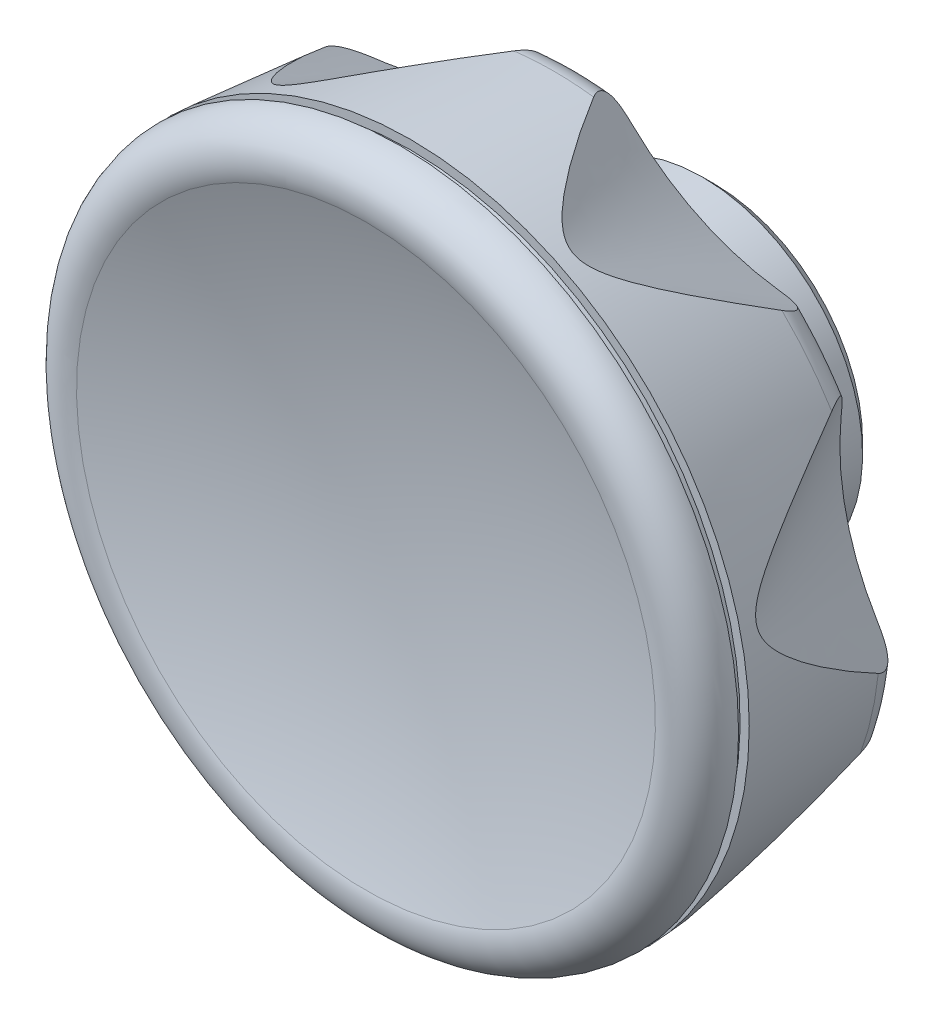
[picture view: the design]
ISO-10303-21;
HEADER;
FILE_DESCRIPTION(('STEP AP214'),'2;1');
FILE_NAME('part.step','',(''),(''),'','','');
FILE_SCHEMA(('AUTOMOTIVE_DESIGN { 1 0 10303 214 1 1 1 1 }'));
ENDSEC;
DATA;
#1=APPLICATION_CONTEXT('core data for automotive mechanical design processes');
#2=APPLICATION_PROTOCOL_DEFINITION('international standard','automotive_design',2000,#1);
#3=PRODUCT_CONTEXT('',#1,'mechanical');
#4=PRODUCT('Part','Part','',(#3));
#5=PRODUCT_RELATED_PRODUCT_CATEGORY('part','',(#4));
#6=PRODUCT_DEFINITION_FORMATION('','',#4);
#7=PRODUCT_DEFINITION_CONTEXT('part definition',#1,'design');
#8=PRODUCT_DEFINITION('design','',#6,#7);
#9=PRODUCT_DEFINITION_SHAPE('','',#8);
#10=(LENGTH_UNIT() NAMED_UNIT(*) SI_UNIT(.MILLI.,.METRE.));
#11=(NAMED_UNIT(*) PLANE_ANGLE_UNIT() SI_UNIT($,.RADIAN.));
#12=(NAMED_UNIT(*) SI_UNIT($,.STERADIAN.) SOLID_ANGLE_UNIT());
#13=UNCERTAINTY_MEASURE_WITH_UNIT(LENGTH_MEASURE(1.E-05),#10,'distance_accuracy_value','');
#14=(GEOMETRIC_REPRESENTATION_CONTEXT(3) GLOBAL_UNCERTAINTY_ASSIGNED_CONTEXT((#13)) GLOBAL_UNIT_ASSIGNED_CONTEXT((#10,
#11,#12)) REPRESENTATION_CONTEXT('',''));
#15=CARTESIAN_POINT('',(0.,0.,0.));
#16=DIRECTION('',(0.,0.,1.));
#17=DIRECTION('',(1.,0.,0.));
#18=AXIS2_PLACEMENT_3D('',#15,#16,#17);
#19=CARTESIAN_POINT('',(0.,0.,13.5));
#20=DIRECTION('',(0.,0.,1.));
#21=DIRECTION('',(0.,1.,0.));
#22=AXIS2_PLACEMENT_3D('',#19,#20,#21);
#23=TOROIDAL_SURFACE('',#22,24.4738282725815,2.4999999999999);
#24=CARTESIAN_POINT('',(0.,0.,11.));
#25=DIRECTION('',(0.,0.,1.));
#26=DIRECTION('',(0.,1.,0.));
#27=AXIS2_PLACEMENT_3D('',#24,#25,#26);
#28=CIRCLE('',#27,24.4738282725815);
#29=CARTESIAN_POINT('',(-16.2379624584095,18.3111126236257,11.));
#30=VERTEX_POINT('',#29);
#31=CARTESIAN_POINT('',(-21.4653013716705,11.7562369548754,11.));
#32=VERTEX_POINT('',#31);
#33=EDGE_CURVE('E135',#30,#32,#28,.T.);
#34=ORIENTED_EDGE('',*,*,#33,.T.);
#35=CARTESIAN_POINT('',(-21.4653013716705,11.7562369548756,11.));
#36=CARTESIAN_POINT('',(-21.4754382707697,11.8601222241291,11.000030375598));
#37=CARTESIAN_POINT('',(-21.4872751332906,11.9639124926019,11.0020766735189));
#38=CARTESIAN_POINT('',(-21.5148402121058,12.1711325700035,11.0112222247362));
#39=CARTESIAN_POINT('',(-21.5305827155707,12.2745596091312,11.0183402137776));
#40=CARTESIAN_POINT('',(-21.5666560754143,12.4816775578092,11.0388207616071));
#41=CARTESIAN_POINT('',(-21.5870535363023,12.5853482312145,11.0522773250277));
#42=CARTESIAN_POINT('',(-21.6327777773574,12.79018793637,11.086761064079));
#43=CARTESIAN_POINT('',(-21.6580966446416,12.8913606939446,11.1077761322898));
#44=CARTESIAN_POINT('',(-21.7159025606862,13.096009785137,11.1604458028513));
#45=CARTESIAN_POINT('',(-21.7487343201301,13.1992460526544,11.1926745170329));
#46=CARTESIAN_POINT('',(-21.8208966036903,13.3985520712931,11.2692171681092));
#47=CARTESIAN_POINT('',(-21.8602062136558,13.494643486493,11.313492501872));
#48=CARTESIAN_POINT('',(-21.9242907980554,13.631369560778,11.3905180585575));
#49=CARTESIAN_POINT('',(-21.9466893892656,13.6760092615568,11.4182052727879));
#50=CARTESIAN_POINT('',(-21.9930436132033,13.7619364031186,11.4772174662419));
#51=CARTESIAN_POINT('',(-22.0169983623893,13.8032257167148,11.5085403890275));
#52=CARTESIAN_POINT('',(-22.0662965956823,13.8818232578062,11.574842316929));
#53=CARTESIAN_POINT('',(-22.0916394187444,13.919133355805,11.6098195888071));
#54=CARTESIAN_POINT('',(-22.1434758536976,13.9891694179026,11.6833341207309));
#55=CARTESIAN_POINT('',(-22.1699692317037,14.0218963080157,11.7218706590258));
#56=CARTESIAN_POINT('',(-22.2204575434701,14.0784837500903,11.7972787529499));
#57=CARTESIAN_POINT('',(-22.2443568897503,14.1029401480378,11.8337680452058));
#58=CARTESIAN_POINT('',(-22.2925479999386,14.147619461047,11.9090357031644));
#59=CARTESIAN_POINT('',(-22.3168398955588,14.1678409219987,11.9478148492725));
#60=CARTESIAN_POINT('',(-22.3655101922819,14.2038164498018,12.0272744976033));
#61=CARTESIAN_POINT('',(-22.3898884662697,14.2195754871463,12.0679528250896));
#62=CARTESIAN_POINT('',(-22.4384945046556,14.2465760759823,12.1508760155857));
#63=CARTESIAN_POINT('',(-22.4627222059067,14.2578158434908,12.1931214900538));
#64=CARTESIAN_POINT('',(-22.5288434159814,14.2825299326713,12.3109990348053));
#65=CARTESIAN_POINT('',(-22.5703388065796,14.2913426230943,12.3878768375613));
#66=CARTESIAN_POINT('',(-22.6510509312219,14.2958836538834,12.5432786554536));
#67=CARTESIAN_POINT('',(-22.6902625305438,14.2915835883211,12.6218058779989));
#68=CARTESIAN_POINT('',(-22.7755265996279,14.2684993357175,12.7992847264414));
#69=CARTESIAN_POINT('',(-22.8206927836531,14.246227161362,12.8982168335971));
#70=CARTESIAN_POINT('',(-22.8841902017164,14.2010917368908,13.044286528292));
#71=CARTESIAN_POINT('',(-22.9046065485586,14.184142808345,13.0924834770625));
#72=CARTESIAN_POINT('',(-22.9440559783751,14.146710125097,13.187982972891));
#73=CARTESIAN_POINT('',(-22.9630908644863,14.1262311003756,13.2352866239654));
#74=CARTESIAN_POINT('',(-22.9814573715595,14.1041446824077,13.2821097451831));
#75=B_SPLINE_CURVE_WITH_KNOTS('',3,(#35,#36,#37,#38,#39,#40,#41,#42,#43,#44,#45,#46,#47,#48,#49,
#50,#51,#52,#53,#54,#55,#56,#57,#58,#59,#60,#61,#62,#63,#64,#65,#66,#67,#68,#69,#70,#71,#72,#73,
#74),.UNSPECIFIED.,.F.,.F.,(4,2,2,2,2,2,2,2,2,2,2,2,2,2,2,2,2,2,2,4),(0.,0.313209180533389,
0.627581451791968,0.946770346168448,1.26545021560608,1.60369981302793,1.94087800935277,
2.11199734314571,2.28302035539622,2.45396261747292,2.62487029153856,2.77466826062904,
2.92451758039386,3.07419932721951,3.22394010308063,3.48614173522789,3.74891177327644,
4.08027673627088,4.24522540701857,4.40995475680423),.UNSPECIFIED.);
#76=CARTESIAN_POINT('',(-22.981457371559,14.1041446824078,13.2821097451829));
#77=VERTEX_POINT('',#76);
#78=EDGE_CURVE('E119',#32,#77,#75,.T.);
#79=ORIENTED_EDGE('',*,*,#78,.T.);
#80=CARTESIAN_POINT('',(0.,0.,13.282109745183));
#81=DIRECTION('',(0.,0.,1.));
#82=DIRECTION('',(0.,1.,0.));
#83=AXIS2_PLACEMENT_3D('',#80,#81,#82);
#84=CIRCLE('',#83,26.9643149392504);
#85=CARTESIAN_POINT('',(-18.8643796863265,19.2667968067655,13.282109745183));
#86=VERTEX_POINT('',#85);
#87=EDGE_CURVE('E150',#86,#77,#84,.T.);
#88=ORIENTED_EDGE('',*,*,#87,.F.);
#89=CARTESIAN_POINT('',(-18.8643796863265,19.2667968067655,13.282109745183));
#90=CARTESIAN_POINT('',(-18.8981743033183,19.2226732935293,13.1915305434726));
#91=CARTESIAN_POINT('',(-18.9255552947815,19.1772447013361,13.0988167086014));
#92=CARTESIAN_POINT('',(-18.9651950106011,19.0843052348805,12.9100927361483));
#93=CARTESIAN_POINT('',(-18.9773008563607,19.0367781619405,12.8140590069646));
#94=CARTESIAN_POINT('',(-18.983341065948,18.9407957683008,12.6209607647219));
#95=CARTESIAN_POINT('',(-18.9771650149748,18.8923365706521,12.5238935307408));
#96=CARTESIAN_POINT('',(-18.9442986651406,18.7968510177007,12.3329550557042));
#97=CARTESIAN_POINT('',(-18.917699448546,18.7498192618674,12.2390715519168));
#98=CARTESIAN_POINT('',(-18.8474169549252,18.6641060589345,12.0674765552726));
#99=CARTESIAN_POINT('',(-18.8058006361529,18.6250650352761,11.9890989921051));
#100=CARTESIAN_POINT('',(-18.7069025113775,18.5516039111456,11.8403817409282));
#101=CARTESIAN_POINT('',(-18.6496092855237,18.5171872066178,11.7700479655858));
#102=CARTESIAN_POINT('',(-18.5279204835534,18.457227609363,11.6454449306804));
#103=CARTESIAN_POINT('',(-18.4646762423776,18.4311577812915,11.5902907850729));
#104=CARTESIAN_POINT('',(-18.3299240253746,18.3843608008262,11.4887242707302));
#105=CARTESIAN_POINT('',(-18.2584221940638,18.3636297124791,11.4423054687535));
#106=CARTESIAN_POINT('',(-18.0741590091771,18.3189481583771,11.3379996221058));
#107=CARTESIAN_POINT('',(-17.9578593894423,18.2981009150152,11.2850492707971));
#108=CARTESIAN_POINT('',(-17.7173155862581,18.2668011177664,11.1949523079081));
#109=CARTESIAN_POINT('',(-17.5930199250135,18.2564250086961,11.1579230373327));
#110=CARTESIAN_POINT('',(-17.3654004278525,18.2458816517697,11.1030967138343));
#111=CARTESIAN_POINT('',(-17.2626807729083,18.2441255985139,11.0829631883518));
#112=CARTESIAN_POINT('',(-17.0560091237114,18.2457463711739,11.0499258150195));
#113=CARTESIAN_POINT('',(-16.9520556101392,18.2491303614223,11.0370320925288));
#114=CARTESIAN_POINT('',(-16.7461255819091,18.260237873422,11.0174873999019));
#115=CARTESIAN_POINT('',(-16.6441552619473,18.2678653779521,11.0107067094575));
#116=CARTESIAN_POINT('',(-16.4406884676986,18.2868392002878,11.0019849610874));
#117=CARTESIAN_POINT('',(-16.3391915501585,18.2981729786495,11.000027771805));
#118=CARTESIAN_POINT('',(-16.2379624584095,18.3111126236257,11.));
#119=B_SPLINE_CURVE_WITH_KNOTS('',3,(#89,#90,#91,#92,#93,#94,#95,#96,#97,#98,#99,#100,#101,#102,
#103,#104,#105,#106,#107,#108,#109,#110,#111,#112,#113,#114,#115,#116,#117,#118),.UNSPECIFIED.,
.F.,.F.,(4,2,2,2,2,2,2,2,2,2,2,2,2,2,4),(0.,0.319088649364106,0.641346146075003,
0.96555390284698,1.28832411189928,1.57749027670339,1.86686764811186,2.12940978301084,
2.39175780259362,2.77800167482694,3.16704536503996,3.48068996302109,3.79477212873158,
4.10202079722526,4.40824052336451),.UNSPECIFIED.);
#120=EDGE_CURVE('E140',#86,#30,#119,.T.);
#121=ORIENTED_EDGE('',*,*,#120,.T.);
#122=EDGE_LOOP('',(#34,#79,#88,#121));
#123=FACE_BOUND('',#122,.T.);
#124=ADVANCED_FACE('F14',(#123),#23,.T.);
#125=CARTESIAN_POINT('',(-26.8251366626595,-2.73611461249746,13.282109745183));
#126=VERTEX_POINT('',#125);
#127=CARTESIAN_POINT('',(-25.355768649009,-9.17383651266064,13.282109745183));
#128=VERTEX_POINT('',#127);
#129=EDGE_CURVE('E157',#126,#128,#84,.T.);
#130=ORIENTED_EDGE('',*,*,#129,.F.);
#131=CARTESIAN_POINT('',(-26.8251366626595,-2.73611461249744,13.282109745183));
#132=CARTESIAN_POINT('',(-26.8117101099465,-2.79004686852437,13.1915305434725));
#133=CARTESIAN_POINT('',(-26.7932643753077,-2.83977845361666,13.0988167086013));
#134=CARTESIAN_POINT('',(-26.7453163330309,-2.92871684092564,12.9100927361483));
#135=CARTESIAN_POINT('',(-26.7157060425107,-2.96781421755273,12.8140590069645));
#136=CARTESIAN_POINT('',(-26.6444299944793,-3.0323806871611,12.620960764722));
#137=CARTESIAN_POINT('',(-26.602692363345,-3.0577658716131,12.5238935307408));
#138=CARTESIAN_POINT('',(-26.507546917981,-3.09160419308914,12.3329550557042));
#139=CARTESIAN_POINT('',(-26.4541916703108,-3.10013190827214,12.2390715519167));
#140=CARTESIAN_POINT('',(-26.3433579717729,-3.09862415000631,12.0674765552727));
#141=CARTESIAN_POINT('',(-26.2868871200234,-3.09042888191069,11.9890989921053));
#142=CARTESIAN_POINT('',(-26.1677909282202,-3.05890947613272,11.8403817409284));
#143=CARTESIAN_POINT('',(-26.1051611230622,-3.03557429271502,11.7700479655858));
#144=CARTESIAN_POINT('',(-25.9824110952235,-2.97781835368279,11.6454449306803));
#145=CARTESIAN_POINT('',(-25.9225967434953,-2.94462628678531,11.590290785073));
#146=CARTESIAN_POINT('',(-25.8019927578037,-2.86845020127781,11.4887242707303));
#147=CARTESIAN_POINT('',(-25.7412038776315,-2.82547344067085,11.4423054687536));
#148=CARTESIAN_POINT('',(-25.5913842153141,-2.70926917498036,11.3379996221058));
#149=CARTESIAN_POINT('',(-25.5025735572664,-2.63134051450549,11.2850492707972));
#150=CARTESIAN_POINT('',(-25.3281257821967,-2.46279090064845,11.194952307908));
#151=CARTESIAN_POINT('',(-25.2425163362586,-2.37208203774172,11.1579230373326));
#152=CARTESIAN_POINT('',(-25.0923547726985,-2.20069562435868,11.1030967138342));
#153=CARTESIAN_POINT('',(-25.0269371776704,-2.12148104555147,11.0829631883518));
#154=CARTESIAN_POINT('',(-24.8993466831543,-1.95888810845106,11.0499258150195));
#155=CARTESIAN_POINT('',(-24.8371784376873,-1.87550409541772,11.0370320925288));
#156=CARTESIAN_POINT('',(-24.7174673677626,-1.70757609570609,11.0174873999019));
#157=CARTESIAN_POINT('',(-24.6598533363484,-1.62309681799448,11.0107067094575));
#158=CARTESIAN_POINT('',(-24.5478281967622,-1.45219008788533,11.0019849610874));
#159=CARTESIAN_POINT('',(-24.4934070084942,-1.365770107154,11.000027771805));
#160=CARTESIAN_POINT('',(-24.4404083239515,-1.27855827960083,11.));
#161=B_SPLINE_CURVE_WITH_KNOTS('',3,(#131,#132,#133,#134,#135,#136,#137,#138,#139,#140,#141,
#142,#143,#144,#145,#146,#147,#148,#149,#150,#151,#152,#153,#154,#155,#156,#157,#158,#159,#160),
.UNSPECIFIED.,.F.,.F.,(4,2,2,2,2,2,2,2,2,2,2,2,2,2,4),(0.,0.319088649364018,0.641346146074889,
0.965553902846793,1.288324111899,1.57749027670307,1.8668676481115,2.12940978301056,
2.39175780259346,2.77800167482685,3.16704536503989,3.4806899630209,3.79477212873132,
4.10202079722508,4.40824052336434),.UNSPECIFIED.);
#162=CARTESIAN_POINT('',(-24.4404083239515,-1.27855827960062,11.));
#163=VERTEX_POINT('',#162);
#164=EDGE_CURVE('E34',#126,#163,#161,.T.);
#165=ORIENTED_EDGE('',*,*,#164,.T.);
#166=CARTESIAN_POINT('',(-22.5747926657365,-9.45235454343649,11.));
#167=VERTEX_POINT('',#166);
#168=EDGE_CURVE('E137',#163,#167,#28,.T.);
#169=ORIENTED_EDGE('',*,*,#168,.T.);
#170=CARTESIAN_POINT('',(-22.5747926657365,-9.45235454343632,11.));
#171=CARTESIAN_POINT('',(-22.6623336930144,-9.39550848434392,11.000030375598));
#172=CARTESIAN_POINT('',(-22.7508603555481,-9.34005074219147,11.0020766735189));
#173=CARTESIAN_POINT('',(-22.930058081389,-9.23240238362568,11.0112222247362));
#174=CARTESIAN_POINT('',(-23.0207358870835,-9.18022466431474,11.0183402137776));
#175=CARTESIAN_POINT('',(-23.2051585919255,-9.07929202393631,11.0388207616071));
#176=CARTESIAN_POINT('',(-23.2989291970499,-9.03060179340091,11.0522773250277));
#177=CARTESIAN_POINT('',(-23.4875879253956,-8.93863497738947,11.0867610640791));
#178=CARTESIAN_POINT('',(-23.5824740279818,-8.89534988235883,11.1077761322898));
#179=CARTESIAN_POINT('',(-23.7785165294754,-8.81294774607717,11.1604458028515));
#180=CARTESIAN_POINT('',(-23.8797001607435,-8.77424988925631,11.1926745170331));
#181=CARTESIAN_POINT('',(-24.0805163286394,-8.70640336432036,11.2692171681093));
#182=CARTESIAN_POINT('',(-24.1801527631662,-8.67722483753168,11.3134925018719));
#183=CARTESIAN_POINT('',(-24.3270055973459,-8.64208087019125,11.3905180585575));
#184=CARTESIAN_POINT('',(-24.3758716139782,-8.63176039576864,11.4182052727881));
#185=CARTESIAN_POINT('',(-24.4719535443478,-8.6144268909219,11.4772174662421));
#186=CARTESIAN_POINT('',(-24.5191703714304,-8.60741200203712,11.5085403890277));
#187=CARTESIAN_POINT('',(-24.611357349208,-8.59695014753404,11.5748423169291));
#188=CARTESIAN_POINT('',(-24.6563285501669,-8.59350149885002,11.6098195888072));
#189=CARTESIAN_POINT('',(-24.7434044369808,-8.59036208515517,11.683334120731));
#190=CARTESIAN_POINT('',(-24.785509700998,-8.59067055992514,11.721870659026));
#191=CARTESIAN_POINT('',(-24.8612304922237,-8.594862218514,11.79727875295));
#192=CARTESIAN_POINT('',(-24.8952522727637,-8.59829916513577,11.8337680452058));
#193=CARTESIAN_POINT('',(-24.960230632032,-8.60811939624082,11.9090357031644));
#194=CARTESIAN_POINT('',(-24.9911861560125,-8.61450369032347,11.9478148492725));
#195=CARTESIAN_POINT('',(-25.0496583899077,-8.63012528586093,12.0272744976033));
#196=CARTESIAN_POINT('',(-25.0771789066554,-8.63935938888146,12.0679528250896));
#197=CARTESIAN_POINT('',(-25.1285941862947,-8.66052652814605,12.1508760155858));
#198=CARTESIAN_POINT('',(-25.152487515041,-8.67246062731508,12.1931214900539));
#199=CARTESIAN_POINT('',(-25.2130356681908,-8.70874728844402,12.3109990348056));
#200=CARTESIAN_POINT('',(-25.2457976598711,-8.73569506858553,12.3878768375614));
#201=CARTESIAN_POINT('',(-25.2996711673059,-8.79596706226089,12.5432786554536));
#202=CARTESIAN_POINT('',(-25.3207572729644,-8.82930497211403,12.621805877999));
#203=CARTESIAN_POINT('',(-25.3558705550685,-8.91035990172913,12.7992847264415));
#204=CARTESIAN_POINT('',(-25.3666181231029,-8.9595587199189,12.8982168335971));
#205=CARTESIAN_POINT('',(-25.3709198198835,-9.03734447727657,13.0442865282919));
#206=CARTESIAN_POINT('',(-25.3703979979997,-9.0638741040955,13.0924834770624));
#207=CARTESIAN_POINT('',(-25.3657282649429,-9.11805580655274,13.1879829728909));
#208=CARTESIAN_POINT('',(-25.3615851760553,-9.14570634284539,13.2352866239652));
#209=CARTESIAN_POINT('',(-25.355768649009,-9.17383651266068,13.282109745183));
#210=B_SPLINE_CURVE_WITH_KNOTS('',3,(#170,#171,#172,#173,#174,#175,#176,#177,#178,#179,#180,
#181,#182,#183,#184,#185,#186,#187,#188,#189,#190,#191,#192,#193,#194,#195,#196,#197,#198,#199,
#200,#201,#202,#203,#204,#205,#206,#207,#208,#209),.UNSPECIFIED.,.F.,.F.,(4,2,2,2,2,2,2,2,2,2,2,
2,2,2,2,2,2,2,2,4),(0.,0.313209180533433,0.627581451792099,0.946770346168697,1.26545021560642,
1.60369981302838,1.9408780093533,2.11199734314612,2.28302035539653,2.45396261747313,
2.62487029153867,2.77466826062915,2.92451758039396,3.07419932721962,3.22394010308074,
3.48614173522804,3.74891177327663,4.08027673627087,4.24522540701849,4.40995475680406),.UNSPECIFIED.);
#211=EDGE_CURVE('E301',#167,#128,#210,.T.);
#212=ORIENTED_EDGE('',*,*,#211,.T.);
#213=EDGE_LOOP('',(#130,#165,#169,#212));
#214=FACE_BOUND('',#213,.T.);
#215=ADVANCED_FACE('F411',(#214),#23,.T.);
#216=CARTESIAN_POINT('',(-14.586018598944,-22.6786759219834,13.282109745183));
#217=VERTEX_POINT('',#216);
#218=CARTESIAN_POINT('',(-8.63666897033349,-25.5437317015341,13.282109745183));
#219=VERTEX_POINT('',#218);
#220=EDGE_CURVE('E161',#217,#219,#84,.T.);
#221=ORIENTED_EDGE('',*,*,#220,.F.);
#222=CARTESIAN_POINT('',(-14.586018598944,-22.6786759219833,13.282109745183));
#223=CARTESIAN_POINT('',(-14.5354813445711,-22.7018048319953,13.1915305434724));
#224=CARTESIAN_POINT('',(-14.4850988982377,-22.7183905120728,13.0988167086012));
#225=CARTESIAN_POINT('',(-14.3856689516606,-22.736355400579,12.9100927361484));
#226=CARTESIAN_POINT('',(-14.336639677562,-22.7375819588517,12.8140590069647));
#227=CARTESIAN_POINT('',(-14.2417196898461,-22.7221126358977,12.620960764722));
#228=CARTESIAN_POINT('',(-14.1958497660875,-22.7053082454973,12.5238935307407));
#229=CARTESIAN_POINT('',(-14.1100716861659,-22.6520183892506,12.3329550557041));
#230=CARTESIAN_POINT('',(-14.070137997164,-22.6156205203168,12.2390715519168));
#231=CARTESIAN_POINT('',(-14.0022131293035,-22.5280271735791,12.0674765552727));
#232=CARTESIAN_POINT('',(-13.9734114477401,-22.4787668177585,11.9890989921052));
#233=CARTESIAN_POINT('',(-13.9237990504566,-22.3660016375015,11.8403817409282));
#234=CARTESIAN_POINT('',(-13.9029941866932,-22.3024864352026,11.7700479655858));
#235=CARTESIAN_POINT('',(-13.8716162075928,-22.1705063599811,11.6454449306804));
#236=CARTESIAN_POINT('',(-13.8602731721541,-22.1030467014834,11.590290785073));
#237=CARTESIAN_POINT('',(-13.8446346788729,-21.9612596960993,11.4887242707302));
#238=CARTESIAN_POINT('',(-13.8403340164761,-21.8869374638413,11.4423054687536));
#239=CARTESIAN_POINT('',(-13.8377751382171,-21.6973515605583,11.3379996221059));
#240=CARTESIAN_POINT('',(-13.8433296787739,-21.5793288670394,11.2850492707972));
#241=CARTESIAN_POINT('',(-13.8663406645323,-21.3378511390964,11.194952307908));
#242=CARTESIAN_POINT('',(-13.8838830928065,-21.2143629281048,11.1579230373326));
#243=CARTESIAN_POINT('',(-13.9242541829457,-20.9901042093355,11.1030967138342));
#244=CARTESIAN_POINT('',(-13.9453994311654,-20.8895691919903,11.0829631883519));
#245=CARTESIAN_POINT('',(-13.9929683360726,-20.6884398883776,11.0499258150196));
#246=CARTESIAN_POINT('',(-14.0193993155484,-20.5878457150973,11.0370320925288));
#247=CARTESIAN_POINT('',(-14.0760520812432,-20.3895504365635,11.0174873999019));
#248=CARTESIAN_POINT('',(-14.1061788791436,-20.2918340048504,11.0107067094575));
#249=CARTESIAN_POINT('',(-14.1699526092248,-20.097690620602,11.0019849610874));
#250=CARTESIAN_POINT('',(-14.2035874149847,-20.001260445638,11.000027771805));
#251=CARTESIAN_POINT('',(-14.238728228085,-19.9054487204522,11.));
#252=B_SPLINE_CURVE_WITH_KNOTS('',3,(#222,#223,#224,#225,#226,#227,#228,#229,#230,#231,#232,
#233,#234,#235,#236,#237,#238,#239,#240,#241,#242,#243,#244,#245,#246,#247,#248,#249,#250,#251),
.UNSPECIFIED.,.F.,.F.,(4,2,2,2,2,2,2,2,2,2,2,2,2,2,4),(0.,0.319088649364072,0.641346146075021,
0.965553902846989,1.28832411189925,1.5774902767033,1.86686764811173,2.12940978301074,
2.39175780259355,2.77800167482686,3.16704536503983,3.48068996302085,3.79477212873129,
4.10202079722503,4.40824052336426),.UNSPECIFIED.);
#253=CARTESIAN_POINT('',(-14.238728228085,-19.905448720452,11.));
#254=VERTEX_POINT('',#253);
#255=EDGE_CURVE('E42',#217,#254,#252,.T.);
#256=ORIENTED_EDGE('',*,*,#255,.T.);
#257=CARTESIAN_POINT('',(-6.685004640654,-23.5431302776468,11.));
#258=VERTEX_POINT('',#257);
#259=EDGE_CURVE('E147',#254,#258,#28,.T.);
#260=ORIENTED_EDGE('',*,*,#259,.T.);
#261=CARTESIAN_POINT('',(-6.685004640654,-23.5431302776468,11.));
#262=CARTESIAN_POINT('',(-6.78402961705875,-23.5761296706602,11.000030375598));
#263=CARTESIAN_POINT('',(-6.88258369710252,-23.6107652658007,11.0020766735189));
#264=CARTESIAN_POINT('',(-7.07847452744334,-23.6837500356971,11.0112222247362));
#265=CARTESIAN_POINT('',(-7.17580539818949,-23.7221125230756,11.0183402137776));
#266=CARTESIAN_POINT('',(-7.36970338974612,-23.8033695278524,11.0388207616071));
#267=CARTESIAN_POINT('',(-7.46623596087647,-23.8463244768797,11.0522773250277));
#268=CARTESIAN_POINT('',(-7.65576530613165,-23.9364834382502,11.0867610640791));
#269=CARTESIAN_POINT('',(-7.74876747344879,-23.9836805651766,11.1077761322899));
#270=CARTESIAN_POINT('',(-7.93542255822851,-24.0855758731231,11.1604458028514));
#271=CARTESIAN_POINT('',(-8.02876472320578,-24.1405567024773,11.192674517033));
#272=CARTESIAN_POINT('',(-8.2070161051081,-24.2552594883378,11.2692171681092));
#273=CARTESIAN_POINT('',(-8.29195109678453,-24.3149658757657,11.313492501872));
#274=CARTESIAN_POINT('',(-8.41098900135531,-24.4078681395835,11.3905180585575));
#275=CARTESIAN_POINT('',(-8.44952533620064,-24.4396384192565,11.418205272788));
#276=CARTESIAN_POINT('',(-8.52298331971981,-24.5039510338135,11.477217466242));
#277=CARTESIAN_POINT('',(-8.55790699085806,-24.5364929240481,11.5085403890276));
#278=CARTESIAN_POINT('',(-8.62356403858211,-24.602044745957,11.5748423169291));
#279=CARTESIAN_POINT('',(-8.65429938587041,-24.6350544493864,11.6098195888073));
#280=CARTESIAN_POINT('',(-8.71104480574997,-24.7011757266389,11.683334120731));
#281=CARTESIAN_POINT('',(-8.73705583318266,-24.7342872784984,11.7218706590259));
#282=CARTESIAN_POINT('',(-8.78098980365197,-24.796101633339,11.7972787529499));
#283=CARTESIAN_POINT('',(-8.79951492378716,-24.824843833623,11.8337680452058));
#284=CARTESIAN_POINT('',(-8.8323505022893,-24.8817687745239,11.9090357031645));
#285=CARTESIAN_POINT('',(-8.84665951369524,-24.9099513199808,11.9478148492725));
#286=CARTESIAN_POINT('',(-8.87090290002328,-24.9654066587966,12.0272744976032));
#287=CARTESIAN_POINT('',(-8.88084214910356,-24.9926804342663,12.0679528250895));
#288=CARTESIAN_POINT('',(-8.89634991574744,-25.0460760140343,12.1508760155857));
#289=CARTESIAN_POINT('',(-8.90191670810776,-25.0721973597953,12.1931214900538));
#290=CARTESIAN_POINT('',(-8.91129781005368,-25.1421601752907,12.3109990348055));
#291=CARTESIAN_POINT('',(-8.91065595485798,-25.1845761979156,12.3878768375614));
#292=CARTESIAN_POINT('',(-8.8971229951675,-25.2642751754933,12.5432786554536));
#293=CARTESIAN_POINT('',(-8.88420533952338,-25.3015468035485,12.621805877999));
#294=CARTESIAN_POINT('',(-8.84272681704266,-25.3795363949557,12.7992847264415));
#295=CARTESIAN_POINT('',(-8.81096263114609,-25.4186141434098,12.8982168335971));
#296=CARTESIAN_POINT('',(-8.75282934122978,-25.4704759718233,13.044286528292));
#297=CARTESIAN_POINT('',(-8.73176229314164,-25.486608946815,13.0924834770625));
#298=CARTESIAN_POINT('',(-8.68648980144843,-25.5167397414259,13.187982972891));
#299=CARTESIAN_POINT('',(-8.66228856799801,-25.5307403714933,13.2352866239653));
#300=CARTESIAN_POINT('',(-8.63666897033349,-25.5437317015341,13.2821097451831));
#301=B_SPLINE_CURVE_WITH_KNOTS('',3,(#261,#262,#263,#264,#265,#266,#267,#268,#269,#270,#271,
#272,#273,#274,#275,#276,#277,#278,#279,#280,#281,#282,#283,#284,#285,#286,#287,#288,#289,#290,
#291,#292,#293,#294,#295,#296,#297,#298,#299,#300),.UNSPECIFIED.,.F.,.F.,(4,2,2,2,2,2,2,2,2,2,2,
2,2,2,2,2,2,2,2,4),(0.,0.313209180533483,0.627581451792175,0.946770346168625,1.26545021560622,
1.60369981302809,1.940878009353,2.11199734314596,2.28302035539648,2.45396261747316,
2.62487029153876,2.77466826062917,2.92451758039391,3.07419932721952,3.22394010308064,
3.48614173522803,3.74891177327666,4.0802767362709,4.24522540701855,4.40995475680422),.UNSPECIFIED.);
#302=EDGE_CURVE('E317',#258,#219,#301,.T.);
#303=ORIENTED_EDGE('',*,*,#302,.T.);
#304=EDGE_LOOP('',(#221,#256,#260,#303));
#305=FACE_BOUND('',#304,.T.);
#306=ADVANCED_FACE('F441',(#305),#23,.T.);
#307=CARTESIAN_POINT('',(8.636668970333,-25.5437317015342,13.282109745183));
#308=VERTEX_POINT('',#307);
#309=CARTESIAN_POINT('',(14.586018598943,-22.6786759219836,13.282109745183));
#310=VERTEX_POINT('',#309);
#311=EDGE_CURVE('E449',#308,#310,#84,.T.);
#312=ORIENTED_EDGE('',*,*,#311,.F.);
#313=CARTESIAN_POINT('',(8.636668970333,-25.5437317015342,13.2821097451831));
#314=CARTESIAN_POINT('',(8.68626134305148,-25.5186407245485,13.1915305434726));
#315=CARTESIAN_POINT('',(8.73064149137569,-25.4895911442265,13.0988167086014));
#316=CARTESIAN_POINT('',(8.80668056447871,-25.4230546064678,12.9100927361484));
#317=CARTESIAN_POINT('',(8.83820877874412,-25.3854867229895,12.8140590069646));
#318=CARTESIAN_POINT('',(8.88529601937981,-25.3016303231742,12.6209607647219));
#319=CARTESIAN_POINT('',(8.90075724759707,-25.2552904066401,12.5238935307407));
#320=CARTESIAN_POINT('',(8.91257531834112,-25.1550007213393,12.3329550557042));
#321=CARTESIAN_POINT('',(8.90901656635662,-25.1010856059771,12.2390715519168));
#322=CARTESIAN_POINT('',(8.88288379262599,-24.9933662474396,12.0674765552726));
#323=CARTESIAN_POINT('',(8.8623280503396,-24.9401348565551,11.9890989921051));
#324=CARTESIAN_POINT('',(8.80509750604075,-24.8310383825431,11.8403817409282));
#325=CARTESIAN_POINT('',(8.76841094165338,-24.7751714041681,11.7700479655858));
#326=CARTESIAN_POINT('',(8.68478861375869,-24.6683508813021,11.6454449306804));
#327=CARTESIAN_POINT('',(8.63911879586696,-24.6174221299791,11.5902907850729));
#328=CARTESIAN_POINT('',(8.53801569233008,-24.5167927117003,11.4887242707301));
#329=CARTESIAN_POINT('',(8.48258965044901,-24.4670911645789,11.4423054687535));
#330=CARTESIAN_POINT('',(8.33596085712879,-24.3468856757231,11.3379996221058));
#331=CARTESIAN_POINT('',(8.24022380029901,-24.277642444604,11.285049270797));
#332=CARTESIAN_POINT('',(8.03708179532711,-24.1450742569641,11.194952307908));
#333=CARTESIAN_POINT('',(7.9295972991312,-24.081795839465,11.1579230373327));
#334=CARTESIAN_POINT('',(7.72909380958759,-23.9735362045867,11.1030967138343));
#335=CARTESIAN_POINT('',(7.63730852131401,-23.9273856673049,11.0829631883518));
#336=CARTESIAN_POINT('',(7.45040057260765,-23.8391744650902,11.0499258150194));
#337=CARTESIAN_POINT('',(7.35527343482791,-23.7971195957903,11.0370320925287));
#338=CARTESIAN_POINT('',(7.16491752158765,-23.7177774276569,11.0174873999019));
#339=CARTESIAN_POINT('',(7.06973598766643,-23.6804063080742,11.0107067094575));
#340=CARTESIAN_POINT('',(6.87818630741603,-23.6092201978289,11.0019849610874));
#341=CARTESIAN_POINT('',(6.78182320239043,-23.5753937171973,11.000027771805));
#342=CARTESIAN_POINT('',(6.6850046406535,-23.543130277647,11.));
#343=B_SPLINE_CURVE_WITH_KNOTS('',3,(#313,#314,#315,#316,#317,#318,#319,#320,#321,#322,#323,
#324,#325,#326,#327,#328,#329,#330,#331,#332,#333,#334,#335,#336,#337,#338,#339,#340,#341,#342),
.UNSPECIFIED.,.F.,.F.,(4,2,2,2,2,2,2,2,2,2,2,2,2,2,4),(0.,0.319088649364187,0.641346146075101,
0.965553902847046,1.28832411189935,1.57749027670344,1.86686764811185,2.12940978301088,
2.39175780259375,2.77800167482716,3.16704536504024,3.48068996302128,3.79477212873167,
4.1020207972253,4.40824052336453),.UNSPECIFIED.);
#344=CARTESIAN_POINT('',(6.685004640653,-23.5431302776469,11.));
#345=VERTEX_POINT('',#344);
#346=EDGE_CURVE('E310',#308,#345,#343,.T.);
#347=ORIENTED_EDGE('',*,*,#346,.T.);
#348=CARTESIAN_POINT('',(14.2387282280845,-19.9054487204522,11.));
#349=VERTEX_POINT('',#348);
#350=EDGE_CURVE('E443',#345,#349,#28,.T.);
#351=ORIENTED_EDGE('',*,*,#350,.T.);
#352=CARTESIAN_POINT('',(14.2387282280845,-19.9054487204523,11.));
#353=CARTESIAN_POINT('',(14.202787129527,-20.0034443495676,11.000030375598));
#354=CARTESIAN_POINT('',(14.168418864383,-20.1020919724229,11.0020766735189));
#355=CARTESIAN_POINT('',(14.1033447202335,-20.3007508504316,11.0112222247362));
#356=CARTESIAN_POINT('',(14.0726529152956,-20.4007658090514,11.0183402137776));
#357=CARTESIAN_POINT('',(14.0152887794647,-20.6030242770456,11.038820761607));
#358=CARTESIAN_POINT('',(13.9886852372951,-20.7052784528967,11.0522773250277));
#359=CARTESIAN_POINT('',(13.9410047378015,-20.9096716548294,11.086761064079));
#360=CARTESIAN_POINT('',(13.9199190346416,-21.0118106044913,11.1077761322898));
#361=CARTESIAN_POINT('',(13.8832064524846,-21.2212741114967,11.1604458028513));
#362=CARTESIAN_POINT('',(13.8679943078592,-21.3285319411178,11.1926745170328));
#363=CARTESIAN_POINT('',(13.8465346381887,-21.5394105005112,11.269217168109));
#364=CARTESIAN_POINT('',(13.8402588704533,-21.6430416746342,11.3134925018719));
#365=CARTESIAN_POINT('',(13.8386738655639,-21.7940328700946,11.3905180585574));
#366=CARTESIAN_POINT('',(13.8394858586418,-21.843970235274,11.4182052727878));
#367=CARTESIAN_POINT('',(13.8439671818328,-21.9415002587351,11.4772174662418));
#368=CARTESIAN_POINT('',(13.8476349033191,-21.9890942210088,11.5085403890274));
#369=CARTESIAN_POINT('',(13.8579488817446,-22.0812978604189,11.5748423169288));
#370=CARTESIAN_POINT('',(13.8645937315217,-22.1259089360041,11.609819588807));
#371=CARTESIAN_POINT('',(13.8809092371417,-22.2115002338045,11.6833341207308));
#372=CARTESIAN_POINT('',(13.8905792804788,-22.2524811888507,11.7218706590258));
#373=CARTESIAN_POINT('',(13.9115153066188,-22.3253707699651,11.7972787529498));
#374=CARTESIAN_POINT('',(13.9224366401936,-22.3577747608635,11.8337680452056));
#375=CARTESIAN_POINT('',(13.9464697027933,-22.4189387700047,11.9090357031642));
#376=CARTESIAN_POINT('',(13.9595821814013,-22.4476975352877,11.9478148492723));
#377=CARTESIAN_POINT('',(13.9878234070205,-22.5012276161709,12.0272744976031));
#378=CARTESIAN_POINT('',(14.0029498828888,-22.5260033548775,12.0679528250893));
#379=CARTESIAN_POINT('',(14.0350272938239,-22.5714194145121,12.1508760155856));
#380=CARTESIAN_POINT('',(14.0519789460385,-22.5920581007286,12.1931214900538));
#381=CARTESIAN_POINT('',(14.1008290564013,-22.6430136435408,12.3109990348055));
#382=CARTESIAN_POINT('',(14.1343914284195,-22.6689577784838,12.3878768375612));
#383=CARTESIAN_POINT('',(14.2051402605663,-22.7080687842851,12.5432786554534));
#384=CARTESIAN_POINT('',(14.2423344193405,-22.7212078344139,12.6218058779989));
#385=CARTESIAN_POINT('',(14.3291705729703,-22.7374043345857,12.7992847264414));
#386=CARTESIAN_POINT('',(14.3795274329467,-22.7369346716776,12.898216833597));
#387=CARTESIAN_POINT('',(14.4563201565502,-22.7238195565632,13.0442865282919));
#388=CARTESIAN_POINT('',(14.4820685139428,-22.7174074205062,13.0924834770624));
#389=CARTESIAN_POINT('',(14.5338526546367,-22.7007982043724,13.1879829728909));
#390=CARTESIAN_POINT('',(14.5598880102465,-22.6906061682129,13.2352866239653));
#391=CARTESIAN_POINT('',(14.586018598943,-22.6786759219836,13.2821097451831));
#392=B_SPLINE_CURVE_WITH_KNOTS('',3,(#352,#353,#354,#355,#356,#357,#358,#359,#360,#361,#362,
#363,#364,#365,#366,#367,#368,#369,#370,#371,#372,#373,#374,#375,#376,#377,#378,#379,#380,#381,
#382,#383,#384,#385,#386,#387,#388,#389,#390,#391),.UNSPECIFIED.,.F.,.F.,(4,2,2,2,2,2,2,2,2,2,2,
2,2,2,2,2,2,2,2,4),(0.,0.313209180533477,0.627581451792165,0.946770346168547,1.26545021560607,
1.60369981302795,1.94087800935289,2.11199734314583,2.28302035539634,2.45396261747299,
2.62487029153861,2.77466826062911,2.9245175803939,3.07419932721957,3.22394010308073,
3.48614173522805,3.74891177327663,4.08027673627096,4.24522540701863,4.40995475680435),.UNSPECIFIED.);
#393=EDGE_CURVE('E333',#349,#310,#392,.T.);
#394=ORIENTED_EDGE('',*,*,#393,.T.);
#395=EDGE_LOOP('',(#312,#347,#351,#394));
#396=FACE_BOUND('',#395,.T.);
#397=ADVANCED_FACE('F422',(#396),#23,.T.);
#398=CARTESIAN_POINT('',(25.3557686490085,-9.17383651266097,13.282109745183));
#399=VERTEX_POINT('',#398);
#400=CARTESIAN_POINT('',(26.825136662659,-2.73611461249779,13.282109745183));
#401=VERTEX_POINT('',#400);
#402=EDGE_CURVE('E168',#399,#401,#84,.T.);
#403=ORIENTED_EDGE('',*,*,#402,.F.);
#404=CARTESIAN_POINT('',(25.3557686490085,-9.17383651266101,13.282109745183));
#405=CARTESIAN_POINT('',(25.3670720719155,-9.11941966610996,13.1915305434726));
#406=CARTESIAN_POINT('',(25.3720307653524,-9.06660975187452,13.0988167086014));
#407=CARTESIAN_POINT('',(25.3674199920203,-8.96567515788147,12.9100927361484));
#408=CARTESIAN_POINT('',(25.3577057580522,-8.91760221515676,12.8140590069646));
#409=CARTESIAN_POINT('',(25.3215025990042,-8.82850431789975,12.6209607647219));
#410=CARTESIAN_POINT('',(25.294912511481,-8.78752377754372,12.5238935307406));
#411=CARTESIAN_POINT('',(25.2238713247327,-8.71575444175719,12.3329550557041));
#412=CARTESIAN_POINT('',(25.1794999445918,-8.68492126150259,12.2390715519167));
#413=CARTESIAN_POINT('',(25.0789880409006,-8.63819076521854,12.0674765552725));
#414=CARTESIAN_POINT('',(25.0245537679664,-8.62107266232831,11.989098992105));
#415=CARTESIAN_POINT('',(24.9035760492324,-8.59779676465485,11.8403817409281));
#416=CARTESIAN_POINT('',(24.8370237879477,-8.59164698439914,11.7700479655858));
#417=CARTESIAN_POINT('',(24.7013704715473,-8.5904240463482,11.6454449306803));
#418=CARTESIAN_POINT('',(24.633078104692,-8.59437659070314,11.5902907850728));
#419=CARTESIAN_POINT('',(24.4913661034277,-8.61068076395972,11.4887242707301));
#420=CARTESIAN_POINT('',(24.4179502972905,-8.62302618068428,11.4423054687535));
#421=CARTESIAN_POINT('',(24.2325483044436,-8.66271829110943,11.3379996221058));
#422=CARTESIAN_POINT('',(24.1187206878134,-8.69439608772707,11.285049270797));
#423=CARTESIAN_POINT('',(23.8884177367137,-8.77056398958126,11.1949523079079));
#424=CARTESIAN_POINT('',(23.771929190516,-8.815145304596,11.1579230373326));
#425=CARTESIAN_POINT('',(23.5622765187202,-8.90440646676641,11.1030967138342));
#426=CARTESIAN_POINT('',(23.4689673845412,-8.94739270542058,11.0829631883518));
#427=CARTESIAN_POINT('',(23.2834658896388,-9.03852443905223,11.0499258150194));
#428=CARTESIAN_POINT('',(23.1912752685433,-9.08667704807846,11.0370320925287));
#429=CARTESIAN_POINT('',(23.0105580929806,-9.18603426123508,11.0174873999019));
#430=CARTESIAN_POINT('',(22.9219954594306,-9.23714966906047,11.0107067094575));
#431=CARTESIAN_POINT('',(22.746910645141,-9.342525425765,11.0019849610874));
#432=CARTESIAN_POINT('',(22.6603826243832,-9.39677466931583,11.000027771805));
#433=CARTESIAN_POINT('',(22.5747926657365,-9.45235454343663,11.));
#434=B_SPLINE_CURVE_WITH_KNOTS('',3,(#404,#405,#406,#407,#408,#409,#410,#411,#412,#413,#414,
#415,#416,#417,#418,#419,#420,#421,#422,#423,#424,#425,#426,#427,#428,#429,#430,#431,#432,#433),
.UNSPECIFIED.,.F.,.F.,(4,2,2,2,2,2,2,2,2,2,2,2,2,2,4),(0.,0.319088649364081,0.641346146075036,
0.965553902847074,1.28832411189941,1.5774902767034,1.86686764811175,2.12940978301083,
2.39175780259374,2.77800167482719,3.1670453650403,3.48068996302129,3.79477212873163,
4.10202079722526,4.40824052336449),.UNSPECIFIED.);
#435=CARTESIAN_POINT('',(22.574792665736,-9.45235454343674,11.));
#436=VERTEX_POINT('',#435);
#437=EDGE_CURVE('E326',#399,#436,#434,.T.);
#438=ORIENTED_EDGE('',*,*,#437,.T.);
#439=CARTESIAN_POINT('',(24.440408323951,-1.27855827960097,11.));
#440=VERTEX_POINT('',#439);
#441=EDGE_CURVE('E156',#436,#440,#28,.T.);
#442=ORIENTED_EDGE('',*,*,#441,.T.);
#443=CARTESIAN_POINT('',(24.4404083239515,-1.2785582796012,11.));
#444=CARTESIAN_POINT('',(24.4946154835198,-1.36775743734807,11.000030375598));
#445=CARTESIAN_POINT('',(24.5503130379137,-1.45613341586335,11.0020766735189));
#446=CARTESIAN_POINT('',(24.6650577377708,-1.6308722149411,11.0112222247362));
#447=CARTESIAN_POINT('',(24.724116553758,-1.71722634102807,11.0183402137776));
#448=CARTESIAN_POINT('',(24.8464826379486,-1.88818152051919,11.038820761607));
#449=CARTESIAN_POINT('',(24.9098411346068,-1.97273544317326,11.0522773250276));
#450=CARTESIAN_POINT('',(25.0399138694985,-2.13745063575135,11.086761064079));
#451=CARTESIAN_POINT('',(25.1066225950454,-2.21761869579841,11.1077761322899));
#452=CARTESIAN_POINT('',(25.2474978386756,-2.37692010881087,11.1604458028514));
#453=CARTESIAN_POINT('',(25.3218707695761,-2.45568760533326,11.1926745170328));
#454=CARTESIAN_POINT('',(25.4733623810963,-2.60394608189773,11.269217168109));
#455=CARTESIAN_POINT('',(25.5504716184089,-2.67346565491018,11.3134925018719));
#456=CARTESIAN_POINT('',(25.667533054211,-2.76884633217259,11.3905180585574));
#457=CARTESIAN_POINT('',(25.7070819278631,-2.7993469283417,11.4182052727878));
#458=CARTESIAN_POINT('',(25.7861280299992,-2.85665226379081,11.4772174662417));
#459=CARTESIAN_POINT('',(25.8256252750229,-2.88345907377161,11.5085403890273));
#460=CARTESIAN_POINT('',(25.9041436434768,-2.93288330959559,11.5748423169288));
#461=CARTESIAN_POINT('',(25.9431649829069,-2.95550270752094,11.6098195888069));
#462=CARTESIAN_POINT('',(26.0202555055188,-2.99611203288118,11.6833341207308));
#463=CARTESIAN_POINT('',(26.0583248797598,-3.01410289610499,11.7218706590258));
#464=CARTESIAN_POINT('',(26.1283656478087,-3.04318036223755,11.7972787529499));
#465=CARTESIAN_POINT('',(26.1605094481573,-3.05484527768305,11.8337680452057));
#466=CARTESIAN_POINT('',(26.2233137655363,-3.074190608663,11.9090357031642));
#467=CARTESIAN_POINT('',(26.2539737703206,-3.08186965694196,11.9478148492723));
#468=CARTESIAN_POINT('',(26.3134333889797,-3.09316523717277,12.0272744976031));
#469=CARTESIAN_POINT('',(26.3422350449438,-3.09678630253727,12.0679528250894));
#470=CARTESIAN_POINT('',(26.3977426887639,-3.10002362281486,12.1508760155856));
#471=CARTESIAN_POINT('',(26.4244478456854,-3.09963829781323,12.1931214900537));
#472=CARTESIAN_POINT('',(26.4947440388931,-3.09321600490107,12.3109990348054));
#473=CARTESIAN_POINT('',(26.5359537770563,-3.08315178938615,12.3878768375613));
#474=CARTESIAN_POINT('',(26.6106431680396,-3.05222343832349,12.5432786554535));
#475=CARTESIAN_POINT('',(26.6441058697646,-3.03133593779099,12.6218058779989));
#476=CARTESIAN_POINT('',(26.7109102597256,-2.9735430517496,12.7992847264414));
#477=CARTESIAN_POINT('',(26.7419400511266,-2.93387964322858,12.8982168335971));
#478=CARTESIAN_POINT('',(26.7795657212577,-2.86566353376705,13.044286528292));
#479=CARTESIAN_POINT('',(26.7906063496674,-2.84153475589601,13.0924834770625));
#480=CARTESIAN_POINT('',(26.8099076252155,-2.79069260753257,13.1879829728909));
#481=CARTESIAN_POINT('',(26.818171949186,-2.7639827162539,13.2352866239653));
#482=CARTESIAN_POINT('',(26.825136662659,-2.73611461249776,13.282109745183));
#483=B_SPLINE_CURVE_WITH_KNOTS('',3,(#443,#444,#445,#446,#447,#448,#449,#450,#451,#452,#453,
#454,#455,#456,#457,#458,#459,#460,#461,#462,#463,#464,#465,#466,#467,#468,#469,#470,#471,#472,
#473,#474,#475,#476,#477,#478,#479,#480,#481,#482),.UNSPECIFIED.,.F.,.F.,(4,2,2,2,2,2,2,2,2,2,2,
2,2,2,2,2,2,2,2,4),(0.,0.313209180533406,0.627581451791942,0.946770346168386,1.26545021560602,
1.60369981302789,1.94087800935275,2.11199734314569,2.2830203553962,2.45396261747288,
2.62487029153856,2.77466826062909,2.9245175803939,3.07419932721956,3.22394010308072,
3.48614173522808,3.74891177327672,4.08027673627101,4.2452254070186,4.40995475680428),.UNSPECIFIED.);
#484=EDGE_CURVE('E373',#440,#401,#483,.T.);
#485=ORIENTED_EDGE('',*,*,#484,.T.);
#486=EDGE_LOOP('',(#403,#438,#442,#485));
#487=FACE_BOUND('',#486,.T.);
#488=ADVANCED_FACE('F413',(#487),#23,.T.);
#489=CARTESIAN_POINT('',(22.981457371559,14.1041446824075,13.282109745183));
#490=VERTEX_POINT('',#489);
#491=CARTESIAN_POINT('',(18.8643796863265,19.2667968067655,13.282109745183));
#492=VERTEX_POINT('',#491);
#493=EDGE_CURVE('E163',#490,#492,#84,.T.);
#494=ORIENTED_EDGE('',*,*,#493,.F.);
#495=CARTESIAN_POINT('',(22.981457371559,14.1041446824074,13.282109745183));
#496=CARTESIAN_POINT('',(22.9459601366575,14.1469104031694,13.1915305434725));
#497=CARTESIAN_POINT('',(22.9077633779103,14.1837137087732,13.0988167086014));
#498=CARTESIAN_POINT('',(22.8259747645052,14.2430405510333,12.9100927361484));
#499=CARTESIAN_POINT('',(22.7823330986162,14.2654186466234,12.8140590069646));
#500=CARTESIAN_POINT('',(22.6901012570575,14.2926655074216,12.6209607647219));
#501=CARTESIAN_POINT('',(22.6414827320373,14.2974274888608,12.5238935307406));
#502=CARTESIAN_POINT('',(22.5410777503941,14.2866327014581,12.3329550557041));
#503=CARTESIAN_POINT('',(22.4893062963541,14.2711659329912,12.2390715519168));
#504=CARTESIAN_POINT('',(22.390102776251,14.2217185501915,12.0674765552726));
#505=CARTESIAN_POINT('',(22.3427800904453,14.1898330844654,11.989098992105));
#506=CARTESIAN_POINT('',(22.2491538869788,14.1097611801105,11.8403817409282));
#507=CARTESIAN_POINT('',(22.2028511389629,14.0615628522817,11.7700479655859));
#508=CARTESIAN_POINT('',(22.1173165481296,13.9562673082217,11.6454449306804));
#509=CARTESIAN_POINT('',(22.0778271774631,13.9004098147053,11.5902907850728));
#510=CARTESIAN_POINT('',(22.0022183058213,13.7794494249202,11.48872427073));
#511=CARTESIAN_POINT('',(21.9660963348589,13.7143533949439,11.4423054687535));
#512=CARTESIAN_POINT('',(21.8815326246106,13.5446526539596,11.3379996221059));
#513=CARTESIAN_POINT('',(21.8353289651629,13.4359078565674,11.285049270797));
#514=CARTESIAN_POINT('',(21.7512878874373,13.2083598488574,11.1949523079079));
#515=CARTESIAN_POINT('',(21.7135135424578,13.089489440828,11.1579230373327));
#516=CARTESIAN_POINT('',(21.6525844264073,12.8699229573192,11.1030967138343));
#517=CARTESIAN_POINT('',(21.6280151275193,12.7701694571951,11.0829631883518));
#518=CARTESIAN_POINT('',(21.5836064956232,12.5683188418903,11.0499258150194));
#519=CARTESIAN_POINT('',(21.5637738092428,12.4662186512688,11.0370320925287));
#520=CARTESIAN_POINT('',(21.5287790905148,12.2629800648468,11.0174873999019));
#521=CARTESIAN_POINT('',(21.5135248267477,12.1618690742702,11.0107067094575));
#522=CARTESIAN_POINT('',(21.4867473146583,11.959281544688,11.0019849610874));
#523=CARTESIAN_POINT('',(21.475211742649,11.8578073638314,11.000027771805));
#524=CARTESIAN_POINT('',(21.4653013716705,11.7562369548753,11.));
#525=B_SPLINE_CURVE_WITH_KNOTS('',3,(#495,#496,#497,#498,#499,#500,#501,#502,#503,#504,#505,
#506,#507,#508,#509,#510,#511,#512,#513,#514,#515,#516,#517,#518,#519,#520,#521,#522,#523,#524),
.UNSPECIFIED.,.F.,.F.,(4,2,2,2,2,2,2,2,2,2,2,2,2,2,4),(0.,0.31908864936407,0.641346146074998,
0.965553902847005,1.28832411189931,1.57749027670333,1.86686764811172,2.12940978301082,
2.39175780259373,2.77800167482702,3.16704536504,3.48068996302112,3.7947721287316,
4.10202079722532,4.40824052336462),.UNSPECIFIED.);
#526=CARTESIAN_POINT('',(21.4653013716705,11.7562369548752,11.));
#527=VERTEX_POINT('',#526);
#528=EDGE_CURVE('E367',#490,#527,#525,.T.);
#529=ORIENTED_EDGE('',*,*,#528,.T.);
#530=CARTESIAN_POINT('',(16.237962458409,18.3111126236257,11.));
#531=VERTEX_POINT('',#530);
#532=EDGE_CURVE('E149',#527,#531,#28,.T.);
#533=ORIENTED_EDGE('',*,*,#532,.T.);
#534=CARTESIAN_POINT('',(16.237962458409,18.3111126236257,11.));
#535=CARTESIAN_POINT('',(16.3414987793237,18.2978787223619,11.000030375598));
#536=CARTESIAN_POINT('',(16.4453207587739,18.28632330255,11.0020766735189));
#537=CARTESIAN_POINT('',(16.6534792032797,18.2670864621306,11.0112222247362));
#538=CARTESIAN_POINT('',(16.7578161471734,18.259419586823,11.0183402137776));
#539=CARTESIAN_POINT('',(16.9677682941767,18.2485004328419,11.038820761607));
#540=CARTESIAN_POINT('',(17.0733785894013,18.2453175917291,11.0522773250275));
#541=CARTESIAN_POINT('',(17.2832571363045,18.2443143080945,11.086761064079));
#542=CARTESIAN_POINT('',(17.3875272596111,18.2464853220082,11.1077761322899));
#543=CARTESIAN_POINT('',(17.5999083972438,18.2573032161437,11.1604458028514));
#544=CARTESIAN_POINT('',(17.7078620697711,18.2663395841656,11.1926745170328));
#545=CARTESIAN_POINT('',(17.9182286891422,18.2923428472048,11.269217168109));
#546=CARTESIAN_POINT('',(18.0206581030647,18.3092845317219,11.3134925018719));
#547=CARTESIAN_POINT('',(18.1682163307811,18.3413379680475,11.3905180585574));
#548=CARTESIAN_POINT('',(18.2167209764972,18.3532417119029,11.4182052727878));
#549=CARTESIAN_POINT('',(18.3108085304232,18.3793131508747,11.4772174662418));
#550=CARTESIAN_POINT('',(18.3563930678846,18.3934795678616,11.5085403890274));
#551=CARTESIAN_POINT('',(18.4439898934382,18.4240521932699,11.5748423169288));
#552=CARTESIAN_POINT('',(18.4860038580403,18.4404573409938,11.609819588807));
#553=CARTESIAN_POINT('',(18.5658186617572,18.4754096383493,11.6833341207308));
#554=CARTESIAN_POINT('',(18.6036203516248,18.493956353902,11.7218706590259));
#555=CARTESIAN_POINT('',(18.6700237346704,18.5305869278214,11.7972787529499));
#556=CARTESIAN_POINT('',(18.6991850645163,18.5484450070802,11.8337680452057));
#557=CARTESIAN_POINT('',(18.7534677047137,18.5854857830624,11.9090357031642));
#558=CARTESIAN_POINT('',(18.7785876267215,18.6046689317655,11.9478148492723));
#559=CARTESIAN_POINT('',(18.8244913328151,18.6441136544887,12.027274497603));
#560=CARTESIAN_POINT('',(18.8452799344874,18.6643739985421,12.0679528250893));
#561=CARTESIAN_POINT('',(18.8824194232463,18.7057531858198,12.1508760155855));
#562=CARTESIAN_POINT('',(18.8987685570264,18.726872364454,12.1931214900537));
#563=CARTESIAN_POINT('',(18.9375763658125,18.7858363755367,12.3109990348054));
#564=CARTESIAN_POINT('',(18.9554016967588,18.8243303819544,12.3878768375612));
#565=CARTESIAN_POINT('',(18.9777890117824,18.9020084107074,12.5432786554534));
#566=CARTESIAN_POINT('',(18.982322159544,18.9411937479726,12.6218058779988));
#567=CARTESIAN_POINT('',(18.9787897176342,19.029456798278,12.7992847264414));
#568=CARTESIAN_POINT('',(18.967126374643,19.0784465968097,12.8982168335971));
#569=CARTESIAN_POINT('',(18.9372520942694,19.1503955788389,13.0442865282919));
#570=CARTESIAN_POINT('',(18.9252711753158,19.1740715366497,13.0924834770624));
#571=CARTESIAN_POINT('',(18.8975553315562,19.2208614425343,13.1879829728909));
#572=CARTESIAN_POINT('',(18.8818254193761,19.2439760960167,13.2352866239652));
#573=CARTESIAN_POINT('',(18.8643796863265,19.2667968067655,13.282109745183));
#574=B_SPLINE_CURVE_WITH_KNOTS('',3,(#534,#535,#536,#537,#538,#539,#540,#541,#542,#543,#544,
#545,#546,#547,#548,#549,#550,#551,#552,#553,#554,#555,#556,#557,#558,#559,#560,#561,#562,#563,
#564,#565,#566,#567,#568,#569,#570,#571,#572,#573),.UNSPECIFIED.,.F.,.F.,(4,2,2,2,2,2,2,2,2,2,2,
2,2,2,2,2,2,2,2,4),(0.,0.313209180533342,0.627581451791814,0.94677034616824,1.26545021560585,
1.603699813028,1.94087800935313,2.11199734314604,2.28302035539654,2.4539626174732,
2.62487029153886,2.77466826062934,2.92451758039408,3.07419932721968,3.2239401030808,
3.48614173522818,3.74891177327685,4.08027673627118,4.24522540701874,4.40995475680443),.UNSPECIFIED.);
#575=EDGE_CURVE('E389',#531,#492,#574,.T.);
#576=ORIENTED_EDGE('',*,*,#575,.T.);
#577=EDGE_LOOP('',(#494,#529,#533,#576));
#578=FACE_BOUND('',#577,.T.);
#579=ADVANCED_FACE('F403',(#578),#23,.T.);
#580=CARTESIAN_POINT('',(0.,0.,101.629158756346));
#581=DIRECTION('',(0.,1.,0.));
#582=DIRECTION('',(-1.,0.,0.));
#583=AXIS2_PLACEMENT_3D('',#580,#581,#582);
#584=SPHERICAL_SURFACE('',#583,76.6575800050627);
#585=CARTESIAN_POINT('',(0.,0.,101.629158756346));
#586=DIRECTION('',(0.,0.,1.));
#587=DIRECTION('',(0.,1.,0.));
#588=AXIS2_PLACEMENT_3D('',#585,#586,#587);
#589=SPHERICAL_SURFACE('',#588,76.6575800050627);
#590=CARTESIAN_POINT('',(0.,0.,28.8005083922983));
#591=DIRECTION('',(0.,0.,1.));
#592=DIRECTION('',(0.,1.,0.));
#593=AXIS2_PLACEMENT_3D('',#590,#591,#592);
#594=CIRCLE('',#593,23.9243026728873);
#595=CARTESIAN_POINT('',(0.,23.9243026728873,28.8005083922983));
#596=VERTEX_POINT('',#595);
#597=EDGE_CURVE('E182',#596,#596,#594,.T.);
#598=ORIENTED_EDGE('',*,*,#597,.T.);
#599=EDGE_LOOP('',(#598));
#600=FACE_BOUND('',#599,.T.);
#601=ADVANCED_FACE('F16',(#600),#589,.F.);
#602=CARTESIAN_POINT('',(-5.,0.,13.));
#603=DIRECTION('',(0.,0.,-1.));
#604=DIRECTION('',(0.,-1.,0.));
#605=AXIS2_PLACEMENT_3D('',#602,#603,#604);
#606=PLANE('',#605);
#607=CARTESIAN_POINT('',(0.,0.,13.));
#608=DIRECTION('',(0.,0.,1.));
#609=DIRECTION('',(0.,1.,0.));
#610=AXIS2_PLACEMENT_3D('',#607,#608,#609);
#611=CIRCLE('',#610,5.);
#612=CARTESIAN_POINT('',(0.,5.,13.));
#613=VERTEX_POINT('',#612);
#614=EDGE_CURVE('E232',#613,#613,#611,.T.);
#615=ORIENTED_EDGE('',*,*,#614,.F.);
#616=EDGE_LOOP('',(#615));
#617=FACE_BOUND('',#616,.T.);
#618=ADVANCED_FACE('F420',(#617),#606,.T.);
#619=CARTESIAN_POINT('',(0.,0.,30.1700591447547));
#620=DIRECTION('',(0.,0.,1.));
#621=DIRECTION('',(0.,1.,0.));
#622=AXIS2_PLACEMENT_3D('',#619,#620,#621);
#623=CYLINDRICAL_SURFACE('',#622,5.);
#624=CARTESIAN_POINT('',(0.,0.,0.));
#625=DIRECTION('',(0.,0.,1.));
#626=DIRECTION('',(0.,1.,0.));
#627=AXIS2_PLACEMENT_3D('',#624,#625,#626);
#628=CIRCLE('',#627,5.);
#629=CARTESIAN_POINT('',(0.,5.,0.));
#630=VERTEX_POINT('',#629);
#631=EDGE_CURVE('E667',#630,#630,#628,.T.);
#632=ORIENTED_EDGE('',*,*,#631,.F.);
#633=EDGE_LOOP('',(#632));
#634=FACE_BOUND('',#633,.T.);
#635=ORIENTED_EDGE('',*,*,#614,.T.);
#636=EDGE_LOOP('',(#635));
#637=FACE_BOUND('',#636,.T.);
#638=ADVANCED_FACE('F517',(#634,#637),#623,.F.);
#639=CARTESIAN_POINT('',(-12.25,0.,0.));
#640=DIRECTION('',(0.,0.,-1.));
#641=DIRECTION('',(0.,-1.,0.));
#642=AXIS2_PLACEMENT_3D('',#639,#640,#641);
#643=PLANE('',#642);
#644=ORIENTED_EDGE('',*,*,#631,.T.);
#645=EDGE_LOOP('',(#644));
#646=FACE_BOUND('',#645,.T.);
#647=CARTESIAN_POINT('',(0.,0.,0.));
#648=DIRECTION('',(0.,0.,1.));
#649=DIRECTION('',(0.,1.,0.));
#650=AXIS2_PLACEMENT_3D('',#647,#648,#649);
#651=CIRCLE('',#650,12.25);
#652=CARTESIAN_POINT('',(0.,12.25,0.));
#653=VERTEX_POINT('',#652);
#654=EDGE_CURVE('E664',#653,#653,#651,.T.);
#655=ORIENTED_EDGE('',*,*,#654,.F.);
#656=EDGE_LOOP('',(#655));
#657=FACE_BOUND('',#656,.T.);
#658=ADVANCED_FACE('F524',(#646,#657),#643,.T.);
#659=CARTESIAN_POINT('',(0.,0.,1.));
#660=DIRECTION('',(0.,0.,1.));
#661=DIRECTION('',(0.,1.,0.));
#662=AXIS2_PLACEMENT_3D('',#659,#660,#661);
#663=CONICAL_SURFACE('',#662,13.25,0.785398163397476);
#664=ORIENTED_EDGE('',*,*,#654,.T.);
#665=EDGE_LOOP('',(#664));
#666=FACE_BOUND('',#665,.T.);
#667=CARTESIAN_POINT('',(0.,0.,1.));
#668=DIRECTION('',(0.,0.,1.));
#669=DIRECTION('',(0.,1.,0.));
#670=AXIS2_PLACEMENT_3D('',#667,#668,#669);
#671=CIRCLE('',#670,13.25);
#672=CARTESIAN_POINT('',(0.,13.25,1.));
#673=VERTEX_POINT('',#672);
#674=EDGE_CURVE('E145',#673,#673,#671,.T.);
#675=ORIENTED_EDGE('',*,*,#674,.F.);
#676=EDGE_LOOP('',(#675));
#677=FACE_BOUND('',#676,.T.);
#678=ADVANCED_FACE('F532',(#666,#677),#663,.T.);
#679=CARTESIAN_POINT('',(0.,0.,30.1700591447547));
#680=DIRECTION('',(0.,0.,1.));
#681=DIRECTION('',(0.,1.,0.));
#682=AXIS2_PLACEMENT_3D('',#679,#680,#681);
#683=CYLINDRICAL_SURFACE('',#682,13.25);
#684=ORIENTED_EDGE('',*,*,#674,.T.);
#685=EDGE_LOOP('',(#684));
#686=FACE_BOUND('',#685,.T.);
#687=CARTESIAN_POINT('',(0.,0.,11.));
#688=DIRECTION('',(0.,0.,1.));
#689=DIRECTION('',(0.,1.,0.));
#690=AXIS2_PLACEMENT_3D('',#687,#688,#689);
#691=CIRCLE('',#690,13.25);
#692=CARTESIAN_POINT('',(0.,13.25,11.));
#693=VERTEX_POINT('',#692);
#694=EDGE_CURVE('E141',#693,#693,#691,.T.);
#695=ORIENTED_EDGE('',*,*,#694,.F.);
#696=EDGE_LOOP('',(#695));
#697=FACE_BOUND('',#696,.T.);
#698=ADVANCED_FACE('F409',(#686,#697),#683,.T.);
#699=CARTESIAN_POINT('',(-13.25,0.,11.));
#700=DIRECTION('',(0.,0.,1.));
#701=DIRECTION('',(0.,1.,0.));
#702=AXIS2_PLACEMENT_3D('',#699,#700,#701);
#703=PLANE('',#702);
#704=ORIENTED_EDGE('',*,*,#168,.F.);
#705=CARTESIAN_POINT('',(-42.5181882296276,9.70449900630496,11.));
#706=DIRECTION('',(0.,0.,-1.));
#707=DIRECTION('',(0.781831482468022,-0.623489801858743,0.));
#708=AXIS2_PLACEMENT_3D('',#705,#706,#707);
#709=CIRCLE('',#708,21.1526280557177);
#710=EDGE_CURVE('E122',#32,#163,#709,.T.);
#711=ORIENTED_EDGE('',*,*,#710,.F.);
#712=ORIENTED_EDGE('',*,*,#33,.F.);
#713=CARTESIAN_POINT('',(-18.9223739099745,39.2927142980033,11.));
#714=DIRECTION('',(0.,0.,-1.));
#715=DIRECTION('',(0.,-1.,0.));
#716=AXIS2_PLACEMENT_3D('',#713,#714,#715);
#717=CIRCLE('',#716,21.1526280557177);
#718=CARTESIAN_POINT('',(-4.19200033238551,24.1121422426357,11.));
#719=VERTEX_POINT('',#718);
#720=EDGE_CURVE('E395',#719,#30,#717,.T.);
#721=ORIENTED_EDGE('',*,*,#720,.F.);
#722=CARTESIAN_POINT('',(4.19200033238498,24.1121422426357,11.));
#723=VERTEX_POINT('',#722);
#724=EDGE_CURVE('E143',#723,#719,#28,.T.);
#725=ORIENTED_EDGE('',*,*,#724,.F.);
#726=CARTESIAN_POINT('',(18.922373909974,39.2927142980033,11.));
#727=DIRECTION('',(0.,0.,-1.));
#728=DIRECTION('',(-0.781831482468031,-0.623489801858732,0.));
#729=AXIS2_PLACEMENT_3D('',#726,#727,#728);
#730=CIRCLE('',#729,21.1526280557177);
#731=EDGE_CURVE('E381',#531,#723,#730,.T.);
#732=ORIENTED_EDGE('',*,*,#731,.F.);
#733=ORIENTED_EDGE('',*,*,#532,.F.);
#734=CARTESIAN_POINT('',(42.5181882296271,9.70449900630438,11.));
#735=DIRECTION('',(0.,0.,-1.));
#736=DIRECTION('',(-0.974927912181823,0.222520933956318,0.));
#737=AXIS2_PLACEMENT_3D('',#734,#735,#736);
#738=CIRCLE('',#737,21.1526280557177);
#739=EDGE_CURVE('E374',#440,#527,#738,.T.);
#740=ORIENTED_EDGE('',*,*,#739,.F.);
#741=ORIENTED_EDGE('',*,*,#441,.F.);
#742=CARTESIAN_POINT('',(34.096939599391,-27.1914019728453,11.));
#743=DIRECTION('',(0.,0.,-1.));
#744=DIRECTION('',(-0.433883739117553,0.900968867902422,0.));
#745=AXIS2_PLACEMENT_3D('',#742,#743,#744);
#746=CIRCLE('',#745,21.1526280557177);
#747=EDGE_CURVE('E324',#349,#436,#746,.T.);
#748=ORIENTED_EDGE('',*,*,#747,.F.);
#749=ORIENTED_EDGE('',*,*,#350,.F.);
#750=CARTESIAN_POINT('',(-4.9960036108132E-13,-43.6116226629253,11.));
#751=DIRECTION('',(0.,0.,-1.));
#752=DIRECTION('',(0.433883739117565,0.900968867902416,0.));
#753=AXIS2_PLACEMENT_3D('',#750,#751,#752);
#754=CIRCLE('',#753,21.1526280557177);
#755=EDGE_CURVE('E308',#258,#345,#754,.T.);
#756=ORIENTED_EDGE('',*,*,#755,.F.);
#757=ORIENTED_EDGE('',*,*,#259,.F.);
#758=CARTESIAN_POINT('',(-34.0969395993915,-27.1914019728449,11.));
#759=DIRECTION('',(0.,0.,-1.));
#760=DIRECTION('',(0.974927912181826,0.222520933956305,0.));
#761=AXIS2_PLACEMENT_3D('',#758,#759,#760);
#762=CIRCLE('',#761,21.1526280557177);
#763=EDGE_CURVE('E127',#167,#254,#762,.T.);
#764=ORIENTED_EDGE('',*,*,#763,.F.);
#765=EDGE_LOOP('',(#704,#711,#712,#721,#725,#732,#733,#740,#741,#748,#749,#756,#757,#764));
#766=FACE_BOUND('',#765,.T.);
#767=ORIENTED_EDGE('',*,*,#694,.T.);
#768=EDGE_LOOP('',(#767));
#769=FACE_BOUND('',#768,.T.);
#770=ADVANCED_FACE('F132',(#766,#769),#703,.F.);
#771=CARTESIAN_POINT('',(3.30163995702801,26.7614172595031,13.282109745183));
#772=VERTEX_POINT('',#771);
#773=CARTESIAN_POINT('',(-3.30163995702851,26.7614172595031,13.282109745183));
#774=VERTEX_POINT('',#773);
#775=EDGE_CURVE('E158',#772,#774,#84,.T.);
#776=ORIENTED_EDGE('',*,*,#775,.F.);
#777=CARTESIAN_POINT('',(3.30163995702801,26.7614172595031,13.282109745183));
#778=CARTESIAN_POINT('',(3.24607220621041,26.7603283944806,13.1915305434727));
#779=CARTESIAN_POINT('',(3.19348293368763,26.7534114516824,13.0988167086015));
#780=CARTESIAN_POINT('',(3.09610497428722,26.7264562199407,12.9100927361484));
#781=CARTESIAN_POINT('',(3.0513989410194,26.7062883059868,12.8140590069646));
#782=CARTESIAN_POINT('',(2.97259087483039,26.6511666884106,12.6209607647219));
#783=CARTESIAN_POINT('',(2.9385546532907,26.6161242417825,12.5238935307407));
#784=CARTESIAN_POINT('',(2.88439287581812,26.5308940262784,12.3329550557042));
#785=CARTESIAN_POINT('',(2.86420630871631,26.4807741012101,12.2390715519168));
#786=CARTESIAN_POINT('',(2.84101344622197,26.3723837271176,12.0674765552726));
#787=CARTESIAN_POINT('',(2.83643729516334,26.3155050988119,11.9890989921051));
#788=CARTESIAN_POINT('',(2.84066504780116,26.1923811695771,11.8403817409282));
#789=CARTESIAN_POINT('',(2.84947872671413,26.1261290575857,11.7700479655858));
#790=CARTESIAN_POINT('',(2.8784721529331,25.9936047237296,11.6454449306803));
#791=CARTESIAN_POINT('',(2.89752208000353,25.9279041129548,11.5902907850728));
#792=CARTESIAN_POINT('',(2.94495136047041,25.7933731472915,11.4887242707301));
#793=CARTESIAN_POINT('',(2.97332380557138,25.7245451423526,11.4423054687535));
#794=CARTESIAN_POINT('',(3.05327657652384,25.5526238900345,11.3379996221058));
#795=CARTESIAN_POINT('',(3.10948917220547,25.4486991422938,11.285049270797));
#796=CARTESIAN_POINT('',(3.23499461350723,25.241119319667,11.1949523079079));
#797=CARTESIAN_POINT('',(3.30437932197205,25.1374716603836,11.1579230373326));
#798=CARTESIAN_POINT('',(3.4380546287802,24.9529378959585,11.1030967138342));
#799=CARTESIAN_POINT('',(3.50072634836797,24.8715335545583,11.0829631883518));
#800=CARTESIAN_POINT('',(3.63085118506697,24.7109616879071,11.0499258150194));
#801=CARTESIAN_POINT('',(3.69831085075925,24.6317974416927,11.0370320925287));
#802=CARTESIAN_POINT('',(3.83539032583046,24.4777202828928,11.0174873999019));
#803=CARTESIAN_POINT('',(3.90493120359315,24.4027523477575,11.0107067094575));
#804=CARTESIAN_POINT('',(4.04662500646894,24.2555055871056,11.0019849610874));
#805=CARTESIAN_POINT('',(4.11876840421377,24.1832185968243,11.000027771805));
#806=CARTESIAN_POINT('',(4.19200033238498,24.1121422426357,11.));
#807=B_SPLINE_CURVE_WITH_KNOTS('',3,(#777,#778,#779,#780,#781,#782,#783,#784,#785,#786,#787,
#788,#789,#790,#791,#792,#793,#794,#795,#796,#797,#798,#799,#800,#801,#802,#803,#804,#805,#806),
.UNSPECIFIED.,.F.,.F.,(4,2,2,2,2,2,2,2,2,2,2,2,2,2,4),(0.,0.319088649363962,0.64134614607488,
0.965553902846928,1.28832411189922,1.57749027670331,1.86686764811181,2.12940978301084,
2.39175780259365,2.77800167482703,3.16704536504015,3.48068996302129,3.79477212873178,
4.10202079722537,4.40824052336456),.UNSPECIFIED.);
#808=EDGE_CURVE('E383',#772,#723,#807,.T.);
#809=ORIENTED_EDGE('',*,*,#808,.T.);
#810=ORIENTED_EDGE('',*,*,#724,.T.);
#811=CARTESIAN_POINT('',(-4.19200033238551,24.1121422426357,11.));
#812=CARTESIAN_POINT('',(-4.11709981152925,24.1848389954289,11.000030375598));
#813=CARTESIAN_POINT('',(-4.04333347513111,24.2588056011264,11.0020766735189));
#814=CARTESIAN_POINT('',(-3.89850884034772,24.4095564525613,11.0112222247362));
#815=CARTESIAN_POINT('',(-3.82746161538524,24.4863501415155,11.0183402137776));
#816=CARTESIAN_POINT('',(-3.68802165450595,24.6436893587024,11.0388207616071));
#817=CARTESIAN_POINT('',(-3.61968626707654,24.724274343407,11.0522773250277));
#818=CARTESIAN_POINT('',(-3.48804473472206,24.887738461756,11.0867610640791));
#819=CARTESIAN_POINT('',(-3.4247307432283,24.9706137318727,11.1077761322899));
#820=CARTESIAN_POINT('',(-3.30077104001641,25.1434048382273,11.1604458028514));
#821=CARTESIAN_POINT('',(-3.24052794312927,25.2334405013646,11.1926745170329));
#822=CARTESIAN_POINT('',(-3.12969667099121,25.4141245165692,11.2692171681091));
#823=CARTESIAN_POINT('',(-3.07907851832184,25.5047700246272,11.313492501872));
#824=CARTESIAN_POINT('',(-3.01213785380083,25.6401206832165,11.3905180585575));
#825=CARTESIAN_POINT('',(-2.99120242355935,25.6854650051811,11.4182052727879));
#826=CARTESIAN_POINT('',(-2.95292326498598,25.7752808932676,11.4772174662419));
#827=CARTESIAN_POINT('',(-2.9355775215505,25.8197529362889,11.5085403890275));
#828=CARTESIAN_POINT('',(-2.90486443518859,25.9073006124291,11.574842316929));
#829=CARTESIAN_POINT('',(-2.89149521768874,25.9503768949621,11.6098195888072));
#830=CARTESIAN_POINT('',(-2.86905830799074,26.0345710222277,11.6833341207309));
#831=CARTESIAN_POINT('',(-2.85998974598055,26.0756892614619,11.7218706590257));
#832=CARTESIAN_POINT('',(-2.84722684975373,26.1504443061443,11.7972787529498));
#833=CARTESIAN_POINT('',(-2.84300706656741,26.184377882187,11.8337680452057));
#834=CARTESIAN_POINT('',(-2.83812203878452,26.2499123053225,11.9090357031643));
#835=CARTESIAN_POINT('',(-2.837458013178,26.2815123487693,11.9478148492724));
#836=CARTESIAN_POINT('',(-2.83967664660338,26.3419946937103,12.0272744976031));
#837=CARTESIAN_POINT('',(-2.84255534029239,26.3708799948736,12.0679528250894));
#838=CARTESIAN_POINT('',(-2.85175079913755,26.425716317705,12.1508760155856));
#839=CARTESIAN_POINT('',(-2.85806891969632,26.4516661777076,12.1931214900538));
#840=CARTESIAN_POINT('',(-2.87997256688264,26.518770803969,12.3109990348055));
#841=CARTESIAN_POINT('',(-2.89895448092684,26.556707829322,12.3878768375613));
#842=CARTESIAN_POINT('',(-2.94572734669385,26.6226423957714,12.5432786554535));
#843=CARTESIAN_POINT('',(-2.97353730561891,26.6506182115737,12.6218058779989));
#844=CARTESIAN_POINT('',(-3.04474657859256,26.702887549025,12.7992847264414));
#845=CARTESIAN_POINT('',(-3.09032032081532,26.724313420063,12.898216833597));
#846=CARTESIAN_POINT('',(-3.16519860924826,26.7458162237,13.0442865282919));
#847=CARTESIAN_POINT('',(-3.19117919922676,26.7512108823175,13.0924834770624));
#848=CARTESIAN_POINT('',(-3.24504156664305,26.758714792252,13.1879829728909));
#849=CARTESIAN_POINT('',(-3.27292077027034,26.7608284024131,13.2352866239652));
#850=CARTESIAN_POINT('',(-3.30163995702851,26.7614172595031,13.282109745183));
#851=B_SPLINE_CURVE_WITH_KNOTS('',3,(#811,#812,#813,#814,#815,#816,#817,#818,#819,#820,#821,
#822,#823,#824,#825,#826,#827,#828,#829,#830,#831,#832,#833,#834,#835,#836,#837,#838,#839,#840,
#841,#842,#843,#844,#845,#846,#847,#848,#849,#850),.UNSPECIFIED.,.F.,.F.,(4,2,2,2,2,2,2,2,2,2,2,
2,2,2,2,2,2,2,2,4),(0.,0.313209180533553,0.627581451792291,0.946770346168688,1.26545021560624,
1.60369981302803,1.9408780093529,2.11199734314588,2.28302035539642,2.45396261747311,
2.62487029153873,2.77466826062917,2.92451758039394,3.07419932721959,3.22394010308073,
3.48614173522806,3.74891177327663,4.0802767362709,4.24522540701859,4.40995475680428),.UNSPECIFIED.);
#852=EDGE_CURVE('E185',#719,#774,#851,.T.);
#853=ORIENTED_EDGE('',*,*,#852,.T.);
#854=EDGE_LOOP('',(#776,#809,#810,#853));
#855=FACE_BOUND('',#854,.T.);
#856=ADVANCED_FACE('F198',(#855),#23,.T.);
#857=CARTESIAN_POINT('',(0.,0.,25.119995));
#858=DIRECTION('',(0.,0.,1.));
#859=DIRECTION('',(0.,1.,0.));
#860=AXIS2_PLACEMENT_3D('',#857,#858,#859);
#861=CONICAL_SURFACE('',#860,28.,0.0872668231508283);
#862=CARTESIAN_POINT('',(-26.8251366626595,-2.73611461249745,13.2821097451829));
#863=CARTESIAN_POINT('',(-26.8505732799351,-2.63425454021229,13.4532141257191));
#864=CARTESIAN_POINT('',(-26.8754397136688,-2.53188163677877,13.6240984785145));
#865=CARTESIAN_POINT('',(-26.9240309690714,-2.32596818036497,13.9655815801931));
#866=CARTESIAN_POINT('',(-26.9477545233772,-2.22242648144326,14.1361798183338));
#867=CARTESIAN_POINT('',(-26.9940220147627,-2.01417082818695,14.4770104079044));
#868=CARTESIAN_POINT('',(-27.016564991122,-1.90945600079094,14.6472423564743));
#869=CARTESIAN_POINT('',(-27.0604320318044,-1.69884315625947,14.9872560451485));
#870=CARTESIAN_POINT('',(-27.0817554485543,-1.59294454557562,15.1570375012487));
#871=CARTESIAN_POINT('',(-27.1231430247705,-1.37994704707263,15.4960622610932));
#872=CARTESIAN_POINT('',(-27.1432068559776,-1.27284785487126,15.6653054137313));
#873=CARTESIAN_POINT('',(-27.1830261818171,-1.05191481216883,16.0118008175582));
#874=CARTESIAN_POINT('',(-27.2027134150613,-0.938016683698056,16.1890199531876));
#875=CARTESIAN_POINT('',(-27.2405989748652,-0.708822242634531,16.5426492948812));
#876=CARTESIAN_POINT('',(-27.2587976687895,-0.593526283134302,16.7190596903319));
#877=CARTESIAN_POINT('',(-27.2936508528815,-0.361476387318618,17.070948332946));
#878=CARTESIAN_POINT('',(-27.3103060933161,-0.244723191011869,17.246426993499));
#879=CARTESIAN_POINT('',(-27.3420115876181,-0.00967775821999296,17.5963153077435));
#880=CARTESIAN_POINT('',(-27.3570629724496,0.108613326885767,17.7707256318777));
#881=CARTESIAN_POINT('',(-27.3854924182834,0.346843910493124,18.1183224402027));
#882=CARTESIAN_POINT('',(-27.3988719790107,0.46678182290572,18.2915098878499));
#883=CARTESIAN_POINT('',(-27.4238501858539,0.708175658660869,18.6360852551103));
#884=CARTESIAN_POINT('',(-27.4354546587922,0.829625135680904,18.8074772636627));
#885=CARTESIAN_POINT('',(-27.4568390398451,1.07465268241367,19.1488531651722));
#886=CARTESIAN_POINT('',(-27.4666189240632,1.19823077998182,19.318837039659));
#887=CARTESIAN_POINT('',(-27.4842432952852,1.44793396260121,19.6573232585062));
#888=CARTESIAN_POINT('',(-27.4920855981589,1.57406175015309,19.8258237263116));
#889=CARTESIAN_POINT('',(-27.5056827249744,1.82939736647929,20.161186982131));
#890=CARTESIAN_POINT('',(-27.5114326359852,1.95861169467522,20.3280450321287));
#891=CARTESIAN_POINT('',(-27.5206337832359,2.22082342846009,20.6598449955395));
#892=CARTESIAN_POINT('',(-27.5240763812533,2.35383312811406,20.8247774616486));
#893=CARTESIAN_POINT('',(-27.5283008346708,2.62072301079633,21.1475667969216));
#894=CARTESIAN_POINT('',(-27.5291428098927,2.75451072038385,21.3054989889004));
#895=CARTESIAN_POINT('',(-27.5279718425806,3.02682820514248,21.617239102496));
#896=CARTESIAN_POINT('',(-27.5259587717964,3.16535819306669,21.7710468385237));
#897=CARTESIAN_POINT('',(-27.5185651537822,3.44798840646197,22.0725078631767));
#898=CARTESIAN_POINT('',(-27.5131956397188,3.59206893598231,22.2201796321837));
#899=CARTESIAN_POINT('',(-27.5020387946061,3.81369406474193,22.4351377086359));
#900=CARTESIAN_POINT('',(-27.4978166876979,3.88829933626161,22.5055362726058));
#901=CARTESIAN_POINT('',(-27.4882008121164,4.03975111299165,22.6437891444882));
#902=CARTESIAN_POINT('',(-27.4828072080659,4.11659730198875,22.7116438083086));
#903=CARTESIAN_POINT('',(-27.47069170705,4.27270240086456,22.8440275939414));
#904=CARTESIAN_POINT('',(-27.4639729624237,4.3519552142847,22.9085641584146));
#905=CARTESIAN_POINT('',(-27.4489868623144,4.51342048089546,23.0336070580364));
#906=CARTESIAN_POINT('',(-27.4407200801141,4.59563182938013,23.0941148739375));
#907=CARTESIAN_POINT('',(-27.4245556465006,4.74347597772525,23.1961554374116));
#908=CARTESIAN_POINT('',(-27.417038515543,4.8083969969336,23.2387765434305));
#909=CARTESIAN_POINT('',(-27.4008081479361,4.9404200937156,23.3203478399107));
#910=CARTESIAN_POINT('',(-27.3920943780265,5.00752313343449,23.3592963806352));
#911=CARTESIAN_POINT('',(-27.3733493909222,5.14381784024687,23.4325619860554));
#912=CARTESIAN_POINT('',(-27.363321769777,5.21300342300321,23.4668911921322));
#913=CARTESIAN_POINT('',(-27.3417843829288,5.35363304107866,23.5300330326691));
#914=CARTESIAN_POINT('',(-27.3302750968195,5.42507633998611,23.5588474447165));
#915=CARTESIAN_POINT('',(-27.3084883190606,5.55335072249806,23.6039774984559));
#916=CARTESIAN_POINT('',(-27.2985367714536,5.60976139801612,23.6216434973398));
#917=CARTESIAN_POINT('',(-27.2776543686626,5.72361302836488,23.6525345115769));
#918=CARTESIAN_POINT('',(-27.266723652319,5.78105383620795,23.6657601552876));
#919=CARTESIAN_POINT('',(-27.2438891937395,5.89664609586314,23.6873163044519));
#920=CARTESIAN_POINT('',(-27.23198575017,5.95479732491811,23.6956483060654));
#921=CARTESIAN_POINT('',(-27.2072486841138,6.07142011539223,23.7071016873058));
#922=CARTESIAN_POINT('',(-27.1944150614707,6.12989167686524,23.7102230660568));
#923=CARTESIAN_POINT('',(-27.1678719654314,6.2468346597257,23.7111271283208));
#924=CARTESIAN_POINT('',(-27.1541603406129,6.30530570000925,23.7088961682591));
#925=CARTESIAN_POINT('',(-27.1260122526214,6.42162568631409,23.6991603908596));
#926=CARTESIAN_POINT('',(-27.11157578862,6.47947463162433,23.6916555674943));
#927=CARTESIAN_POINT('',(-27.0821076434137,6.59416969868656,23.6716633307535));
#928=CARTESIAN_POINT('',(-27.0670757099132,6.65101538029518,23.6591737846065));
#929=CARTESIAN_POINT('',(-27.0365513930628,6.7633943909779,23.6296492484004));
#930=CARTESIAN_POINT('',(-27.0210588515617,6.81892725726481,23.6126126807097));
#931=CARTESIAN_POINT('',(-26.9824586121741,6.95392386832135,23.5656541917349));
#932=CARTESIAN_POINT('',(-26.9591544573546,7.03252944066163,23.5334220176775));
#933=CARTESIAN_POINT('',(-26.9120921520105,7.18632419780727,23.4619189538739));
#934=CARTESIAN_POINT('',(-26.8883337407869,7.26151133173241,23.4226439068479));
#935=CARTESIAN_POINT('',(-26.840465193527,7.40882799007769,23.3383431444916));
#936=CARTESIAN_POINT('',(-26.816354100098,7.48094555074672,23.2932972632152));
#937=CARTESIAN_POINT('',(-26.767978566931,7.62208536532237,23.1987460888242));
#938=CARTESIAN_POINT('',(-26.7437141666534,7.69110838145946,23.1492419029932));
#939=CARTESIAN_POINT('',(-26.6946793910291,7.8275258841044,23.0458202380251));
#940=CARTESIAN_POINT('',(-26.6699073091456,7.89487423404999,22.9918430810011));
#941=CARTESIAN_POINT('',(-26.6202839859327,8.02706316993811,22.880924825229));
#942=CARTESIAN_POINT('',(-26.5954327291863,8.09190323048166,22.8239831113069));
#943=CARTESIAN_POINT('',(-26.5206970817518,8.28333263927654,22.6493843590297));
#944=CARTESIAN_POINT('',(-26.4707134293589,8.40660376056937,22.52813180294));
#945=CARTESIAN_POINT('',(-26.3704455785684,8.64633942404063,22.2790375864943));
#946=CARTESIAN_POINT('',(-26.3201611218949,8.76279676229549,22.1511892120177));
#947=CARTESIAN_POINT('',(-26.2190375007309,8.99073905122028,21.8901995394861));
#948=CARTESIAN_POINT('',(-26.1681968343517,9.10219762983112,21.7570359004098));
#949=CARTESIAN_POINT('',(-26.0662094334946,9.32043272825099,21.4873746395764));
#950=CARTESIAN_POINT('',(-26.0150631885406,9.42721520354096,21.3508816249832));
#951=CARTESIAN_POINT('',(-25.9123657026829,9.63696812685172,21.0752314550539));
#952=CARTESIAN_POINT('',(-25.8608145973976,9.73993979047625,20.9360751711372));
#953=CARTESIAN_POINT('',(-25.7548096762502,9.94744534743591,20.6489933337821));
#954=CARTESIAN_POINT('',(-25.7003336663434,10.0518237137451,20.5009638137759));
#955=CARTESIAN_POINT('',(-25.5908445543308,10.257525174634,20.2029896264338));
#956=CARTESIAN_POINT('',(-25.5358314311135,10.3588481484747,20.0530448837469));
#957=CARTESIAN_POINT('',(-25.3699100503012,10.6588697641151,19.6007413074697));
#958=CARTESIAN_POINT('',(-25.2581588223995,10.8535451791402,19.2960194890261));
#959=CARTESIAN_POINT('',(-25.0328196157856,11.2333204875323,18.6834059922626));
#960=CARTESIAN_POINT('',(-24.9192418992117,11.4184587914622,18.3755341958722));
#961=CARTESIAN_POINT('',(-24.6897659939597,11.7812783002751,17.7563558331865));
#962=CARTESIAN_POINT('',(-24.5738681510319,11.9589606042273,17.4450497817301));
#963=CARTESIAN_POINT('',(-24.3386455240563,12.3093875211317,16.8166629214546));
#964=CARTESIAN_POINT('',(-24.2192986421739,12.4820691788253,16.4995553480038));
#965=CARTESIAN_POINT('',(-23.9782877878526,12.8213203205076,15.8629372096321));
#966=CARTESIAN_POINT('',(-23.8566236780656,12.9878894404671,15.5434265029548));
#967=CARTESIAN_POINT('',(-23.6106424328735,13.3158894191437,14.9013020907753));
#968=CARTESIAN_POINT('',(-23.4863178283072,13.4773013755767,14.5786816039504));
#969=CARTESIAN_POINT('',(-23.2354988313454,13.7947044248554,13.9316703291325));
#970=CARTESIAN_POINT('',(-23.1090046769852,13.9506961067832,13.6072797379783));
#971=CARTESIAN_POINT('',(-22.981457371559,14.1041446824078,13.2821097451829));
#972=B_SPLINE_CURVE_WITH_KNOTS('',3,(#862,#863,#864,#865,#866,#867,#868,#869,#870,#871,#872,
#873,#874,#875,#876,#877,#878,#879,#880,#881,#882,#883,#884,#885,#886,#887,#888,#889,#890,#891,
#892,#893,#894,#895,#896,#897,#898,#899,#900,#901,#902,#903,#904,#905,#906,#907,#908,#909,#910,
#911,#912,#913,#914,#915,#916,#917,#918,#919,#920,#921,#922,#923,#924,#925,#926,#927,#928,#929,
#930,#931,#932,#933,#934,#935,#936,#937,#938,#939,#940,#941,#942,#943,#944,#945,#946,#947,#948,
#949,#950,#951,#952,#953,#954,#955,#956,#957,#958,#959,#960,#961,#962,#963,#964,#965,#966,#967,
#968,#969,#970,#971),.UNSPECIFIED.,.F.,.F.,(4,2,2,2,2,2,2,2,2,2,2,2,2,2,2,2,2,2,2,2,2,2,2,2,2,2,
2,2,2,2,2,2,2,2,2,2,2,2,2,2,2,2,2,2,2,2,2,2,2,2,2,2,2,2,4),(0.,0.602238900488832,
1.20513094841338,1.80850622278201,2.41219896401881,3.01604838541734,3.65078381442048,
4.28536211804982,4.9196303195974,5.55344826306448,6.18669348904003,6.81781325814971,
7.44894129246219,8.08077755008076,8.71408792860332,9.34975627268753,9.97061520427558,
10.59150202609,11.2103585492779,11.5182997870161,11.8261977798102,12.1333719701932,
12.4404326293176,12.6744033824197,12.9084787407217,13.1419263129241,13.375298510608,
13.5549712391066,13.7346185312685,13.9142108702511,14.0938032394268,14.2738538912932,
14.4539047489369,14.6340327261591,14.8142232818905,15.078062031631,15.3420570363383,
15.6070010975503,15.8718795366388,16.1411605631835,16.4104976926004,16.9500709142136,
17.4902046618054,18.0329152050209,18.5749131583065,19.1167367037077,19.6841250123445,
20.2515357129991,21.3867660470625,22.5169945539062,23.6470558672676,24.7878543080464,
25.9287205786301,27.0733758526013,28.2179063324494),.UNSPECIFIED.);
#973=EDGE_CURVE('E9',#126,#77,#972,.T.);
#974=ORIENTED_EDGE('',*,*,#973,.F.);
#975=ORIENTED_EDGE('',*,*,#129,.T.);
#976=CARTESIAN_POINT('',(-14.586018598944,-22.6786759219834,13.282109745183));
#977=CARTESIAN_POINT('',(-14.681515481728,-22.6350543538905,13.4532141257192));
#978=CARTESIAN_POINT('',(-14.7770578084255,-22.5906672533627,13.6240984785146));
#979=CARTESIAN_POINT('',(-14.9683435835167,-22.5002724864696,13.9655815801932));
#980=CARTESIAN_POINT('',(-15.0640871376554,-22.4542631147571,14.1361798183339));
#981=CARTESIAN_POINT('',(-15.2557552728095,-22.3605912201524,14.4770104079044));
#982=CARTESIAN_POINT('',(-15.3516799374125,-22.3129274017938,14.6472423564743));
#983=CARTESIAN_POINT('',(-15.5436943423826,-22.2159090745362,14.9872560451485));
#984=CARTESIAN_POINT('',(-15.6397841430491,-22.1665536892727,15.1570375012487));
#985=CARTESIAN_POINT('',(-15.8321170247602,-22.0661100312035,15.4960622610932));
#986=CARTESIAN_POINT('',(-15.928360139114,-22.0150213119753,15.6653054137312));
#987=CARTESIAN_POINT('',(-16.1259194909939,-21.9084038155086,16.0118008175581));
#988=CARTESIAN_POINT('',(-16.2272434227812,-21.8527815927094,16.1890199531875));
#989=CARTESIAN_POINT('',(-16.4300561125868,-21.7395013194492,16.5426492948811));
#990=CARTESIAN_POINT('',(-16.5315448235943,-21.681843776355,16.7190596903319));
#991=CARTESIAN_POINT('',(-16.7346993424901,-21.564412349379,17.0709483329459));
#992=CARTESIAN_POINT('',(-16.8363650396,-21.5046395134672,17.2464269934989));
#993=CARTESIAN_POINT('',(-17.0398990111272,-21.3828794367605,17.5963153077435));
#994=CARTESIAN_POINT('',(-17.1417670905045,-21.3208937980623,17.7707256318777));
#995=CARTESIAN_POINT('',(-17.3457487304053,-21.1945864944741,18.1183224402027));
#996=CARTESIAN_POINT('',(-17.4478619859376,-21.1302669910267,18.2915098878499));
#997=CARTESIAN_POINT('',(-17.6521649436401,-20.9992891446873,18.6360852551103));
#998=CARTESIAN_POINT('',(-17.7543532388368,-20.932639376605,18.8074772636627));
#999=CARTESIAN_POINT('',(-17.9592564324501,-20.7965861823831,19.1488531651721));
#1000=CARTESIAN_POINT('',(-18.0619713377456,-20.7271827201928,19.3188370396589));
#1001=CARTESIAN_POINT('',(-18.268185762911,-20.585274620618,19.6573232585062));
#1002=CARTESIAN_POINT('',(-18.371686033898,-20.5127665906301,19.8258237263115));
#1003=CARTESIAN_POINT('',(-18.5797931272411,-20.3641980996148,20.1611869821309));
#1004=CARTESIAN_POINT('',(-18.6844019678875,-20.2881297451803,20.3280450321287));
#1005=CARTESIAN_POINT('',(-18.8951441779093,-20.1318371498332,20.6598449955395));
#1006=CARTESIAN_POINT('',(-19.0012817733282,-20.0515984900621,20.8247774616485));
#1007=CARTESIAN_POINT('',(-19.2125785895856,-19.8884981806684,21.1475667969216));
#1008=CARTESIAN_POINT('',(-19.3177029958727,-19.8057411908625,21.3054989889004));
#1009=CARTESIAN_POINT('',(-19.5298792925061,-19.6350385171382,21.617239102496));
#1010=CARTESIAN_POINT('',(-19.6369312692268,-19.5470926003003,21.7710468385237));
#1011=CARTESIAN_POINT('',(-19.8532906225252,-19.3650949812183,22.0725078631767));
#1012=CARTESIAN_POINT('',(-19.9625894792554,-19.2710641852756,22.2201796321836));
#1013=CARTESIAN_POINT('',(-20.128906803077,-19.1241604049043,22.4351377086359));
#1014=CARTESIAN_POINT('',(-20.1846031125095,-19.0743438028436,22.5055362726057));
#1015=CARTESIAN_POINT('',(-20.2970174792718,-18.972397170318,22.6437891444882));
#1016=CARTESIAN_POINT('',(-20.3537353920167,-18.9202674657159,22.7116438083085));
#1017=CARTESIAN_POINT('',(-20.4682293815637,-18.8134652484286,22.8440275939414));
#1018=CARTESIAN_POINT('',(-20.526002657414,-18.7587990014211,22.9085641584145));
#1019=CARTESIAN_POINT('',(-20.6428976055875,-18.64641044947,23.0336070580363));
#1020=CARTESIAN_POINT('',(-20.7020187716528,-18.5886892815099,23.0941148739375));
#1021=CARTESIAN_POINT('',(-20.8075296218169,-18.483872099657,23.1961554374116));
#1022=CARTESIAN_POINT('',(-20.8536000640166,-18.4375173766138,23.2387765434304));
#1023=CARTESIAN_POINT('',(-20.9467004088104,-18.3425129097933,23.3203478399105));
#1024=CARTESIAN_POINT('',(-20.9937307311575,-18.2938621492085,23.3592963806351));
#1025=CARTESIAN_POINT('',(-21.0886029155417,-18.194228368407,23.4325619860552));
#1026=CARTESIAN_POINT('',(-21.1364422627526,-18.1432519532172,23.466891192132));
#1027=CARTESIAN_POINT('',(-21.2329625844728,-18.0387322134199,23.5300330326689));
#1028=CARTESIAN_POINT('',(-21.2816432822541,-17.9851897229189,23.5588474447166));
#1029=CARTESIAN_POINT('',(-21.368348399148,-17.8881783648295,23.6039774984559));
#1030=CARTESIAN_POINT('',(-21.4062473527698,-17.8452264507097,23.6216434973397));
#1031=CARTESIAN_POINT('',(-21.4822401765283,-17.7579146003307,23.6525345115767));
#1032=CARTESIAN_POINT('',(-21.5203340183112,-17.7135548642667,23.6657601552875));
#1033=CARTESIAN_POINT('',(-21.5964706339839,-17.6236315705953,23.6873163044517));
#1034=CARTESIAN_POINT('',(-21.6345134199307,-17.5780683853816,23.6956483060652));
#1035=CARTESIAN_POINT('',(-21.7102694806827,-17.4860150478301,23.7071016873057));
#1036=CARTESIAN_POINT('',(-21.7479827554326,-17.4395248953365,23.7102230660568));
#1037=CARTESIAN_POINT('',(-21.8228631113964,-17.3458599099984,23.7111271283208));
#1038=CARTESIAN_POINT('',(-21.8600285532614,-17.2986836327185,23.7088961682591));
#1039=CARTESIAN_POINT('',(-21.9334211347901,-17.204152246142,23.6991603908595));
#1040=CARTESIAN_POINT('',(-21.9696482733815,-17.156797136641,23.6916555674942));
#1041=CARTESIAN_POINT('',(-22.0409473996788,-17.062246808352,23.6716633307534));
#1042=CARTESIAN_POINT('',(-22.076018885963,-17.0150516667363,23.6591737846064));
#1043=CARTESIAN_POINT('',(-22.1448487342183,-16.9211196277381,23.6296492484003));
#1044=CARTESIAN_POINT('',(-22.1786066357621,-16.8743828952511,23.6126126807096));
#1045=CARTESIAN_POINT('',(-22.260084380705,-16.7600350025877,23.5656541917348));
#1046=CARTESIAN_POINT('',(-22.3070107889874,-16.6928053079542,23.5334220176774));
#1047=CARTESIAN_POINT('',(-22.3979095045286,-16.5601210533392,23.4619189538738));
#1048=CARTESIAN_POINT('',(-22.4418800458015,-16.4946675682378,23.4226439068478));
#1049=CARTESIAN_POINT('',(-22.5272112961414,-16.3653919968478,23.3383431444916));
#1050=CARTESIAN_POINT('',(-22.5685620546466,-16.3015766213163,23.2932972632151));
#1051=CARTESIAN_POINT('',(-22.6487479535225,-16.175755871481,23.1987460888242));
#1052=CARTESIAN_POINT('',(-22.687583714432,-16.1137500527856,23.1492419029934));
#1053=CARTESIAN_POINT('',(-22.7636665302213,-15.9903581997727,23.0458202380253));
#1054=CARTESIAN_POINT('',(-22.8008764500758,-15.9289995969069,22.9918430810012));
#1055=CARTESIAN_POINT('',(-22.8732862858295,-15.8077840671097,22.8809248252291));
#1056=CARTESIAN_POINT('',(-22.9084857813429,-15.7479274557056,22.823983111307));
#1057=CARTESIAN_POINT('',(-23.0115544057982,-15.5701424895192,22.6493843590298));
#1058=CARTESIAN_POINT('',(-23.0767673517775,-15.45420540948,22.5281318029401));
#1059=CARTESIAN_POINT('',(-23.2016842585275,-15.2263401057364,22.2790375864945));
#1060=CARTESIAN_POINT('',(-23.2613824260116,-15.1144161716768,22.1511892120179));
#1061=CARTESIAN_POINT('',(-23.3765453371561,-14.8932348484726,21.8901995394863));
#1062=CARTESIAN_POINT('',(-23.431988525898,-14.7839927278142,21.75703590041));
#1063=CARTESIAN_POINT('',(-23.5390234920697,-14.5681884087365,21.4873746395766));
#1064=CARTESIAN_POINT('',(-23.5906202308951,-14.461622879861,21.3508816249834));
#1065=CARTESIAN_POINT('',(-23.6905808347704,-14.2505519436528,21.0752314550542));
#1066=CARTESIAN_POINT('',(-23.7389457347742,-14.1460458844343,20.9360751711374));
#1067=CARTESIAN_POINT('',(-23.83508712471,-13.9337903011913,20.6489933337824));
#1068=CARTESIAN_POINT('',(-23.8827281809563,-13.8261203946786,20.5009638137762));
#1069=CARTESIAN_POINT('',(-23.9752867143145,-13.612265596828,20.202989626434));
#1070=CARTESIAN_POINT('',(-24.020204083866,-13.5060807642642,20.0530448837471));
#1071=CARTESIAN_POINT('',(-24.1513201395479,-13.1892977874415,19.6007413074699));
#1072=CARTESIAN_POINT('',(-24.2338477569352,-12.9805490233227,19.2960194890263));
#1073=CARTESIAN_POINT('',(-24.3902713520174,-12.5675857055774,18.6834059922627));
#1074=CARTESIAN_POINT('',(-24.4642037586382,-12.3633552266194,18.3755341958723));
#1075=CARTESIAN_POINT('',(-24.604791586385,-11.9577294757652,17.7563558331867));
#1076=CARTESIAN_POINT('',(-24.6714480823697,-11.7563337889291,17.4450497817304));
#1077=CARTESIAN_POINT('',(-24.7987639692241,-11.3539417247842,16.8166629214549));
#1078=CARTESIAN_POINT('',(-24.8593603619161,-11.1529673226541,16.499555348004));
#1079=CARTESIAN_POINT('',(-24.9743297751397,-10.7530178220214,15.8629372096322));
#1080=CARTESIAN_POINT('',(-25.0287024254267,-10.5540428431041,15.5434265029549));
#1081=CARTESIAN_POINT('',(-25.1317763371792,-10.1572223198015,14.9013020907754));
#1082=CARTESIAN_POINT('',(-25.180458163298,-9.95938272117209,14.5786816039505));
#1083=CARTESIAN_POINT('',(-25.2722307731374,-9.56538696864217,13.9316703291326));
#1084=CARTESIAN_POINT('',(-25.3153221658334,-9.36923063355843,13.6072797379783));
#1085=CARTESIAN_POINT('',(-25.355768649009,-9.17383651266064,13.2821097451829));
#1086=B_SPLINE_CURVE_WITH_KNOTS('',3,(#976,#977,#978,#979,#980,#981,#982,#983,#984,#985,#986,
#987,#988,#989,#990,#991,#992,#993,#994,#995,#996,#997,#998,#999,#1000,#1001,#1002,#1003,#1004,
#1005,#1006,#1007,#1008,#1009,#1010,#1011,#1012,#1013,#1014,#1015,#1016,#1017,#1018,#1019,#1020,
#1021,#1022,#1023,#1024,#1025,#1026,#1027,#1028,#1029,#1030,#1031,#1032,#1033,#1034,#1035,#1036,
#1037,#1038,#1039,#1040,#1041,#1042,#1043,#1044,#1045,#1046,#1047,#1048,#1049,#1050,#1051,#1052,
#1053,#1054,#1055,#1056,#1057,#1058,#1059,#1060,#1061,#1062,#1063,#1064,#1065,#1066,#1067,#1068,
#1069,#1070,#1071,#1072,#1073,#1074,#1075,#1076,#1077,#1078,#1079,#1080,#1081,#1082,#1083,#1084,
#1085),.UNSPECIFIED.,.F.,.F.,(4,2,2,2,2,2,2,2,2,2,2,2,2,2,2,2,2,2,2,2,2,2,2,2,2,2,2,2,2,2,2,2,2,
2,2,2,2,2,2,2,2,2,2,2,2,2,2,2,2,2,2,2,2,2,4),(0.,0.602238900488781,1.20513094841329,
1.80850622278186,2.41219896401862,3.01604838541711,3.65078381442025,4.2853621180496,
4.91963031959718,5.55344826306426,6.1866934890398,6.81781325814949,7.44894129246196,
8.08077755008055,8.71408792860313,9.34975627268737,9.97061520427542,10.5915020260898,
11.2103585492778,11.5182997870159,11.82619777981,12.133371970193,12.4404326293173,
12.6744033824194,12.9084787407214,13.1419263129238,13.3752985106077,13.5549712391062,
13.7346185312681,13.9142108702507,14.0938032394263,14.2738538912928,14.4539047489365,
14.6340327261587,14.8142232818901,15.0780620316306,15.3420570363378,15.6070010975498,
15.8718795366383,16.1411605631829,16.4104976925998,16.9500709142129,17.4902046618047,
18.0329152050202,18.5749131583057,19.116736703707,19.6841250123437,20.2515357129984,
21.3867660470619,22.5169945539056,23.647055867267,24.7878543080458,25.9287205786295,
27.0733758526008,28.2179063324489),.UNSPECIFIED.);
#1087=EDGE_CURVE('E28',#217,#128,#1086,.T.);
#1088=ORIENTED_EDGE('',*,*,#1087,.F.);
#1089=ORIENTED_EDGE('',*,*,#220,.T.);
#1090=CARTESIAN_POINT('',(8.636668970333,-25.5437317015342,13.282109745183));
#1091=CARTESIAN_POINT('',(8.54302292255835,-25.5911965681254,13.4532141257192));
#1092=CARTESIAN_POINT('',(8.44875002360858,-25.6382196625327,13.6240984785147));
#1093=CARTESIAN_POINT('',(8.25881181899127,-25.731412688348,13.9655815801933));
#1094=CARTESIAN_POINT('',(8.16314511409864,-25.7775816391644,14.136179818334));
#1095=CARTESIAN_POINT('',(7.97040635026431,-25.869030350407,14.4770104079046));
#1096=CARTESIAN_POINT('',(7.87333322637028,-25.9143093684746,14.6472423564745));
#1097=CARTESIAN_POINT('',(7.6777622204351,-26.003942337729,14.9872560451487));
#1098=CARTESIAN_POINT('',(7.57926361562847,-26.0482957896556,15.1570375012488));
#1099=CARTESIAN_POINT('',(7.38081601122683,-26.1360420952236,15.4960622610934));
#1100=CARTESIAN_POINT('',(7.28086664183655,-26.1794346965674,15.6653054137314));
#1101=CARTESIAN_POINT('',(7.074333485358,-26.2674178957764,16.0118008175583));
#1102=CARTESIAN_POINT('',(6.96767184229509,-26.311956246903,16.1890199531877));
#1103=CARTESIAN_POINT('',(6.75265411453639,-26.3998924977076,16.5426492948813));
#1104=CARTESIAN_POINT('',(6.64429845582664,-26.443290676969,16.719059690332));
#1105=CARTESIAN_POINT('',(6.42582209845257,-26.5289059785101,17.070948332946));
#1106=CARTESIAN_POINT('',(6.31570228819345,-26.5711236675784,17.246426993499));
#1107=CARTESIAN_POINT('',(6.09360507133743,-26.65433676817,17.5963153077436));
#1108=CARTESIAN_POINT('',(5.98162903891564,-26.6953330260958,17.7707256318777));
#1109=CARTESIAN_POINT('',(5.75569754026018,-26.7760609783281,18.1183224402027));
#1110=CARTESIAN_POINT('',(5.64174395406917,-26.8157937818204,18.2915098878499));
#1111=CARTESIAN_POINT('',(5.41196053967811,-26.8938609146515,18.6360852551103));
#1112=CARTESIAN_POINT('',(5.29613829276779,-26.9321994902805,18.8074772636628));
#1113=CARTESIAN_POINT('',(5.06201257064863,-27.007571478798,19.1488531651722));
#1114=CARTESIAN_POINT('',(4.94370906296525,-27.0446048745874,19.3188370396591));
#1115=CARTESIAN_POINT('',(4.70418825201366,-27.1173515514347,19.6573232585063));
#1116=CARTESIAN_POINT('',(4.58296782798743,-27.153063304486,19.8258237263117));
#1117=CARTESIAN_POINT('',(4.33705965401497,-27.2231370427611,20.1611869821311));
#1118=CARTESIAN_POINT('',(4.21236447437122,-27.2574956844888,20.3280450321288));
#1119=CARTESIAN_POINT('',(3.95877438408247,-27.3248137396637,20.6598449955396));
#1120=CARTESIAN_POINT('',(3.82986556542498,-27.3577674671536,20.8247774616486));
#1121=CARTESIAN_POINT('',(3.57060719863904,-27.4212745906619,21.1475667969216));
#1122=CARTESIAN_POINT('',(3.44036118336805,-27.4518660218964,21.3054989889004));
#1123=CARTESIAN_POINT('',(3.17461070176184,-27.5113207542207,21.617239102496));
#1124=CARTESIAN_POINT('',(3.03910599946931,-27.5401839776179,21.7710468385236));
#1125=CARTESIAN_POINT('',(2.76191668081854,-27.5958668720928,22.0725078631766));
#1126=CARTESIAN_POINT('',(2.62025372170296,-27.6226929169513,22.2201796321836));
#1127=CARTESIAN_POINT('',(2.40170256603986,-27.6611320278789,22.4351377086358));
#1128=CARTESIAN_POINT('',(2.32802829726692,-27.6736170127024,22.5055362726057));
#1129=CARTESIAN_POINT('',(2.17823399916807,-27.6979434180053,22.6437891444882));
#1130=CARTESIAN_POINT('',(2.10211431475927,-27.7097849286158,22.7116438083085));
#1131=CARTESIAN_POINT('',(1.94722714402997,-27.7327098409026,22.8440275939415));
#1132=CARTESIAN_POINT('',(1.8684663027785,-27.7437949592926,22.9085641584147));
#1133=CARTESIAN_POINT('',(1.70771458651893,-27.7651139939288,23.0336070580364));
#1134=CARTESIAN_POINT('',(1.62572491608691,-27.7753482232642,23.0941148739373));
#1135=CARTESIAN_POINT('',(1.47799060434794,-27.7924874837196,23.1961554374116));
#1136=CARTESIAN_POINT('',(1.41302457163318,-27.7996051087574,23.2387765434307));
#1137=CARTESIAN_POINT('',(1.28069997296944,-27.8131595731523,23.3203478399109));
#1138=CARTESIAN_POINT('',(1.21334035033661,-27.8195961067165,23.3592963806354));
#1139=CARTESIAN_POINT('',(1.0762916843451,-27.8316495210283,23.4325619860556));
#1140=CARTESIAN_POINT('',(1.0066093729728,-27.8372685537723,23.4668911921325));
#1141=CARTESIAN_POINT('',(0.864713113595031,-27.8475641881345,23.5300330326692));
#1142=CARTESIAN_POINT('',(0.792499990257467,-27.8522410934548,23.5588474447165));
#1143=CARTESIAN_POINT('',(0.662593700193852,-27.8595442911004,23.603977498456));
#1144=CARTESIAN_POINT('',(0.605382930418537,-27.8623948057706,23.6216434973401));
#1145=CARTESIAN_POINT('',(0.489739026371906,-27.867370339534,23.6525345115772));
#1146=CARTESIAN_POINT('',(0.431306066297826,-27.8694954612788,23.6657601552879));
#1147=CARTESIAN_POINT('',(0.313530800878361,-27.8729552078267,23.6873163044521));
#1148=CARTESIAN_POINT('',(0.254188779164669,-27.8742900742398,23.6956483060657));
#1149=CARTESIAN_POINT('',(0.134985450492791,-27.876124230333,23.707101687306));
#1150=CARTESIAN_POINT('',(0.075124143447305,-27.8766235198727,23.7102230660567));
#1151=CARTESIAN_POINT('',(-0.04479322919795,-27.8767681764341,23.7111271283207));
#1152=CARTESIAN_POINT('',(-0.104849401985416,-27.8764113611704,23.7088961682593));
#1153=CARTESIAN_POINT('',(-0.224516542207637,-27.8748526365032,23.69916039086));
#1154=CARTESIAN_POINT('',(-0.284127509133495,-27.8736507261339,23.6916555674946));
#1155=CARTESIAN_POINT('',(-0.402504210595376,-27.870443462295,23.6716633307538));
#1156=CARTESIAN_POINT('',(-0.461269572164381,-27.8684377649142,23.6591737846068));
#1157=CARTESIAN_POINT('',(-0.577623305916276,-27.8636854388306,23.6296492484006));
#1158=CARTESIAN_POINT('',(-0.635211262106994,-27.8609385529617,23.6126126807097));
#1159=CARTESIAN_POINT('',(-0.775412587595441,-27.8533456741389,23.5656541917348));
#1160=CARTESIAN_POINT('',(-0.857233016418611,-27.8481171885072,23.5334220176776));
#1161=CARTESIAN_POINT('',(-1.01764416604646,-27.8364573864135,23.4619189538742));
#1162=CARTESIAN_POINT('',(-1.09623294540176,-27.8300253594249,23.4226439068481));
#1163=CARTESIAN_POINT('',(-1.25050782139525,-27.8161380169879,23.3383431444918));
#1164=CARTESIAN_POINT('',(-1.32618246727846,-27.8086791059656,23.2932972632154));
#1165=CARTESIAN_POINT('',(-1.47454818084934,-27.7929230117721,23.1987460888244));
#1166=CARTESIAN_POINT('',(-1.54723998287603,-27.7846260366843,23.1492419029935));
#1167=CARTESIAN_POINT('',(-1.69114847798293,-27.7671764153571,23.0458202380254));
#1168=CARTESIAN_POINT('',(-1.76232057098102,-27.7580118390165,22.9918430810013));
#1169=CARTESIAN_POINT('',(-1.90223748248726,-27.7390474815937,22.8809248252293));
#1170=CARTESIAN_POINT('',(-1.9709817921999,-27.7292475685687,22.8239831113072));
#1171=CARTESIAN_POINT('',(-2.17424191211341,-27.6989827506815,22.6493843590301));
#1172=CARTESIAN_POINT('',(-2.30554477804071,-27.6776826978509,22.5281318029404));
#1173=CARTESIAN_POINT('',(-2.56158146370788,-27.633274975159,22.2790375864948));
#1174=CARTESIAN_POINT('',(-2.68630831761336,-27.6101654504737,22.1511892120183));
#1175=CARTESIAN_POINT('',(-2.93103774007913,-27.5622991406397,21.8901995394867));
#1176=CARTESIAN_POINT('',(-3.05101493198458,-27.5375350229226,21.7570359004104));
#1177=CARTESIAN_POINT('',(-3.28647275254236,-27.4866665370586,21.4873746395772));
#1178=CARTESIAN_POINT('',(-3.40195907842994,-27.4605639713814,21.350881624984));
#1179=CARTESIAN_POINT('',(-3.6293053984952,-27.4071157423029,21.0752314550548));
#1180=CARTESIAN_POINT('',(-3.74116654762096,-27.3797704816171,20.9360751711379));
#1181=CARTESIAN_POINT('',(-3.96705782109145,-27.3225976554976,20.6489933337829));
#1182=CARTESIAN_POINT('',(-4.08094125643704,-27.2927138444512,20.5009638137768));
#1183=CARTESIAN_POINT('',(-4.30584897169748,-27.2317427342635,20.2029896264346));
#1184=CARTESIAN_POINT('',(-4.41687313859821,-27.2006553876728,20.0530448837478));
#1185=CARTESIAN_POINT('',(-4.74629356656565,-27.1056550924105,19.6007413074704));
#1186=CARTESIAN_POINT('',(-4.96095505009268,-27.0400250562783,19.2960194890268));
#1187=CARTESIAN_POINT('',(-5.38135128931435,-26.9048435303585,18.6834059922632));
#1188=CARTESIAN_POINT('',(-5.58712120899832,-26.8353105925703,18.3755341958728));
#1189=CARTESIAN_POINT('',(-5.99190726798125,-26.6923230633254,17.756355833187));
#1190=CARTESIAN_POINT('',(-6.1909244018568,-26.6188690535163,17.4450497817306));
#1191=CARTESIAN_POINT('',(-6.584907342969,-26.4675212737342,16.8166629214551));
#1192=CARTESIAN_POINT('',(-6.77981669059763,-26.3895919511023,16.4995553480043));
#1193=CARTESIAN_POINT('',(-7.16419205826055,-26.2301142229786,15.8629372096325));
#1194=CARTESIAN_POINT('',(-7.35365775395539,-26.1485656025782,15.5434265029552));
#1195=CARTESIAN_POINT('',(-7.72817006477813,-25.9817384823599,14.9013020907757));
#1196=CARTESIAN_POINT('',(-7.91319991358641,-25.8964484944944,14.5786816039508));
#1197=CARTESIAN_POINT('',(-8.27845748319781,-25.722546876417,13.9316703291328));
#1198=CARTESIAN_POINT('',(-8.45868572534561,-25.6339356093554,13.6072797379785));
#1199=CARTESIAN_POINT('',(-8.63666897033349,-25.5437317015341,13.282109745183));
#1200=B_SPLINE_CURVE_WITH_KNOTS('',3,(#1090,#1091,#1092,#1093,#1094,#1095,#1096,#1097,#1098,
#1099,#1100,#1101,#1102,#1103,#1104,#1105,#1106,#1107,#1108,#1109,#1110,#1111,#1112,#1113,#1114,
#1115,#1116,#1117,#1118,#1119,#1120,#1121,#1122,#1123,#1124,#1125,#1126,#1127,#1128,#1129,#1130,
#1131,#1132,#1133,#1134,#1135,#1136,#1137,#1138,#1139,#1140,#1141,#1142,#1143,#1144,#1145,#1146,
#1147,#1148,#1149,#1150,#1151,#1152,#1153,#1154,#1155,#1156,#1157,#1158,#1159,#1160,#1161,#1162,
#1163,#1164,#1165,#1166,#1167,#1168,#1169,#1170,#1171,#1172,#1173,#1174,#1175,#1176,#1177,#1178,
#1179,#1180,#1181,#1182,#1183,#1184,#1185,#1186,#1187,#1188,#1189,#1190,#1191,#1192,#1193,#1194,
#1195,#1196,#1197,#1198,#1199),.UNSPECIFIED.,.F.,.F.,(4,2,2,2,2,2,2,2,2,2,2,2,2,2,2,2,2,2,2,2,2,
2,2,2,2,2,2,2,2,2,2,2,2,2,2,2,2,2,2,2,2,2,2,2,2,2,2,2,2,2,2,2,2,2,4),(0.,0.602238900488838,
1.20513094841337,1.80850622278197,2.41219896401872,3.0160483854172,3.6507838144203,
4.28536211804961,4.91963031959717,5.55344826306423,6.1866934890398,6.81781325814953,
7.44894129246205,8.08077755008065,8.71408792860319,9.34975627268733,9.97061520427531,
10.5915020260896,11.2103585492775,11.5182997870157,11.8261977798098,12.133371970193,
12.4404326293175,12.6744033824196,12.9084787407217,13.1419263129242,13.3752985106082,
13.5549712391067,13.7346185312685,13.9142108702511,14.0938032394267,14.2738538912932,
14.453904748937,14.6340327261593,14.8142232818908,15.0780620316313,15.3420570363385,
15.6070010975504,15.8718795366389,16.1411605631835,16.4104976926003,16.9500709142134,
17.490204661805,18.0329152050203,18.5749131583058,19.1167367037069,19.6841250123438,
20.2515357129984,21.386766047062,22.5169945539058,23.6470558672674,24.7878543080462,
25.92872057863,27.0733758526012,28.2179063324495),.UNSPECIFIED.);
#1201=EDGE_CURVE('E264',#308,#219,#1200,.T.);
#1202=ORIENTED_EDGE('',*,*,#1201,.F.);
#1203=ORIENTED_EDGE('',*,*,#311,.T.);
#1204=CARTESIAN_POINT('',(25.3557686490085,-9.17383651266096,13.282109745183));
#1205=CARTESIAN_POINT('',(25.3344908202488,-9.27664580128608,13.4532141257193));
#1206=CARTESIAN_POINT('',(25.3124767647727,-9.37966974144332,13.6240984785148));
#1207=CARTESIAN_POINT('',(25.2669134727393,-9.58627431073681,13.9655815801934));
#1208=CARTESIAN_POINT('',(25.243362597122,-9.68985542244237,14.1361798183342));
#1209=CARTESIAN_POINT('',(25.1946894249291,-9.89756199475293,14.4770104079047));
#1210=CARTESIAN_POINT('',(25.1695658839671,-10.0016878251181,14.6472423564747));
#1211=CARTESIAN_POINT('',(25.1177072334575,-10.2104766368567,14.9872560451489));
#1212=CARTESIAN_POINT('',(25.0909712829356,-10.3151398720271,15.157037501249));
#1213=CARTESIAN_POINT('',(25.0358440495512,-10.5250013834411,15.4960622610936));
#1214=CARTESIAN_POINT('',(25.0074523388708,-10.6301997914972,15.6653054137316));
#1215=CARTESIAN_POINT('',(24.9474690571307,-10.8465305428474,16.0118008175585));
#1216=CARTESIAN_POINT('',(24.9157880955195,-10.9576911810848,16.1890199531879));
#1217=CARTESIAN_POINT('',(24.8504780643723,-11.1806261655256,16.5426492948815));
#1218=CARTESIAN_POINT('',(24.8168494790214,-11.2924003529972,16.7190596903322));
#1219=CARTESIAN_POINT('',(24.7475684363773,-11.5165923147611,17.0709483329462));
#1220=CARTESIAN_POINT('',(24.7119169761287,-11.6290097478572,17.2464269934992));
#1221=CARTESIAN_POINT('',(24.6385002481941,-11.8545348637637,17.5963153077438));
#1222=CARTESIAN_POINT('',(24.6007364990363,-11.967641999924,17.770725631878));
#1223=CARTESIAN_POINT('',(24.5229861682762,-12.1946154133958,18.1183224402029));
#1224=CARTESIAN_POINT('',(24.4830016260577,-12.3084809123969,18.29150988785));
#1225=CARTESIAN_POINT('',(24.4007693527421,-12.5368068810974,18.6360852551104));
#1226=CARTESIAN_POINT('',(24.358529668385,-12.6512640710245,18.807477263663));
#1227=CARTESIAN_POINT('',(24.2714828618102,-12.8813045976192,19.1488531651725));
#1228=CARTESIAN_POINT('',(24.2266757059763,-12.9968879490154,19.3188370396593));
#1229=CARTESIAN_POINT('',(24.1342125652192,-13.229509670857,19.6573232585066));
#1230=CARTESIAN_POINT('',(24.0865534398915,-13.3465495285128,19.8258237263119));
#1231=CARTESIAN_POINT('',(23.9880180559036,-13.5824985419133,20.1611869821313));
#1232=CARTESIAN_POINT('',(23.9371345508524,-13.7014114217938,20.3280450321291));
#1233=CARTESIAN_POINT('',(23.8316550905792,-13.9416482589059,20.6598449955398));
#1234=CARTESIAN_POINT('',(23.7770460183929,-14.0629795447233,20.8247774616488));
#1235=CARTESIAN_POINT('',(23.6650529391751,-14.3052719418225,21.1475667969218));
#1236=CARTESIAN_POINT('',(23.6077632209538,-14.4261758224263,21.3054989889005));
#1237=CARTESIAN_POINT('',(23.4885540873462,-14.6710173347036,21.6172391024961));
#1238=CARTESIAN_POINT('',(23.4266344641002,-14.7949551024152,21.7710468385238));
#1239=CARTESIAN_POINT('',(23.2973443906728,-15.0463881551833,22.0725078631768));
#1240=CARTESIAN_POINT('',(23.2299924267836,-15.1738704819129,22.2201796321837));
#1241=CARTESIAN_POINT('',(23.1237809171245,-15.3687070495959,22.435137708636));
#1242=CARTESIAN_POINT('',(23.0876069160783,-15.4340921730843,22.5055362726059));
#1243=CARTESIAN_POINT('',(23.0132308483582,-15.5663733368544,22.6437891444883));
#1244=CARTESIAN_POINT('',(22.9750290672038,-15.633269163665,22.7116438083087));
#1245=CARTESIAN_POINT('',(22.896381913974,-15.7686582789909,22.8440275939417));
#1246=CARTESIAN_POINT('',(22.8559420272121,-15.8371474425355,22.9085641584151));
#1247=CARTESIAN_POINT('',(22.7723828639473,-15.9761203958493,23.0336070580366));
#1248=CARTESIAN_POINT('',(22.7292645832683,-16.0466034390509,23.0941148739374));
#1249=CARTESIAN_POINT('',(22.6505537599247,-16.1727929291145,23.1961554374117));
#1250=CARTESIAN_POINT('',(22.6156128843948,-16.2280231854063,23.238776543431));
#1251=CARTESIAN_POINT('',(22.5437071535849,-16.3399297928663,23.3203478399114));
#1252=CARTESIAN_POINT('',(22.5067414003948,-16.3966067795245,23.3592963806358));
#1253=CARTESIAN_POINT('',(22.4307166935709,-16.5112709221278,23.432561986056));
#1254=CARTESIAN_POINT('',(22.3916636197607,-16.569254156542,23.466891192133));
#1255=CARTESIAN_POINT('',(22.3112422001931,-16.6866123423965,23.5300330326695));
#1256=CARTESIAN_POINT('',(22.2698746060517,-16.7459868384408,23.5588474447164));
#1257=CARTESIAN_POINT('',(22.1945892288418,-16.8521051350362,23.603977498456));
#1258=CARTESIAN_POINT('',(22.1611475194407,-16.8986115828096,23.6216434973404));
#1259=CARTESIAN_POINT('',(22.0929347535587,-16.992127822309,23.6525345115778));
#1260=CARTESIAN_POINT('',(22.0581638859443,-17.0391375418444,23.6657601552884));
#1261=CARTESIAN_POINT('',(21.9874371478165,-17.1333750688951,23.6873163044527));
#1262=CARTESIAN_POINT('',(21.951481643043,-17.1806028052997,23.6956483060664));
#1263=CARTESIAN_POINT('',(21.8785935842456,-17.2749432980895,23.7071016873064));
#1264=CARTESIAN_POINT('',(21.8416610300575,-17.3220560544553,23.7102230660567));
#1265=CARTESIAN_POINT('',(21.7670068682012,-17.4159014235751,23.7111271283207));
#1266=CARTESIAN_POINT('',(21.7292834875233,-17.4626327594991,23.7088961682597));
#1267=CARTESIAN_POINT('',(21.65345358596,-17.555220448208,23.6991603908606));
#1268=CARTESIAN_POINT('',(21.6153470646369,-17.6010767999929,23.6916555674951));
#1269=CARTESIAN_POINT('',(21.5390328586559,-17.691627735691,23.6716633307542));
#1270=CARTESIAN_POINT('',(21.5008251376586,-17.7363218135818,23.6591737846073));
#1271=CARTESIAN_POINT('',(21.4245642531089,-17.8243277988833,23.6296492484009));
#1272=CARTESIAN_POINT('',(21.3865111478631,-17.8676392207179,23.6126126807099));
#1273=CARTESIAN_POINT('',(21.2931606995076,-17.9725189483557,23.5656541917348));
#1274=CARTESIAN_POINT('',(21.2380587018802,-18.0332288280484,23.5334220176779));
#1275=CARTESIAN_POINT('',(21.1289279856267,-18.1513735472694,23.4619189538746));
#1276=CARTESIAN_POINT('',(21.0748999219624,-18.2088064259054,23.4226439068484));
#1277=CARTESIAN_POINT('',(20.9678535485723,-18.3207647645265,23.3383431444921));
#1278=CARTESIAN_POINT('',(20.9148395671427,-18.3752790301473,23.2932972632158));
#1279=CARTESIAN_POINT('',(20.8100164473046,-18.481452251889,23.1987460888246));
#1280=CARTESIAN_POINT('',(20.7582070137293,-18.533111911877,23.1492419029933));
#1281=CARTESIAN_POINT('',(20.6548388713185,-18.6347444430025,23.0458202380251));
#1282=CARTESIAN_POINT('',(20.6032986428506,-18.684675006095,22.9918430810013));
#1283=CARTESIAN_POINT('',(20.5012349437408,-18.7822423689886,22.8809248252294));
#1284=CARTESIAN_POINT('',(20.4507116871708,-18.8298786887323,22.8239831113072));
#1285=CARTESIAN_POINT('',(20.3003190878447,-18.9699240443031,22.6493843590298));
#1286=CARTESIAN_POINT('',(20.2018000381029,-19.0593003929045,22.5281318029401));
#1287=CARTESIAN_POINT('',(20.0074444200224,-19.2317901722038,22.2790375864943));
#1288=CARTESIAN_POINT('',(19.9116107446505,-19.3148970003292,22.1511892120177));
#1289=CARTESIAN_POINT('',(19.7216010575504,-19.4763900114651,21.890199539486));
#1290=CARTESIAN_POINT('',(19.627435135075,-19.5547517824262,21.7570359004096));
#1291=CARTESIAN_POINT('',(19.4408590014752,-19.7071241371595,21.4873746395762));
#1292=CARTESIAN_POINT('',(19.3484466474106,-19.781140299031,21.3508816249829));
#1293=CARTESIAN_POINT('',(19.1649110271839,-19.9255623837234,21.0752314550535));
#1294=CARTESIAN_POINT('',(19.0737873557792,-19.995969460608,20.9360751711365));
#1295=CARTESIAN_POINT('',(18.8882469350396,-20.1369316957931,20.6489933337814));
#1296=CARTESIAN_POINT('',(18.7938776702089,-20.2073370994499,20.5009638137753));
#1297=CARTESIAN_POINT('',(18.6059808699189,-20.3451621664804,20.2029896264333));
#1298=CARTESIAN_POINT('',(18.5124533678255,-20.412581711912,20.0530448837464));
#1299=CARTESIAN_POINT('',(18.2327888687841,-20.6109012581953,19.6007413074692));
#1300=CARTESIAN_POINT('',(18.0476379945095,-20.7378107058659,19.2960194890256));
#1301=CARTESIAN_POINT('',(17.679836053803,-20.9822054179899,18.6834059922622));
#1302=CARTESIAN_POINT('',(17.4971775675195,-21.0997297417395,18.3755341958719));
#1303=CARTESIAN_POINT('',(17.1330054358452,-21.3270529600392,17.7563558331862));
#1304=CARTESIAN_POINT('',(16.9514916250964,-21.4368529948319,17.4450497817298));
#1305=CARTESIAN_POINT('',(16.5875188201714,-21.6505174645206,16.8166629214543));
#1306=CARTESIAN_POINT('',(16.405067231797,-21.7543155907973,16.4995553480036));
#1307=CARTESIAN_POINT('',(16.0407284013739,-21.9553996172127,15.862937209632));
#1308=CARTESIAN_POINT('',(15.8588411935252,-22.0526851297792,15.5434265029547));
#1309=CARTESIAN_POINT('',(15.4949058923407,-22.2414756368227,14.9013020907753));
#1310=CARTESIAN_POINT('',(15.3128592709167,-22.3329603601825,14.5786816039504));
#1311=CARTESIAN_POINT('',(14.9491631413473,-22.5101043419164,13.9316703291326));
#1312=CARTESIAN_POINT('',(14.7675135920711,-22.5957642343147,13.6072797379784));
#1313=CARTESIAN_POINT('',(14.586018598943,-22.6786759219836,13.282109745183));
#1314=B_SPLINE_CURVE_WITH_KNOTS('',3,(#1204,#1205,#1206,#1207,#1208,#1209,#1210,#1211,#1212,
#1213,#1214,#1215,#1216,#1217,#1218,#1219,#1220,#1221,#1222,#1223,#1224,#1225,#1226,#1227,#1228,
#1229,#1230,#1231,#1232,#1233,#1234,#1235,#1236,#1237,#1238,#1239,#1240,#1241,#1242,#1243,#1244,
#1245,#1246,#1247,#1248,#1249,#1250,#1251,#1252,#1253,#1254,#1255,#1256,#1257,#1258,#1259,#1260,
#1261,#1262,#1263,#1264,#1265,#1266,#1267,#1268,#1269,#1270,#1271,#1272,#1273,#1274,#1275,#1276,
#1277,#1278,#1279,#1280,#1281,#1282,#1283,#1284,#1285,#1286,#1287,#1288,#1289,#1290,#1291,#1292,
#1293,#1294,#1295,#1296,#1297,#1298,#1299,#1300,#1301,#1302,#1303,#1304,#1305,#1306,#1307,#1308,
#1309,#1310,#1311,#1312,#1313),.UNSPECIFIED.,.F.,.F.,(4,2,2,2,2,2,2,2,2,2,2,2,2,2,2,2,2,2,2,2,2,
2,2,2,2,2,2,2,2,2,2,2,2,2,2,2,2,2,2,2,2,2,2,2,2,2,2,2,2,2,2,2,2,2,4),(0.,0.602238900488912,
1.2051309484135,1.80850622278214,2.41219896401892,3.01604838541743,3.65078381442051,
4.2853621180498,4.91963031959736,5.55344826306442,6.18669348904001,6.81781325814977,
7.44894129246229,8.08077755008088,8.71408792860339,9.34975627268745,9.97061520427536,
10.5915020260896,11.2103585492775,11.5182997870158,11.8261977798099,12.1333719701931,
12.4404326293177,12.6744033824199,12.9084787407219,13.1419263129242,13.3752985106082,
13.5549712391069,13.7346185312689,13.9142108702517,14.0938032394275,14.2738538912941,
14.4539047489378,14.63403272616,14.8142232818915,15.078062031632,15.3420570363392,
15.6070010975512,15.8718795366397,16.1411605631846,16.4104976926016,16.950070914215,
17.4902046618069,18.0329152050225,18.5749131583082,19.1167367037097,19.6841250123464,
20.2515357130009,21.3867660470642,22.5169945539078,23.6470558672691,24.7878543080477,
25.9287205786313,27.0733758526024,28.2179063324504),.UNSPECIFIED.);
#1315=EDGE_CURVE('E257',#399,#310,#1314,.T.);
#1316=ORIENTED_EDGE('',*,*,#1315,.F.);
#1317=ORIENTED_EDGE('',*,*,#402,.T.);
#1318=CARTESIAN_POINT('',(22.981457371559,14.1041446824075,13.282109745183));
#1319=CARTESIAN_POINT('',(23.048570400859,14.0234084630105,13.4532141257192));
#1320=CARTESIAN_POINT('',(23.1153922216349,13.9419628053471,13.6240984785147));
#1321=CARTESIAN_POINT('',(23.2485139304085,13.7775241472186,13.9655815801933));
#1322=CARTESIAN_POINT('',(23.3148131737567,13.6945295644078,14.1361798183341));
#1323=CARTESIAN_POINT('',(23.4468574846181,13.5269724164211,14.4770104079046));
#1324=CARTESIAN_POINT('',(23.5126020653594,13.4424086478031,14.6472423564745));
#1325=CARTESIAN_POINT('',(23.6435063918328,13.2716862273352,14.9872560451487));
#1326=CARTESIAN_POINT('',(23.7086658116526,13.1855267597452,15.1570375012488));
#1327=CARTESIAN_POINT('',(23.8383708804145,13.0115800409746,15.4960622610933));
#1328=CARTESIAN_POINT('',(23.9029163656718,12.9237923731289,15.6653054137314));
#1329=CARTESIAN_POINT('',(24.0346515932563,12.7420155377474,16.0118008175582));
#1330=CARTESIAN_POINT('',(24.1018077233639,12.6479388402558,16.1890199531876));
#1331=CARTESIAN_POINT('',(24.2353851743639,12.4578797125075,16.5426492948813));
#1332=CARTESIAN_POINT('',(24.3018066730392,12.3618977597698,16.719059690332));
#1333=CARTESIAN_POINT('',(24.4338909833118,12.1679502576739,17.070948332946));
#1334=CARTESIAN_POINT('',(24.4995541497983,12.069985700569,17.246426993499));
#1335=CARTESIAN_POINT('',(24.6301022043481,11.8719735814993,17.5963153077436));
#1336=CARTESIAN_POINT('',(24.6949876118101,11.7719275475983,17.7707256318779));
#1337=CARTESIAN_POINT('',(24.8239660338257,11.569624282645,18.1183224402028));
#1338=CARTESIAN_POINT('',(24.8880597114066,11.4673691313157,18.2915098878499));
#1339=CARTESIAN_POINT('',(25.0153011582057,11.2607184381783,18.6360852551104));
#1340=CARTESIAN_POINT('',(25.078451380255,11.1563312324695,18.807477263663));
#1341=CARTESIAN_POINT('',(25.2040315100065,10.944847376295,19.1488531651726));
#1342=CARTESIAN_POINT('',(25.2664614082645,10.837750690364,19.3188370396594));
#1343=CARTESIAN_POINT('',(25.3906825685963,10.6204228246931,19.6573232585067));
#1344=CARTESIAN_POINT('',(25.4524730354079,10.5101882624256,19.8258237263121));
#1345=CARTESIAN_POINT('',(25.575509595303,10.286038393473,20.1611869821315));
#1346=CARTESIAN_POINT('',(25.6367540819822,10.1721150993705,20.3280450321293));
#1347=CARTESIAN_POINT('',(25.7588134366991,9.93986271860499,20.65984499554));
#1348=CARTESIAN_POINT('',(25.8196258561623,9.82151880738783,20.824777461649));
#1349=CARTESIAN_POINT('',(25.9392311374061,9.58289225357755,21.147566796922));
#1350=CARTESIAN_POINT('',(25.9980380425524,9.46271901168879,21.3054989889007));
#1351=CARTESIAN_POINT('',(26.115137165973,9.21686137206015,21.6172391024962));
#1352=CARTESIAN_POINT('',(26.173429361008,9.09117672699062,21.7710468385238));
#1353=CARTESIAN_POINT('',(26.2893965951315,8.83332773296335,22.0725078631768));
#1354=CARTESIAN_POINT('',(26.347073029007,8.70118591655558,22.2201796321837));
#1355=CARTESIAN_POINT('',(26.4331805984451,8.49666780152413,22.435137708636));
#1356=CARTESIAN_POINT('',(26.4617466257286,8.42761887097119,22.5055362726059));
#1357=CARTESIAN_POINT('',(26.5187954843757,8.28699336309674,22.6437891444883));
#1358=CARTESIAN_POINT('',(26.5472783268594,8.21541714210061,22.7116438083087));
#1359=CARTESIAN_POINT('',(26.6040941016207,8.06951458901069,22.8440275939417));
#1360=CARTESIAN_POINT('',(26.6324272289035,7.99519511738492,22.9085641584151));
#1361=CARTESIAN_POINT('',(26.6889823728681,7.84321771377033,23.0336070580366));
#1362=CARTESIAN_POINT('',(26.7172044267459,7.76556102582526,23.0941148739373));
#1363=CARTESIAN_POINT('',(26.7667879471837,7.62534456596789,23.1961554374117));
#1364=CARTESIAN_POINT('',(26.7881834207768,7.56359118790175,23.2387765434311));
#1365=CARTESIAN_POINT('',(26.8308430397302,7.43760039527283,23.3203478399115));
#1366=CARTESIAN_POINT('',(26.8521071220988,7.37336188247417,23.3592963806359));
#1367=CARTESIAN_POINT('',(26.8943545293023,7.24243144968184,23.4325619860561));
#1368=CARTESIAN_POINT('',(26.9153384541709,7.17574657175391,23.4668911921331));
#1369=CARTESIAN_POINT('',(26.9569508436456,7.03969894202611,23.5300330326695));
#1370=CARTESIAN_POINT('',(26.9775794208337,6.9703370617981,23.5588474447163));
#1371=CARTESIAN_POINT('',(27.0136063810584,6.84531290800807,23.603977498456));
#1372=CARTESIAN_POINT('',(27.0291160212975,6.79017083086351,23.6216434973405));
#1373=CARTESIAN_POINT('',(27.0596999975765,6.67853352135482,23.652534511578));
#1374=CARTESIAN_POINT('',(27.0747743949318,6.62203848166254,23.6657601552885));
#1375=CARTESIAN_POINT('',(27.1043548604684,6.50798595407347,23.6873163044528));
#1376=CARTESIAN_POINT('',(27.1188611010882,6.45042879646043,23.6956483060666));
#1377=CARTESIAN_POINT('',(27.1471745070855,6.33462228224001,23.7071016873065));
#1378=CARTESIAN_POINT('',(27.1609816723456,6.27637292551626,23.7102230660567));
#1379=CARTESIAN_POINT('',(27.1878068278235,6.15949432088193,23.7111271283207));
#1380=CARTESIAN_POINT('',(27.2008227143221,6.10086448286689,23.7088961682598));
#1381=CARTESIAN_POINT('',(27.2259315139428,5.98385079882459,23.6991603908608));
#1382=CARTESIAN_POINT('',(27.2380244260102,5.92546695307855,23.6916555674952));
#1383=CARTESIAN_POINT('',(27.2612388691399,5.80934451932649,23.6716633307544));
#1384=CARTESIAN_POINT('',(27.2723599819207,5.751606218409,23.6591737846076));
#1385=CARTESIAN_POINT('',(27.2936179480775,5.63711222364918,23.6296492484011));
#1386=CARTESIAN_POINT('',(27.3037544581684,5.58035687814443,23.6126126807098));
#1387=CARTESIAN_POINT('',(27.3275496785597,5.44198111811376,23.5656541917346));
#1388=CARTESIAN_POINT('',(27.3406590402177,5.36104865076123,23.5334220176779));
#1389=CARTESIAN_POINT('',(27.3649864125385,5.20206479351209,23.4619189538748));
#1390=CARTESIAN_POINT('',(27.3762032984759,5.12401513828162,23.4226439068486));
#1391=CARTESIAN_POINT('',(27.3969935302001,4.97051803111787,23.3383431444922));
#1392=CARTESIAN_POINT('',(27.4065608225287,4.89508094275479,23.2932972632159));
#1393=CARTESIAN_POINT('',(27.4242142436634,4.74692900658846,23.1987460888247));
#1394=CARTESIAN_POINT('',(27.4323007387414,4.67421348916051,23.1492419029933));
#1395=CARTESIAN_POINT('',(27.4473112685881,4.53003017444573,23.0458202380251));
#1396=CARTESIAN_POINT('',(27.4542137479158,4.45860320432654,22.9918430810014));
#1397=CARTESIAN_POINT('',(27.4668593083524,4.31797433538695,22.8809248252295));
#1398=CARTESIAN_POINT('',(27.4726021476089,4.24877290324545,22.8239831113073));
#1399=CARTESIAN_POINT('',(27.4883257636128,4.0438743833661,22.6493843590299));
#1400=CARTESIAN_POINT('',(27.4967773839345,3.91112384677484,22.5281318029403));
#1401=CARTESIAN_POINT('',(27.5104565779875,3.65162488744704,22.2790375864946));
#1402=CARTESIAN_POINT('',(27.515680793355,3.52488284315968,22.151189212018));
#1403=CARTESIAN_POINT('',(27.5234720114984,3.27563804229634,21.8901995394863));
#1404=CARTESIAN_POINT('',(27.5260262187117,3.15315839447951,21.75703590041));
#1405=CARTESIAN_POINT('',(27.5288274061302,2.91228469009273,21.4873746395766));
#1406=CARTESIAN_POINT('',(27.5290774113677,2.79388548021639,21.3508816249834));
#1407=CARTESIAN_POINT('',(27.5275585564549,2.56034585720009,21.0752314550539));
#1408=CARTESIAN_POINT('',(27.5257903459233,2.44520440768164,20.9360751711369));
#1409=CARTESIAN_POINT('',(27.5203164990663,2.21225454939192,20.6489933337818));
#1410=CARTESIAN_POINT('',(27.51652338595,2.09457663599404,20.5009638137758));
#1411=CARTESIAN_POINT('',(27.5071276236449,1.86174047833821,20.2029896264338));
#1412=CARTESIAN_POINT('',(27.5015249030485,1.74658233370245,20.0530448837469));
#1413=CARTESIAN_POINT('',(27.4822094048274,1.40428160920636,19.6007413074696));
#1414=CARTESIAN_POINT('',(27.4659915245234,1.18039808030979,19.296019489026));
#1415=CARTESIAN_POINT('',(27.4277462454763,0.740461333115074,18.6834059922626));
#1416=CARTESIAN_POINT('',(27.4057447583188,0.524377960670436,18.3755341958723));
#1417=CARTESIAN_POINT('',(27.3564155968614,0.0979230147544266,17.7563558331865));
#1418=CARTESIAN_POINT('',(27.32908871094,-0.112449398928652,17.4450497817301));
#1419=CARTESIAN_POINT('',(27.2692049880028,-0.5302324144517,16.8166629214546));
#1420=CARTESIAN_POINT('',(27.2366009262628,-0.737595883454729,16.4995553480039));
#1421=CARTESIAN_POINT('',(27.1666532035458,-1.14782129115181,15.8629372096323));
#1422=CARTESIAN_POINT('',(27.1293092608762,-1.35068296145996,15.543426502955));
#1423=CARTESIAN_POINT('',(27.0500016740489,-1.75292799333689,14.9013020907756));
#1424=CARTESIAN_POINT('',(27.0080230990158,-1.9522975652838,14.5786816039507));
#1425=CARTESIAN_POINT('',(26.9197590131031,-2.34709411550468,13.9316703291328));
#1426=CARTESIAN_POINT('',(26.873473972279,-2.5425215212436,13.6072797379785));
#1427=CARTESIAN_POINT('',(26.8251366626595,-2.73611461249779,13.282109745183));
#1428=B_SPLINE_CURVE_WITH_KNOTS('',3,(#1318,#1319,#1320,#1321,#1322,#1323,#1324,#1325,#1326,
#1327,#1328,#1329,#1330,#1331,#1332,#1333,#1334,#1335,#1336,#1337,#1338,#1339,#1340,#1341,#1342,
#1343,#1344,#1345,#1346,#1347,#1348,#1349,#1350,#1351,#1352,#1353,#1354,#1355,#1356,#1357,#1358,
#1359,#1360,#1361,#1362,#1363,#1364,#1365,#1366,#1367,#1368,#1369,#1370,#1371,#1372,#1373,#1374,
#1375,#1376,#1377,#1378,#1379,#1380,#1381,#1382,#1383,#1384,#1385,#1386,#1387,#1388,#1389,#1390,
#1391,#1392,#1393,#1394,#1395,#1396,#1397,#1398,#1399,#1400,#1401,#1402,#1403,#1404,#1405,#1406,
#1407,#1408,#1409,#1410,#1411,#1412,#1413,#1414,#1415,#1416,#1417,#1418,#1419,#1420,#1421,#1422,
#1423,#1424,#1425,#1426,#1427),.UNSPECIFIED.,.F.,.F.,(4,2,2,2,2,2,2,2,2,2,2,2,2,2,2,2,2,2,2,2,2,
2,2,2,2,2,2,2,2,2,2,2,2,2,2,2,2,2,2,2,2,2,2,2,2,2,2,2,2,2,2,2,2,2,4),(0.,0.602238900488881,
1.20513094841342,1.808506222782,2.41219896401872,3.01604838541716,3.65078381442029,
4.28536211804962,4.91963031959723,5.55344826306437,6.18669348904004,6.81781325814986,
7.44894129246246,8.08077755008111,8.71408792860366,9.3497562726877,9.97061520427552,
10.5915020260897,11.2103585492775,11.5182997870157,11.8261977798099,12.1333719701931,
12.4404326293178,12.6744033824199,12.908478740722,13.1419263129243,13.3752985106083,
13.554971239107,13.734618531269,13.9142108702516,14.0938032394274,14.273853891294,
14.4539047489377,14.6340327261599,14.8142232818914,15.078062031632,15.3420570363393,
15.6070010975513,15.8718795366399,16.1411605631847,16.4104976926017,16.9500709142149,
17.4902046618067,18.0329152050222,18.5749131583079,19.1167367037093,19.6841250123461,
20.2515357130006,21.386766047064,22.5169945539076,23.6470558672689,24.7878543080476,
25.9287205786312,27.0733758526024,28.2179063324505),.UNSPECIFIED.);
#1429=EDGE_CURVE('E250',#490,#401,#1428,.T.);
#1430=ORIENTED_EDGE('',*,*,#1429,.F.);
#1431=ORIENTED_EDGE('',*,*,#493,.T.);
#1432=CARTESIAN_POINT('',(3.30163995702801,26.7614172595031,13.282109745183));
#1433=CARTESIAN_POINT('',(3.40660636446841,26.7635501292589,13.4532141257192));
#1434=CARTESIAN_POINT('',(3.51194586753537,26.7650129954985,13.6240984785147));
#1435=CARTESIAN_POINT('',(3.72350921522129,26.7665659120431,13.9655815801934));
#1436=CARTESIAN_POINT('',(3.82973389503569,26.7666544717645,14.1361798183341));
#1437=CARTESIAN_POINT('',(4.04306362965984,26.7654206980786,14.4770104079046));
#1438=CARTESIAN_POINT('',(4.15016932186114,26.7640972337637,14.6472423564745));
#1439=CARTESIAN_POINT('',(4.36526299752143,26.7599986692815,14.9872560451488));
#1440=CARTESIAN_POINT('',(4.47325141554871,26.7572228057,15.1570375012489));
#1441=CARTESIAN_POINT('',(4.690118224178,26.7501763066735,15.4960622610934));
#1442=CARTESIAN_POINT('',(4.79899683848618,26.745905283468,15.6653054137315));
#1443=CARTESIAN_POINT('',(5.02325126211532,26.7355640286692,16.0118008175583));
#1444=CARTESIAN_POINT('',(5.13867454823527,26.7294129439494,16.1890199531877));
#1445=CARTESIAN_POINT('',(5.37055293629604,26.7153480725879,16.5426492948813));
#1446=CARTESIAN_POINT('',(5.4870077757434,26.7074347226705,16.7190596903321));
#1447=CARTESIAN_POINT('',(5.72099525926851,26.6897781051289,17.0709483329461));
#1448=CARTESIAN_POINT('',(5.83852734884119,26.6800357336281,17.2464269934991));
#1449=CARTESIAN_POINT('',(6.07473483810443,26.6586437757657,17.5963153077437));
#1450=CARTESIAN_POINT('',(6.19340936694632,26.6469955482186,17.7707256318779));
#1451=CARTESIAN_POINT('',(6.43199315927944,26.6217009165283,18.1183224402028));
#1452=CARTESIAN_POINT('',(6.55190121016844,26.6080563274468,18.2915098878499));
#1453=CARTESIAN_POINT('',(6.79280097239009,26.5786930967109,18.6360852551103));
#1454=CARTESIAN_POINT('',(6.91378769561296,26.56298157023,18.8074772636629));
#1455=CARTESIAN_POINT('',(7.15743036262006,26.5293060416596,19.1488531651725));
#1456=CARTESIAN_POINT('',(7.28008632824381,26.5113420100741,19.3188370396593));
#1457=CARTESIAN_POINT('',(7.52745072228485,26.4729603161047,19.6573232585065));
#1458=CARTESIAN_POINT('',(7.65216129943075,26.4525399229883,19.8258237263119));
#1459=CARTESIAN_POINT('',(7.90412076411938,26.4089786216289,20.1611869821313));
#1460=CARTESIAN_POINT('',(8.03137489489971,26.3858314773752,20.3280450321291));
#1461=CARTESIAN_POINT('',(8.28905988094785,26.336454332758,20.6598449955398));
#1462=CARTESIAN_POINT('',(8.41950079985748,26.3102131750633,20.8247774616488));
#1463=CARTESIAN_POINT('',(8.6806392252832,26.2549431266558,21.1475667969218));
#1464=CARTESIAN_POINT('',(8.81125995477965,26.2259934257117,21.3054989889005));
#1465=CARTESIAN_POINT('',(9.07648930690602,26.1642554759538,21.6172391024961));
#1466=CARTESIAN_POINT('',(9.21109810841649,26.1314670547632,21.7710468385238));
#1467=CARTESIAN_POINT('',(9.48499695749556,26.0613676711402,22.0725078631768));
#1468=CARTESIAN_POINT('',(9.62427025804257,26.0240718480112,22.2201796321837));
#1469=CARTESIAN_POINT('',(9.83785615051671,25.9638784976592,22.435137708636));
#1470=CARTESIAN_POINT('',(9.90965140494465,25.9431610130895,22.5055362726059));
#1471=CARTESIAN_POINT('',(10.0551662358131,25.9000850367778,22.6437891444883));
#1472=CARTESIAN_POINT('',(10.1288855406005,25.877726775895,22.7116438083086));
#1473=CARTESIAN_POINT('',(10.278380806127,25.8311783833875,22.8440275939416));
#1474=CARTESIAN_POINT('',(10.35415152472,25.8069926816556,22.908564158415));
#1475=CARTESIAN_POINT('',(10.5082337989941,25.7564529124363,23.0336070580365));
#1476=CARTESIAN_POINT('',(10.5865444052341,25.7300996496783,23.0941148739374));
#1477=CARTESIAN_POINT('',(10.727084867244,25.6814420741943,23.1961554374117));
#1478=CARTESIAN_POINT('',(10.7887054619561,25.6596671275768,23.2387765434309));
#1479=CARTESIAN_POINT('',(10.9138068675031,25.6144657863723,23.3203478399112));
#1480=CARTESIAN_POINT('',(10.9772884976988,25.5910386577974,23.3592963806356));
#1481=CARTESIAN_POINT('',(11.1059948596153,25.5424352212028,23.4325619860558));
#1482=CARTESIAN_POINT('',(11.1712144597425,25.5172637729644,23.4668911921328));
#1483=CARTESIAN_POINT('',(11.3035256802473,25.4649733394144,23.5300330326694));
#1484=CARTESIAN_POINT('',(11.3706166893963,25.4378549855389,23.5588474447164));
#1485=CARTESIAN_POINT('',(11.4908269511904,25.3880707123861,23.603977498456));
#1486=CARTESIAN_POINT('',(11.5436088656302,25.3658161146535,23.6216434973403));
#1487=CARTESIAN_POINT('',(11.6499592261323,25.3201229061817,23.6525345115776));
#1488=CARTESIAN_POINT('',(11.7035275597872,25.2966844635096,23.6657601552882));
#1489=CARTESIAN_POINT('',(11.8111405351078,25.2487008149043,23.6873163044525));
#1490=CARTESIAN_POINT('',(11.8651850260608,25.2241559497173,23.6956483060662));
#1491=CARTESIAN_POINT('',(11.9733793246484,25.1740880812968,23.7071016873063));
#1492=CARTESIAN_POINT('',(12.0275291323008,25.1485650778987,23.7102230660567));
#1493=CARTESIAN_POINT('',(12.1356337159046,25.0966652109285,23.7111271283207));
#1494=CARTESIAN_POINT('',(12.1895876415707,25.0702863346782,23.7088961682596));
#1495=CARTESIAN_POINT('',(12.2967277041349,25.0169603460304,23.6991603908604));
#1496=CARTESIAN_POINT('',(12.3499138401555,24.9900132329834,23.6916555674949));
#1497=CARTESIAN_POINT('',(12.4551759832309,24.9357618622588,23.6716633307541));
#1498=CARTESIAN_POINT('',(12.5072515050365,24.9084574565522,23.6591737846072));
#1499=CARTESIAN_POINT('',(12.6100206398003,24.8536917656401,23.6296492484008));
#1500=CARTESIAN_POINT('',(12.6607137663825,24.8262304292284,23.6126126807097));
#1501=CARTESIAN_POINT('',(12.7837363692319,24.7585584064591,23.5656541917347));
#1502=CARTESIAN_POINT('',(12.8551854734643,24.7183471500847,23.5334220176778));
#1503=CARTESIAN_POINT('',(12.9946519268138,24.6382422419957,23.4619189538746));
#1504=CARTESIAN_POINT('',(13.0626672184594,24.5983487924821,23.4226439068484));
#1505=CARTESIAN_POINT('',(13.1956385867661,24.5188993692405,23.3383431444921));
#1506=CARTESIAN_POINT('',(13.2605827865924,24.4793451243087,23.2932972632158));
#1507=CARTESIAN_POINT('',(13.3874193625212,24.4007759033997,23.1987460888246));
#1508=CARTESIAN_POINT('',(13.4493124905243,24.3617607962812,23.1492419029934));
#1509=CARTESIAN_POINT('',(13.5713984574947,24.2835996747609,23.0458202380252));
#1510=CARTESIAN_POINT('',(13.6315459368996,24.2444622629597,22.9918430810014));
#1511=CARTESIAN_POINT('',(13.7493783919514,24.1666682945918,22.8809248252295));
#1512=CARTESIAN_POINT('',(13.8070628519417,24.128011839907,22.8239831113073));
#1513=CARTESIAN_POINT('',(13.9770624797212,24.0125529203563,22.64938435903));
#1514=CARTESIAN_POINT('',(14.0861205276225,23.9363920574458,22.5281318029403));
#1515=CARTESIAN_POINT('',(14.2975338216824,23.7852919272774,22.2790375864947));
#1516=CARTESIAN_POINT('',(14.399881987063,23.710354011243,22.1511892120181));
#1517=CARTESIAN_POINT('',(14.5996071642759,23.5610438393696,21.8901995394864));
#1518=CARTESIAN_POINT('',(14.69695813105,23.4866759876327,21.7570359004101));
#1519=CARTESIAN_POINT('',(14.8870272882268,23.3386837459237,21.4873746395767));
#1520=CARTESIAN_POINT('',(14.9797513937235,23.2650585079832,21.3508816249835));
#1521=CARTESIAN_POINT('',(15.1613930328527,23.1182614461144,21.0752314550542));
#1522=CARTESIAN_POINT('',(15.2503117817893,23.045089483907,20.9360751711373));
#1523=CARTESIAN_POINT('',(15.4290264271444,22.8955679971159,20.6489933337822));
#1524=CARTESIAN_POINT('',(15.5186657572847,22.8192314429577,20.5009638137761));
#1525=CARTESIAN_POINT('',(15.6948462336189,22.6667145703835,20.202989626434));
#1526=CARTESIAN_POINT('',(15.7813872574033,22.5905342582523,20.0530448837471));
#1527=CARTESIAN_POINT('',(16.0369657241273,22.3620117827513,19.6007413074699));
#1528=CARTESIAN_POINT('',(16.2018932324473,22.2097430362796,19.2960194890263));
#1529=CARTESIAN_POINT('',(16.5220040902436,21.9055455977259,18.6834059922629));
#1530=CARTESIAN_POINT('',(16.6772271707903,21.7536183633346,18.3755341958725));
#1531=CARTESIAN_POINT('',(16.9798868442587,21.4491609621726,17.7563558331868));
#1532=CARTESIAN_POINT('',(17.1273245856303,21.2966308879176,17.4450497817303));
#1533=CARTESIAN_POINT('',(17.416623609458,20.9893284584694,16.8166629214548));
#1534=CARTESIAN_POINT('',(17.5584185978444,20.8345485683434,16.4995553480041));
#1535=CARTESIAN_POINT('',(17.8355340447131,20.5240898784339,15.8629372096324));
#1536=CARTESIAN_POINT('',(17.9708541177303,20.3684110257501,15.5434265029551));
#1537=CARTESIAN_POINT('',(18.2358944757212,20.0556101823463,14.9013020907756));
#1538=CARTESIAN_POINT('',(18.3655946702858,19.8984851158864,14.5786816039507));
#1539=CARTESIAN_POINT('',(18.6192272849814,19.5833258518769,13.9316703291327));
#1540=CARTESIAN_POINT('',(18.7431603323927,19.4252917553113,13.6072797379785));
#1541=CARTESIAN_POINT('',(18.8643796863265,19.2667968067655,13.282109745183));
#1542=B_SPLINE_CURVE_WITH_KNOTS('',3,(#1432,#1433,#1434,#1435,#1436,#1437,#1438,#1439,#1440,
#1441,#1442,#1443,#1444,#1445,#1446,#1447,#1448,#1449,#1450,#1451,#1452,#1453,#1454,#1455,#1456,
#1457,#1458,#1459,#1460,#1461,#1462,#1463,#1464,#1465,#1466,#1467,#1468,#1469,#1470,#1471,#1472,
#1473,#1474,#1475,#1476,#1477,#1478,#1479,#1480,#1481,#1482,#1483,#1484,#1485,#1486,#1487,#1488,
#1489,#1490,#1491,#1492,#1493,#1494,#1495,#1496,#1497,#1498,#1499,#1500,#1501,#1502,#1503,#1504,
#1505,#1506,#1507,#1508,#1509,#1510,#1511,#1512,#1513,#1514,#1515,#1516,#1517,#1518,#1519,#1520,
#1521,#1522,#1523,#1524,#1525,#1526,#1527,#1528,#1529,#1530,#1531,#1532,#1533,#1534,#1535,#1536,
#1537,#1538,#1539,#1540,#1541),.UNSPECIFIED.,.F.,.F.,(4,2,2,2,2,2,2,2,2,2,2,2,2,2,2,2,2,2,2,2,2,
2,2,2,2,2,2,2,2,2,2,2,2,2,2,2,2,2,2,2,2,2,2,2,2,2,2,2,2,2,2,2,2,2,4),(0.,0.602238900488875,
1.20513094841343,1.80850622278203,2.41219896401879,3.01604838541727,3.65078381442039,
4.28536211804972,4.9196303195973,5.55344826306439,6.18669348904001,6.81781325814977,
7.4489412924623,8.0807775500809,8.71408792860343,9.34975627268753,9.97061520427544,
10.5915020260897,11.2103585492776,11.5182997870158,11.8261977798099,12.1333719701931,
12.4404326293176,12.6744033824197,12.9084787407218,13.1419263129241,13.3752985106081,
13.5549712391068,13.7346185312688,13.9142108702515,14.0938032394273,14.2738538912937,
14.4539047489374,14.6340327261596,14.8142232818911,15.0780620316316,15.3420570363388,
15.6070010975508,15.8718795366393,16.1411605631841,16.4104976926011,16.9500709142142,
17.490204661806,18.0329152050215,18.5749131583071,19.1167367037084,19.6841250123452,
20.2515357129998,21.3867660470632,22.5169945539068,23.6470558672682,24.787854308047,
25.9287205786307,27.0733758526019,28.2179063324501),.UNSPECIFIED.);
#1543=EDGE_CURVE('E231',#772,#492,#1542,.T.);
#1544=ORIENTED_EDGE('',*,*,#1543,.F.);
#1545=ORIENTED_EDGE('',*,*,#775,.T.);
#1546=CARTESIAN_POINT('',(-18.8643796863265,19.2667968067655,13.282109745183));
#1547=CARTESIAN_POINT('',(-18.8006017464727,19.3501926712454,13.4532141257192));
#1548=CARTESIAN_POINT('',(-18.7360673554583,19.4334624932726,13.6240984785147));
#1549=CARTESIAN_POINT('',(-18.6053738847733,19.5998376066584,13.9655815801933));
#1550=CARTESIAN_POINT('',(-18.5392131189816,19.6829426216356,14.1361798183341));
#1551=CARTESIAN_POINT('',(-18.4052396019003,19.8489612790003,14.4770104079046));
#1552=CARTESIAN_POINT('',(-18.3374255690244,19.9318747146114,14.6472423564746));
#1553=CARTESIAN_POINT('',(-18.2001124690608,20.0974863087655,14.9872560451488));
#1554=CARTESIAN_POINT('',(-18.1306125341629,20.1801843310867,15.157037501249));
#1555=CARTESIAN_POINT('',(-17.9898891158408,20.3453442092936,15.4960622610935));
#1556=CARTESIAN_POINT('',(-17.9186651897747,20.4278059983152,15.6653054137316));
#1557=CARTESIAN_POINT('',(-17.7707597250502,20.5966874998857,16.0118008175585));
#1558=CARTESIAN_POINT('',(-17.6939853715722,20.683093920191,16.1890199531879));
#1559=CARTESIAN_POINT('',(-17.5384152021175,20.8556144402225,16.5426492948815));
#1560=CARTESIAN_POINT('',(-17.4596198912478,20.9417286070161,16.7190596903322));
#1561=CARTESIAN_POINT('',(-17.2999265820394,21.113658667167,17.0709483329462));
#1562=CARTESIAN_POINT('',(-17.2190296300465,21.1994746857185,17.2464269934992));
#1563=CARTESIAN_POINT('',(-17.0550317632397,21.3708114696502,17.5963153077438));
#1564=CARTESIAN_POINT('',(-16.9719324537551,21.4563324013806,17.7707256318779));
#1565=CARTESIAN_POINT('',(-16.8034017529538,21.6270937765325,18.1183224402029));
#1566=CARTESIAN_POINT('',(-16.7179725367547,21.7123344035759,18.29150988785));
#1567=CARTESIAN_POINT('',(-16.544816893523,21.8823697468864,18.6360852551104));
#1568=CARTESIAN_POINT('',(-16.4570991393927,21.9671649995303,18.8074772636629));
#1569=CARTESIAN_POINT('',(-16.2788618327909,22.1366561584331,19.1488531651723));
#1570=CARTESIAN_POINT('',(-16.1883422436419,22.2213520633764,19.3188370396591));
#1571=CARTESIAN_POINT('',(-16.0041050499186,22.3908187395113,19.6573232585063));
#1572=CARTESIAN_POINT('',(-15.9103839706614,22.4755894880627,19.8258237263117));
#1573=CARTESIAN_POINT('',(-15.7192322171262,22.6454193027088,20.1611869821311));
#1574=CARTESIAN_POINT('',(-15.6217933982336,22.7304785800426,20.3280450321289));
#1575=CARTESIAN_POINT('',(-15.4225248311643,22.9011586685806,20.6598449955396));
#1576=CARTESIAN_POINT('',(-15.3206800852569,22.9867803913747,20.8247774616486));
#1577=CARTESIAN_POINT('',(-15.1146510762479,23.1564863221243,21.1475667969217));
#1578=CARTESIAN_POINT('',(-15.0105765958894,23.2405598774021,21.3054989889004));
#1579=CARTESIAN_POINT('',(-14.7969401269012,23.4094315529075,21.6172391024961));
#1580=CARTESIAN_POINT('',(-14.6873778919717,23.4942297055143,21.7710468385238));
#1581=CARTESIAN_POINT('',(-14.4617988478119,23.6646661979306,22.0725078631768));
#1582=CARTESIAN_POINT('',(-14.3458043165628,23.7503008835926,22.2201796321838));
#1583=CARTESIAN_POINT('',(-14.1655746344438,23.8797591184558,22.435137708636));
#1584=CARTESIAN_POINT('',(-14.104613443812,23.9229737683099,22.5055362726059));
#1585=CARTESIAN_POINT('',(-13.9802082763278,24.0098844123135,22.6437891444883));
#1586=CARTESIAN_POINT('',(-13.9167646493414,24.0535803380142,22.7116438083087));
#1587=CARTESIAN_POINT('',(-13.7871628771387,24.1414379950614,22.8440275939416));
#1588=CARTESIAN_POINT('',(-13.7210114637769,24.185598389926,22.9085641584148));
#1589=CARTESIAN_POINT('',(-13.5854291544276,24.2745537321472,23.0336070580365));
#1590=CARTESIAN_POINT('',(-13.51599947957,24.3193484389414,23.0941148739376));
#1591=CARTESIAN_POINT('',(-13.3903319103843,24.3988898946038,23.1961554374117));
#1592=CARTESIAN_POINT('',(-13.3348877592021,24.4334903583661,23.2387765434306));
#1593=CARTESIAN_POINT('',(-13.2215484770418,24.5031160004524,23.3203478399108));
#1594=CARTESIAN_POINT('',(-13.1636522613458,24.5381413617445,23.3592963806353));
#1595=CARTESIAN_POINT('',(-13.0454054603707,24.6084643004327,23.4325619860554));
#1596=CARTESIAN_POINT('',(-12.9850618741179,24.6437608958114,23.4668911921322));
#1597=CARTESIAN_POINT('',(-12.8616848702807,24.7146034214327,23.5300330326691));
#1598=CARTESIAN_POINT('',(-12.7986523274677,24.7501492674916,23.5588474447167));
#1599=CARTESIAN_POINT('',(-12.6847795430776,24.813093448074,23.603977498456));
#1600=CARTESIAN_POINT('',(-12.6344712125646,24.8404844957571,23.6216434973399));
#1601=CARTESIAN_POINT('',(-12.5324384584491,24.895143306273,23.6525345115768));
#1602=CARTESIAN_POINT('',(-12.4807142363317,24.9224110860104,23.6657601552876));
#1603=CARTESIAN_POINT('',(-12.3761035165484,24.9766289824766,23.6873163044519));
#1604=CARTESIAN_POINT('',(-12.3232173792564,25.0035791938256,23.6956483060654));
#1605=CARTESIAN_POINT('',(-12.2166147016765,25.0569520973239,23.7071016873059));
#1606=CARTESIAN_POINT('',(-12.1628981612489,25.0833747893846,23.7102230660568));
#1607=CARTESIAN_POINT('',(-12.0549191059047,25.1355353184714,23.7111271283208));
#1608=CARTESIAN_POINT('',(-12.000655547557,25.1612712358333,23.7088961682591));
#1609=CARTESIAN_POINT('',(-11.8921628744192,25.2117884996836,23.6991603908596));
#1610=CARTESIAN_POINT('',(-11.8379337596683,25.2365698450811,23.6916555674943));
#1611=CARTESIAN_POINT('',(-11.7298884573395,25.2850419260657,23.6716633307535));
#1612=CARTESIAN_POINT('',(-11.6760724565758,25.3087321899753,23.6591737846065));
#1613=CARTESIAN_POINT('',(-11.5691794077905,25.3549344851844,23.6296492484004));
#1614=CARTESIAN_POINT('',(-11.5161026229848,25.3774461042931,23.6126126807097));
#1615=CARTESIAN_POINT('',(-11.3864911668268,25.4314362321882,23.5656541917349));
#1616=CARTESIAN_POINT('',(-11.3105049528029,25.4622260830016,23.5334220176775));
#1617=CARTESIAN_POINT('',(-11.1609205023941,25.5213207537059,23.461918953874));
#1618=CARTESIAN_POINT('',(-11.0873237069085,25.5496240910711,23.4226439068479));
#1619=CARTESIAN_POINT('',(-10.9423013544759,25.6040493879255,23.3383431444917));
#1620=CARTESIAN_POINT('',(-10.8708845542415,25.6301631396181,23.2932972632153));
#1621=CARTESIAN_POINT('',(-10.7303753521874,25.6803408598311,23.1987460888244));
#1622=CARTESIAN_POINT('',(-10.6612823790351,25.7044053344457,23.1492419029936));
#1623=CARTESIAN_POINT('',(-10.5240541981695,25.7511233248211,23.0458202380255));
#1624=CARTESIAN_POINT('',(-10.4559539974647,25.7737467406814,22.9918430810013));
#1625=CARTESIAN_POINT('',(-10.321664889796,25.8173681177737,22.8809248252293));
#1626=CARTESIAN_POINT('',(-10.2554763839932,25.8383657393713,22.8239831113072));
#1627=CARTESIAN_POINT('',(-10.0592139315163,25.8992893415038,22.6493843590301));
#1628=CARTESIAN_POINT('',(-9.93167239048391,25.937068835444,22.5281318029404));
#1629=CARTESIAN_POINT('',(-9.68172351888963,26.0081490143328,22.2790375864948));
#1630=CARTESIAN_POINT('',(-9.55932165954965,26.0414450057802,22.1511892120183));
#1631=CARTESIAN_POINT('',(-9.31805965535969,26.1045030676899,21.8901995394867));
#1632=CARTESIAN_POINT('',(-9.19921919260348,26.1342475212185,21.7570359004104));
#1633=CARTESIAN_POINT('',(-8.96500801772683,26.1905779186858,21.4873746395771));
#1634=CARTESIAN_POINT('',(-8.84963295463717,26.2171679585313,21.3508816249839));
#1635=CARTESIAN_POINT('',(-8.62161068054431,26.2676546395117,21.0752314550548));
#1636=CARTESIAN_POINT('',(-8.50896260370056,26.2915521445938,20.936075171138));
#1637=CARTESIAN_POINT('',(-8.28063523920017,26.3380517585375,20.648993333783));
#1638=CARTESIAN_POINT('',(-8.16506370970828,26.3605395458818,20.5009638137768));
#1639=CARTESIAN_POINT('',(-7.93597448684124,26.4031902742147,20.2029896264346));
#1640=CARTESIAN_POINT('',(-7.82245687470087,26.4233531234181,20.0530448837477));
#1641=CARTESIAN_POINT('',(-7.48444024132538,26.4806909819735,19.6007413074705));
#1642=CARTESIAN_POINT('',(-7.2625611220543,26.5146984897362,19.2960194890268));
#1643=CARTESIAN_POINT('',(-6.82514413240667,26.5753072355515,18.6834059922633));
#1644=CARTESIAN_POINT('',(-6.6095826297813,26.6019404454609,18.3755341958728));
#1645=CARTESIAN_POINT('',(-6.18284302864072,26.6487432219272,17.7563558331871));
#1646=CARTESIAN_POINT('',(-5.97166428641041,26.668913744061,17.4450497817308));
#1647=CARTESIAN_POINT('',(-5.55103058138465,26.7034968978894,16.8166629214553));
#1648=CARTESIAN_POINT('',(-5.34161106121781,26.7178530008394,16.4995553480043));
#1649=CARTESIAN_POINT('',(-4.92610602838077,26.7409427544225,15.8629372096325));
#1650=CARTESIAN_POINT('',(-4.72002071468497,26.7496760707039,15.5434265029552));
#1651=CARTESIAN_POINT('',(-4.31021320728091,26.7618648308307,14.9013020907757));
#1652=CARTESIAN_POINT('',(-4.1065011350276,26.7653026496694,14.5786816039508));
#1653=CARTESIAN_POINT('',(-3.70196235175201,26.7671020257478,13.9316703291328));
#1654=CARTESIAN_POINT('',(-3.5011353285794,26.7654641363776,13.6072797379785));
#1655=CARTESIAN_POINT('',(-3.30163995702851,26.7614172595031,13.282109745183));
#1656=B_SPLINE_CURVE_WITH_KNOTS('',3,(#1546,#1547,#1548,#1549,#1550,#1551,#1552,#1553,#1554,
#1555,#1556,#1557,#1558,#1559,#1560,#1561,#1562,#1563,#1564,#1565,#1566,#1567,#1568,#1569,#1570,
#1571,#1572,#1573,#1574,#1575,#1576,#1577,#1578,#1579,#1580,#1581,#1582,#1583,#1584,#1585,#1586,
#1587,#1588,#1589,#1590,#1591,#1592,#1593,#1594,#1595,#1596,#1597,#1598,#1599,#1600,#1601,#1602,
#1603,#1604,#1605,#1606,#1607,#1608,#1609,#1610,#1611,#1612,#1613,#1614,#1615,#1616,#1617,#1618,
#1619,#1620,#1621,#1622,#1623,#1624,#1625,#1626,#1627,#1628,#1629,#1630,#1631,#1632,#1633,#1634,
#1635,#1636,#1637,#1638,#1639,#1640,#1641,#1642,#1643,#1644,#1645,#1646,#1647,#1648,#1649,#1650,
#1651,#1652,#1653,#1654,#1655),.UNSPECIFIED.,.F.,.F.,(4,2,2,2,2,2,2,2,2,2,2,2,2,2,2,2,2,2,2,2,2,
2,2,2,2,2,2,2,2,2,2,2,2,2,2,2,2,2,2,2,2,2,2,2,2,2,2,2,2,2,2,2,2,2,4),(0.,0.602238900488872,
1.20513094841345,1.8085062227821,2.41219896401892,3.01604838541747,3.65078381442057,
4.28536211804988,4.91963031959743,5.55344826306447,6.18669348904,6.81781325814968,
7.44894129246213,8.08077755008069,8.71408792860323,9.34975627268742,9.97061520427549,
10.5915020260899,11.2103585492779,11.5182997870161,11.8261977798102,12.1333719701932,
12.4404326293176,12.6744033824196,12.9084787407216,13.1419263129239,13.3752985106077,
13.5549712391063,13.7346185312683,13.914210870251,14.0938032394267,14.2738538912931,
14.4539047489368,14.6340327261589,14.8142232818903,15.0780620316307,15.342057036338,
15.6070010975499,15.8718795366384,16.141160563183,16.4104976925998,16.9500709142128,
17.4902046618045,18.0329152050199,18.5749131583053,19.1167367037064,19.6841250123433,
20.2515357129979,21.3867660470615,22.5169945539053,23.6470558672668,24.7878543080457,
25.9287205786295,27.0733758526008,28.2179063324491),.UNSPECIFIED.);
#1657=EDGE_CURVE('E224',#86,#774,#1656,.T.);
#1658=ORIENTED_EDGE('',*,*,#1657,.F.);
#1659=ORIENTED_EDGE('',*,*,#87,.T.);
#1660=EDGE_LOOP('',(#974,#975,#1088,#1089,#1202,#1203,#1316,#1317,#1430,#1431,#1544,#1545,#1658,#1659));
#1661=FACE_BOUND('',#1660,.T.);
#1662=CARTESIAN_POINT('',(0.,0.,25.119995));
#1663=DIRECTION('',(0.,0.,1.));
#1664=DIRECTION('',(0.,1.,0.));
#1665=AXIS2_PLACEMENT_3D('',#1662,#1663,#1664);
#1666=CIRCLE('',#1665,28.);
#1667=CARTESIAN_POINT('',(0.,28.,25.119995));
#1668=VERTEX_POINT('',#1667);
#1669=EDGE_CURVE('E164',#1668,#1668,#1666,.T.);
#1670=ORIENTED_EDGE('',*,*,#1669,.F.);
#1671=EDGE_LOOP('',(#1670));
#1672=FACE_BOUND('',#1671,.T.);
#1673=ADVANCED_FACE('F239',(#1661,#1672),#861,.T.);
#1674=CARTESIAN_POINT('',(-27.245882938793,0.,25.119995));
#1675=DIRECTION('',(0.,0.,1.));
#1676=DIRECTION('',(0.,1.,0.));
#1677=AXIS2_PLACEMENT_3D('',#1674,#1675,#1676);
#1678=PLANE('',#1677);
#1679=ORIENTED_EDGE('',*,*,#1669,.T.);
#1680=EDGE_LOOP('',(#1679));
#1681=FACE_BOUND('',#1680,.T.);
#1682=CARTESIAN_POINT('',(0.,0.,25.119995));
#1683=DIRECTION('',(0.,0.,1.));
#1684=DIRECTION('',(0.,1.,0.));
#1685=AXIS2_PLACEMENT_3D('',#1682,#1683,#1684);
#1686=CIRCLE('',#1685,27.2458829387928);
#1687=CARTESIAN_POINT('',(0.,27.2458829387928,25.119995));
#1688=VERTEX_POINT('',#1687);
#1689=EDGE_CURVE('E170',#1688,#1688,#1686,.T.);
#1690=ORIENTED_EDGE('',*,*,#1689,.F.);
#1691=EDGE_LOOP('',(#1690));
#1692=FACE_BOUND('',#1691,.T.);
#1693=ADVANCED_FACE('F243',(#1681,#1692),#1678,.T.);
#1694=CARTESIAN_POINT('',(0.,0.,30.1700591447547));
#1695=DIRECTION('',(0.,0.,1.));
#1696=DIRECTION('',(0.,1.,0.));
#1697=AXIS2_PLACEMENT_3D('',#1694,#1695,#1696);
#1698=CYLINDRICAL_SURFACE('',#1697,27.2458829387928);
#1699=ORIENTED_EDGE('',*,*,#1689,.T.);
#1700=EDGE_LOOP('',(#1699));
#1701=FACE_BOUND('',#1700,.T.);
#1702=CARTESIAN_POINT('',(0.,0.,25.999995));
#1703=DIRECTION('',(0.,0.,1.));
#1704=DIRECTION('',(0.,1.,0.));
#1705=AXIS2_PLACEMENT_3D('',#1702,#1703,#1704);
#1706=CIRCLE('',#1705,27.2458829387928);
#1707=CARTESIAN_POINT('',(0.,27.2458829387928,25.999995));
#1708=VERTEX_POINT('',#1707);
#1709=EDGE_CURVE('E174',#1708,#1708,#1706,.T.);
#1710=ORIENTED_EDGE('',*,*,#1709,.F.);
#1711=EDGE_LOOP('',(#1710));
#1712=FACE_BOUND('',#1711,.T.);
#1713=ADVANCED_FACE('F565',(#1701,#1712),#1698,.T.);
#1714=CARTESIAN_POINT('',(-27.245882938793,0.,25.999995));
#1715=DIRECTION('',(0.,0.,1.));
#1716=DIRECTION('',(0.,1.,0.));
#1717=AXIS2_PLACEMENT_3D('',#1714,#1715,#1716);
#1718=PLANE('',#1717);
#1719=CARTESIAN_POINT('',(0.,0.,25.999995));
#1720=DIRECTION('',(0.,0.,1.));
#1721=DIRECTION('',(0.,1.,0.));
#1722=AXIS2_PLACEMENT_3D('',#1719,#1720,#1721);
#1723=CIRCLE('',#1722,28.);
#1724=CARTESIAN_POINT('',(0.,28.,25.999995));
#1725=VERTEX_POINT('',#1724);
#1726=EDGE_CURVE('E179',#1725,#1725,#1723,.T.);
#1727=ORIENTED_EDGE('',*,*,#1726,.F.);
#1728=EDGE_LOOP('',(#1727));
#1729=FACE_BOUND('',#1728,.T.);
#1730=ORIENTED_EDGE('',*,*,#1709,.T.);
#1731=EDGE_LOOP('',(#1730));
#1732=FACE_BOUND('',#1731,.T.);
#1733=ADVANCED_FACE('F571',(#1729,#1732),#1718,.F.);
#1734=CARTESIAN_POINT('',(0.,0.,25.999995));
#1735=DIRECTION('',(0.,0.,1.));
#1736=DIRECTION('',(0.,1.,0.));
#1737=AXIS2_PLACEMENT_3D('',#1734,#1735,#1736);
#1738=TOROIDAL_SURFACE('',#1737,25.,3.);
#1739=ORIENTED_EDGE('',*,*,#597,.F.);
#1740=EDGE_LOOP('',(#1739));
#1741=FACE_BOUND('',#1740,.T.);
#1742=ORIENTED_EDGE('',*,*,#1726,.T.);
#1743=EDGE_LOOP('',(#1742));
#1744=FACE_BOUND('',#1743,.T.);
#1745=ADVANCED_FACE('F209',(#1741,#1744),#1738,.T.);
#1746=CARTESIAN_POINT('',(-37.980233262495,30.1149329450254,11.));
#1747=CARTESIAN_POINT('',(-21.6822939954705,28.2585144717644,24.));
#1748=CARTESIAN_POINT('',(-19.6246705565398,-8.00078576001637,11.0000000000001));
#1749=CARTESIAN_POINT('',(-15.354474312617,16.8463348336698,24.));
#1750=CARTESIAN_POINT('',(18.4910481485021,10.3547769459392,11.0000000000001));
#1751=CARTESIAN_POINT('',(-3.59763679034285,22.5081293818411,24.));
#1752=CARTESIAN_POINT('',(0.13548544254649,48.470495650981,11.));
#1753=CARTESIAN_POINT('',(-8.57470707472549,34.570795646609,24.));
#1754=(BOUNDED_SURFACE() B_SPLINE_SURFACE(3,1,((#1746,#1747),(#1748,#1749),(#1750,#1751),(#1752,
#1753)),.UNSPECIFIED.,.F.,.F.,.F.) B_SPLINE_SURFACE_WITH_KNOTS((4,4),(2,2),(0.,1.),(0.,1.),
.UNSPECIFIED.) GEOMETRIC_REPRESENTATION_ITEM() RATIONAL_B_SPLINE_SURFACE(((1.,1.),
(0.333333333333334,0.371630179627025),(0.333333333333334,0.371630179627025),(1.,1.))) REPRESENTATION_ITEM('') SURFACE());
#1755=ORIENTED_EDGE('',*,*,#720,.T.);
#1756=ORIENTED_EDGE('',*,*,#120,.F.);
#1757=ORIENTED_EDGE('',*,*,#1657,.T.);
#1758=ORIENTED_EDGE('',*,*,#852,.F.);
#1759=EDGE_LOOP('',(#1755,#1756,#1757,#1758));
#1760=FACE_BOUND('',#1759,.T.);
#1761=ADVANCED_FACE('F201',(#1760),#1754,.F.);
#1762=CARTESIAN_POINT('',(-0.135485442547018,48.470495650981,11.));
#1763=CARTESIAN_POINT('',(8.57470707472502,34.5707956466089,24.));
#1764=CARTESIAN_POINT('',(-18.4910481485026,10.3547769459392,11.0000000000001));
#1765=CARTESIAN_POINT('',(3.59763679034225,22.508129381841,24.));
#1766=CARTESIAN_POINT('',(19.624670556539,-8.00078576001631,11.0000000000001));
#1767=CARTESIAN_POINT('',(15.3544743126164,16.8463348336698,24.));
#1768=CARTESIAN_POINT('',(37.980233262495,30.1149329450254,11.));
#1769=CARTESIAN_POINT('',(21.6822939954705,28.2585144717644,24.));
#1770=(BOUNDED_SURFACE() B_SPLINE_SURFACE(3,1,((#1762,#1763),(#1764,#1765),(#1766,#1767),(#1768,
#1769)),.UNSPECIFIED.,.F.,.F.,.F.) B_SPLINE_SURFACE_WITH_KNOTS((4,4),(2,2),(0.,1.),(0.,1.),
.UNSPECIFIED.) GEOMETRIC_REPRESENTATION_ITEM() RATIONAL_B_SPLINE_SURFACE(((1.,1.),
(0.333333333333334,0.371630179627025),(0.333333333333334,0.371630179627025),(1.,1.))) REPRESENTATION_ITEM('') SURFACE());
#1771=ORIENTED_EDGE('',*,*,#731,.T.);
#1772=ORIENTED_EDGE('',*,*,#808,.F.);
#1773=ORIENTED_EDGE('',*,*,#1543,.T.);
#1774=ORIENTED_EDGE('',*,*,#575,.F.);
#1775=EDGE_LOOP('',(#1771,#1772,#1773,#1774));
#1776=FACE_BOUND('',#1775,.T.);
#1777=ADVANCED_FACE('F208',(#1776),#1770,.F.);
#1778=CARTESIAN_POINT('',(37.8112856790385,30.3267865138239,11.));
#1779=CARTESIAN_POINT('',(32.3747788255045,14.8505625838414,24.));
#1780=CARTESIAN_POINT('',(-3.43328933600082,20.9129814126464,11.0000000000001));
#1781=CARTESIAN_POINT('',(19.8406540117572,11.2208434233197,24.));
#1782=CARTESIAN_POINT('',(5.98051576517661,-20.3315936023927,11.0000000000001));
#1783=CARTESIAN_POINT('',(22.744353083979,-1.50109344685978,24.));
#1784=CARTESIAN_POINT('',(47.2250907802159,-10.9177885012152,11.));
#1785=CARTESIAN_POINT('',(35.6120854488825,0.666995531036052,24.));
#1786=(BOUNDED_SURFACE() B_SPLINE_SURFACE(3,1,((#1778,#1779),(#1780,#1781),(#1782,#1783),(#1784,
#1785)),.UNSPECIFIED.,.F.,.F.,.F.) B_SPLINE_SURFACE_WITH_KNOTS((4,4),(2,2),(0.,1.),(0.,1.),
.UNSPECIFIED.) GEOMETRIC_REPRESENTATION_ITEM() RATIONAL_B_SPLINE_SURFACE(((1.,1.),
(0.333333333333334,0.371630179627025),(0.333333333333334,0.371630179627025),(1.,1.))) REPRESENTATION_ITEM('') SURFACE());
#1787=ORIENTED_EDGE('',*,*,#739,.T.);
#1788=ORIENTED_EDGE('',*,*,#528,.F.);
#1789=ORIENTED_EDGE('',*,*,#1429,.T.);
#1790=ORIENTED_EDGE('',*,*,#484,.F.);
#1791=EDGE_LOOP('',(#1787,#1788,#1789,#1790));
#1792=FACE_BOUND('',#1791,.T.);
#1793=ADVANCED_FACE('F344',(#1792),#1786,.F.);
#1794=CARTESIAN_POINT('',(47.2853874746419,-10.6536114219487,11.));
#1795=CARTESIAN_POINT('',(31.795981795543,-16.052447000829,24.));
#1796=CARTESIAN_POINT('',(14.2098063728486,15.7232843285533,11.0000000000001));
#1797=CARTESIAN_POINT('',(21.1432540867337,-8.51596649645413,24.));
#1798=CARTESIAN_POINT('',(-12.1670893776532,-17.3522967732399,11.0000000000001));
#1799=CARTESIAN_POINT('',(13.0072700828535,-18.7181677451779,24.));
#1800=CARTESIAN_POINT('',(20.90849172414,-43.7291925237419,11.));
#1801=CARTESIAN_POINT('',(22.7252502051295,-27.4267846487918,24.));
#1802=(BOUNDED_SURFACE() B_SPLINE_SURFACE(3,1,((#1794,#1795),(#1796,#1797),(#1798,#1799),(#1800,
#1801)),.UNSPECIFIED.,.F.,.F.,.F.) B_SPLINE_SURFACE_WITH_KNOTS((4,4),(2,2),(0.,1.),(0.,1.),
.UNSPECIFIED.) GEOMETRIC_REPRESENTATION_ITEM() RATIONAL_B_SPLINE_SURFACE(((1.,1.),
(0.333333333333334,0.371630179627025),(0.333333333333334,0.371630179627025),(1.,1.))) REPRESENTATION_ITEM('') SURFACE());
#1803=ORIENTED_EDGE('',*,*,#747,.T.);
#1804=ORIENTED_EDGE('',*,*,#437,.F.);
#1805=ORIENTED_EDGE('',*,*,#1315,.T.);
#1806=ORIENTED_EDGE('',*,*,#393,.F.);
#1807=EDGE_LOOP('',(#1803,#1804,#1805,#1806));
#1808=FACE_BOUND('',#1807,.T.);
#1809=ADVANCED_FACE('F339',(#1808),#1802,.F.);
#1810=CARTESIAN_POINT('',(21.1526280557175,-43.6116226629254,11.));
#1811=CARTESIAN_POINT('',(7.2741619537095,-34.8676365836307,24.));
#1812=CARTESIAN_POINT('',(21.1526280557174,-1.30636655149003,11.0000000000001));
#1813=CARTESIAN_POINT('',(6.52455259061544,-21.8400799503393,24.));
#1814=CARTESIAN_POINT('',(-21.1526280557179,-1.30636655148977,11.0000000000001));
#1815=CARTESIAN_POINT('',(-6.5245525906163,-21.8400799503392,24.));
#1816=CARTESIAN_POINT('',(-21.152628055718,-43.6116226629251,11.));
#1817=CARTESIAN_POINT('',(-7.27416195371,-34.8676365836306,24.));
#1818=(BOUNDED_SURFACE() B_SPLINE_SURFACE(3,1,((#1810,#1811),(#1812,#1813),(#1814,#1815),(#1816,
#1817)),.UNSPECIFIED.,.F.,.F.,.F.) B_SPLINE_SURFACE_WITH_KNOTS((4,4),(2,2),(0.,1.),(0.,1.),
.UNSPECIFIED.) GEOMETRIC_REPRESENTATION_ITEM() RATIONAL_B_SPLINE_SURFACE(((1.,1.),
(0.333333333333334,0.371630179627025),(0.333333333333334,0.371630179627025),(1.,1.))) REPRESENTATION_ITEM('') SURFACE());
#1819=ORIENTED_EDGE('',*,*,#755,.T.);
#1820=ORIENTED_EDGE('',*,*,#346,.F.);
#1821=ORIENTED_EDGE('',*,*,#1201,.T.);
#1822=ORIENTED_EDGE('',*,*,#302,.F.);
#1823=EDGE_LOOP('',(#1819,#1820,#1821,#1822));
#1824=FACE_BOUND('',#1823,.T.);
#1825=ADVANCED_FACE('F280',(#1824),#1818,.F.);
#1826=CARTESIAN_POINT('',(-20.908491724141,-43.7291925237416,11.));
#1827=CARTESIAN_POINT('',(-22.72525020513,-27.4267846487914,24.));
#1828=CARTESIAN_POINT('',(12.1670893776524,-17.35229677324,11.0000000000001));
#1829=CARTESIAN_POINT('',(-13.0072700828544,-18.7181677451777,24.));
#1830=CARTESIAN_POINT('',(-14.2098063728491,15.7232843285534,11.0000000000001));
#1831=CARTESIAN_POINT('',(-21.1432540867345,-8.5159664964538,24.));
#1832=CARTESIAN_POINT('',(-47.2853874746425,-10.6536114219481,11.));
#1833=CARTESIAN_POINT('',(-31.7959817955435,-16.0524470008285,24.));
#1834=(BOUNDED_SURFACE() B_SPLINE_SURFACE(3,1,((#1826,#1827),(#1828,#1829),(#1830,#1831),(#1832,
#1833)),.UNSPECIFIED.,.F.,.F.,.F.) B_SPLINE_SURFACE_WITH_KNOTS((4,4),(2,2),(0.,1.),(0.,1.),
.UNSPECIFIED.) GEOMETRIC_REPRESENTATION_ITEM() RATIONAL_B_SPLINE_SURFACE(((1.,1.),
(0.333333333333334,0.371630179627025),(0.333333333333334,0.371630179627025),(1.,1.))) REPRESENTATION_ITEM('') SURFACE());
#1835=ORIENTED_EDGE('',*,*,#763,.T.);
#1836=ORIENTED_EDGE('',*,*,#255,.F.);
#1837=ORIENTED_EDGE('',*,*,#1087,.T.);
#1838=ORIENTED_EDGE('',*,*,#211,.F.);
#1839=EDGE_LOOP('',(#1835,#1836,#1837,#1838));
#1840=FACE_BOUND('',#1839,.T.);
#1841=ADVANCED_FACE('F275',(#1840),#1834,.F.);
#1842=CARTESIAN_POINT('',(-47.2250907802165,-10.9177885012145,11.));
#1843=CARTESIAN_POINT('',(-35.6120854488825,0.666995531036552,24.));
#1844=CARTESIAN_POINT('',(-5.98051576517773,-20.3315936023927,11.0000000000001));
#1845=CARTESIAN_POINT('',(-22.7443530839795,-1.50109344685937,24.));
#1846=CARTESIAN_POINT('',(3.43328933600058,20.9129814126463,11.0000000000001));
#1847=CARTESIAN_POINT('',(-19.8406540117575,11.22084342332,24.));
#1848=CARTESIAN_POINT('',(-37.811285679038,30.3267865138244,11.));
#1849=CARTESIAN_POINT('',(-32.3747788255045,14.8505625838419,24.));
#1850=(BOUNDED_SURFACE() B_SPLINE_SURFACE(3,1,((#1842,#1843),(#1844,#1845),(#1846,#1847),(#1848,
#1849)),.UNSPECIFIED.,.F.,.F.,.F.) B_SPLINE_SURFACE_WITH_KNOTS((4,4),(2,2),(0.,1.),(0.,1.),
.UNSPECIFIED.) GEOMETRIC_REPRESENTATION_ITEM() RATIONAL_B_SPLINE_SURFACE(((1.,1.),
(0.333333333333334,0.371630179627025),(0.333333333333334,0.371630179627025),(1.,1.))) REPRESENTATION_ITEM('') SURFACE());
#1851=ORIENTED_EDGE('',*,*,#710,.T.);
#1852=ORIENTED_EDGE('',*,*,#164,.F.);
#1853=ORIENTED_EDGE('',*,*,#973,.T.);
#1854=ORIENTED_EDGE('',*,*,#78,.F.);
#1855=EDGE_LOOP('',(#1851,#1852,#1853,#1854));
#1856=FACE_BOUND('',#1855,.T.);
#1857=ADVANCED_FACE('F121',(#1856),#1850,.F.);
#1858=CLOSED_SHELL('',(#124,#215,#306,#397,#488,#579,#601,#618,#638,#658,#678,#698,#770,#856,
#1673,#1693,#1713,#1733,#1745,#1761,#1777,#1793,#1809,#1825,#1841,#1857));
#1859=MANIFOLD_SOLID_BREP('B1',#1858);
#1860=ADVANCED_BREP_SHAPE_REPRESENTATION('',(#18,#1859),#14);
#1861=SHAPE_DEFINITION_REPRESENTATION(#9,#1860);
ENDSEC;
END-ISO-10303-21;
